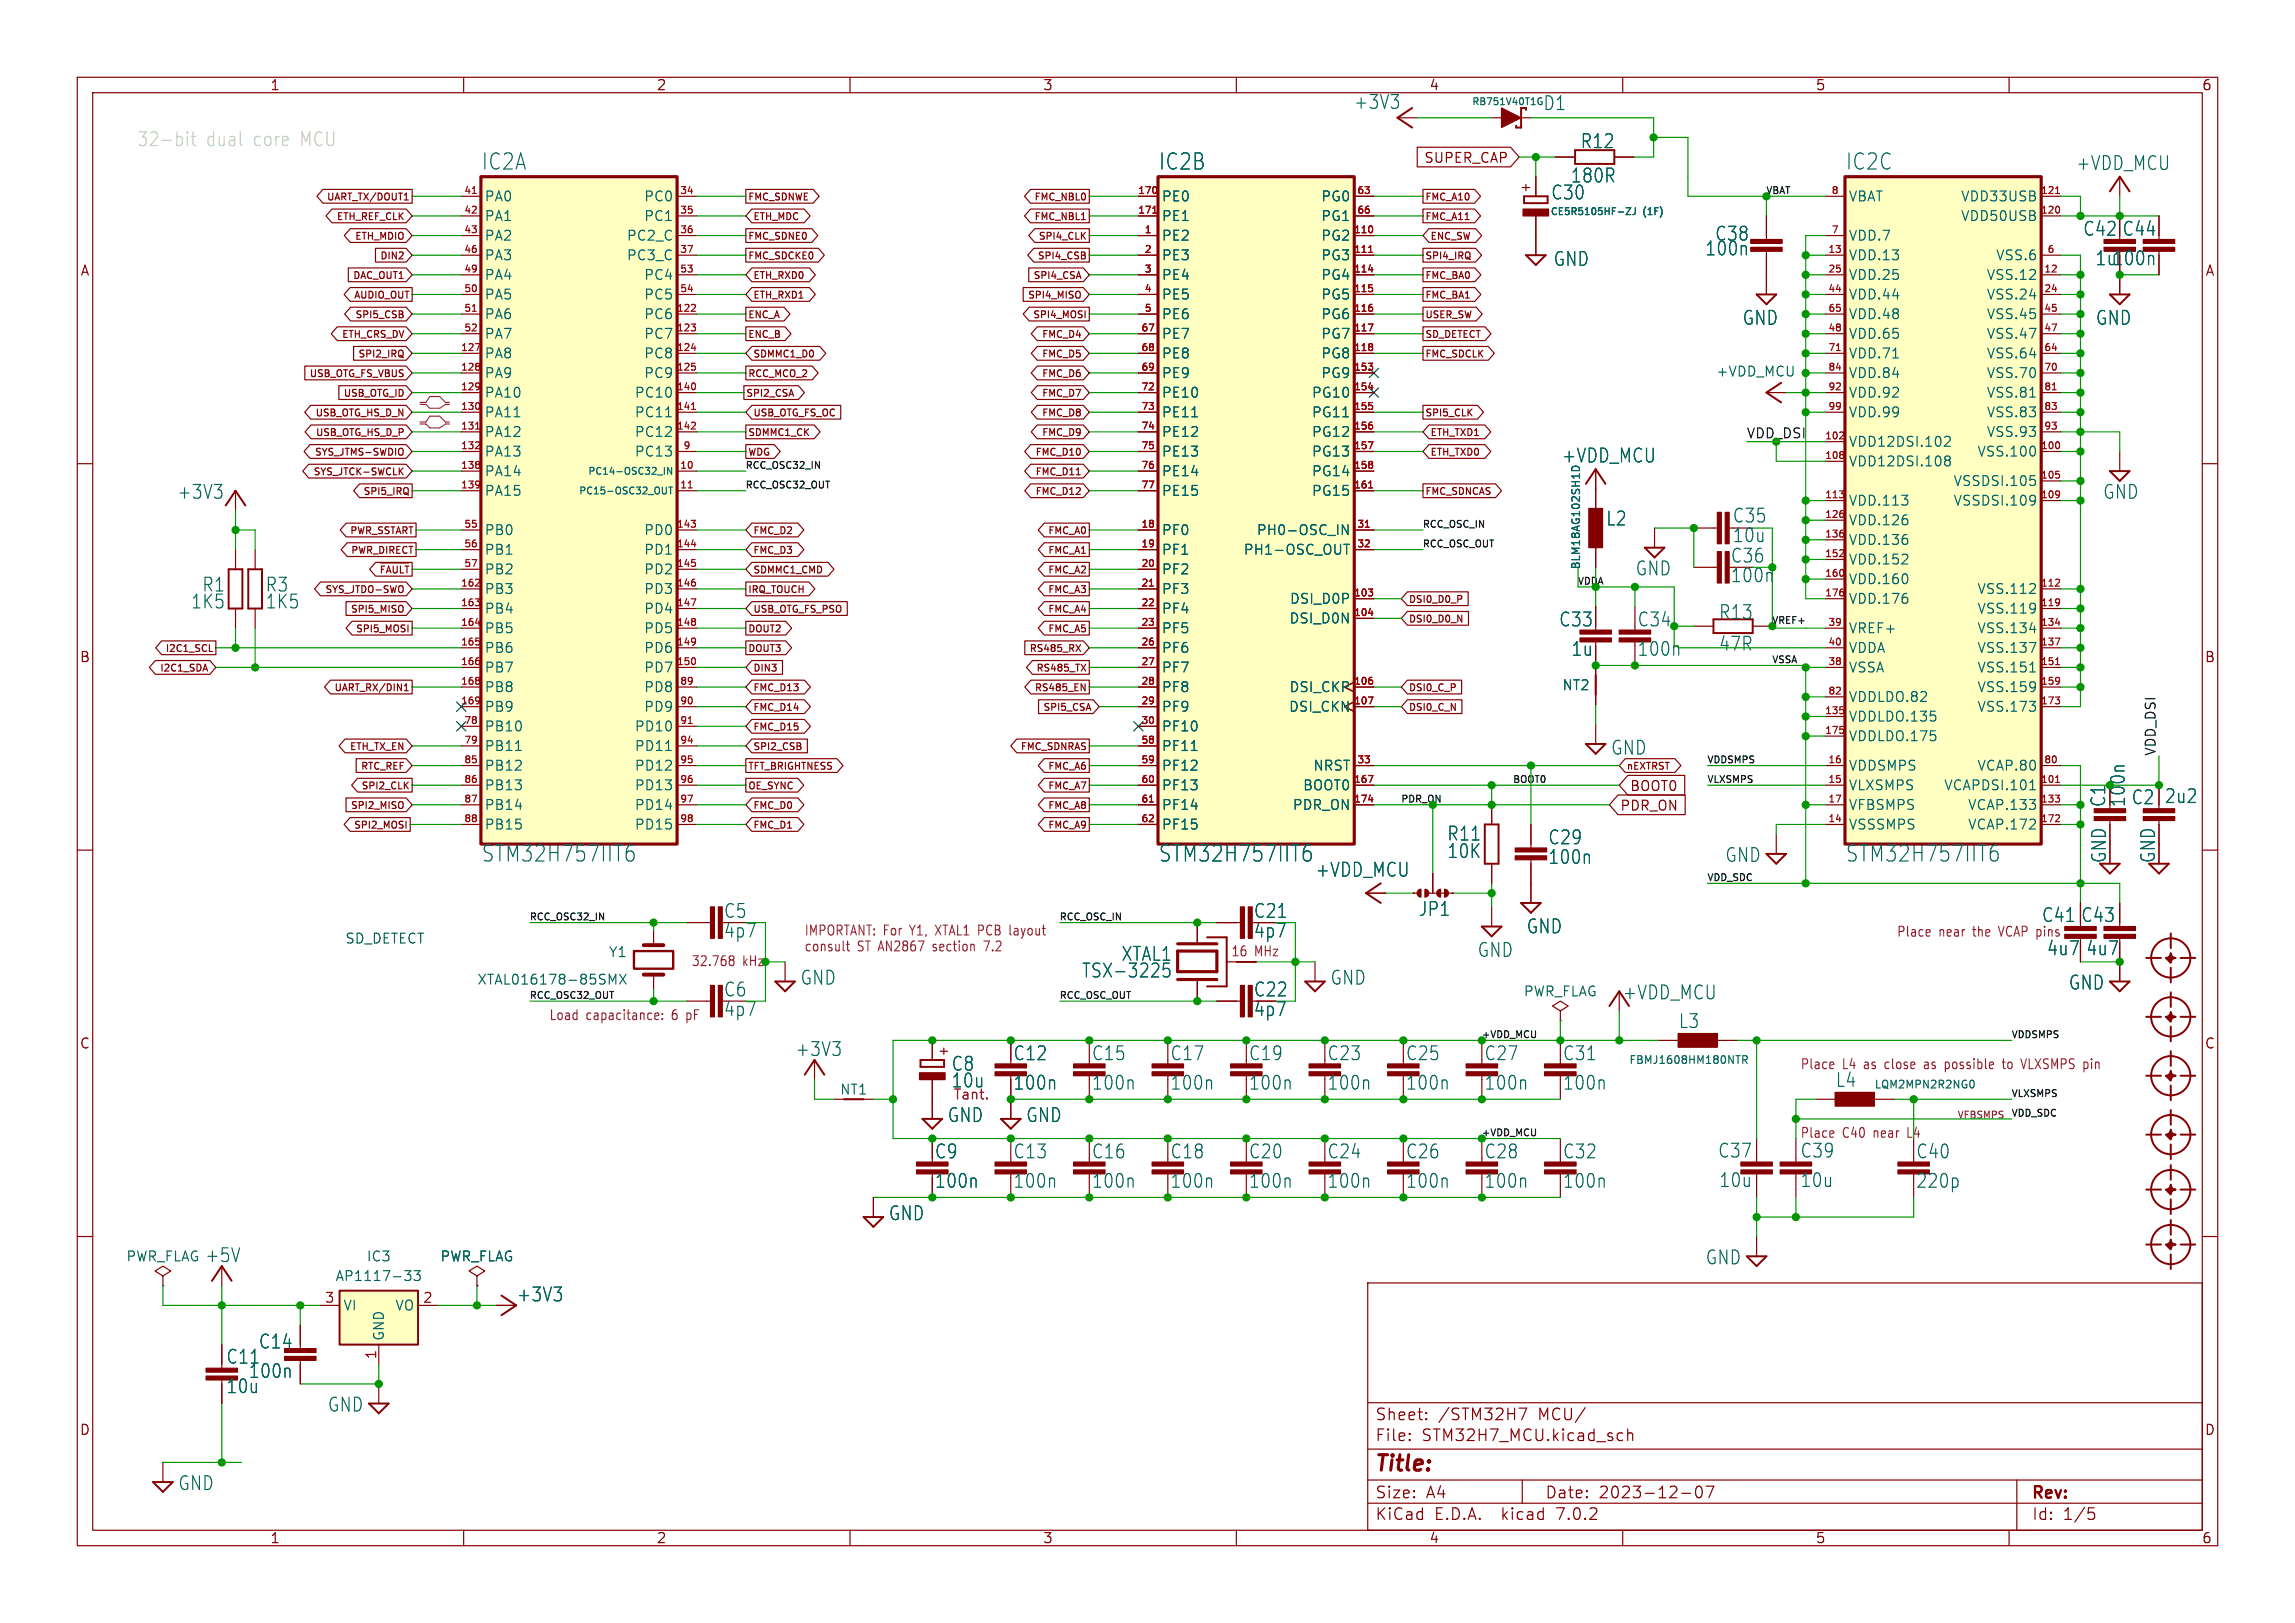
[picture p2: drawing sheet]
<svg xmlns="http://www.w3.org/2000/svg" width="297mm" height="210mm" viewBox="0 0 297 210" stroke-linecap="round" stroke-linejoin="round" font-family="sans-serif">
<defs><g id="words">
<g font-size="2.9" fill="#006464">
<text x="62.3" y="22.1">IC2A</text>
<text x="149.9" y="22.1">IC2B</text>
<text x="238.8" y="22.1">IC2C</text>
<text x="62.3" y="111.7">STM32H757IIT6</text>
<text x="149.9" y="111.7">STM32H757IIT6</text>
<text x="238.8" y="111.7">STM32H757IIT6</text>
</g>
<text font-size="2.8" fill="#840000" x="178" y="190.8">Title:</text>
<g font-size="2.5" fill="#006464">
<text x="175.2" y="14.3">+3V3</text>
<text x="199.7" y="14.4">D1</text>
<text x="203.2" y="23.8">180R</text>
<text x="204.5" y="19.3">R12</text>
<text x="268.7" y="22.2">+VDD_MCU</text>
<text x="200.7" y="26">C30</text>
<text x="201" y="34.6">GND</text>
<text x="220.6" y="33.2">100n</text>
<text x="221.9" y="31.3">C38</text>
<text x="269.6" y="30.7">C42 C44</text>
<text x="271.1" y="34.5">1u100n</text>
<text x="225.5" y="42.2">GND</text>
<text x="271.2" y="42.2">GND</text>
<text x="22.9" y="64.7">+3V3</text>
<text x="202.1" y="60">+VDD_MCU</text>
<text x="272.1" y="64.7">GND</text>
<text x="207.8" y="68.2">L2</text>
<text x="224.2" y="70.3">10u</text>
<text x="224.2" y="67.8">C35</text>
<text x="26.1" y="76.7">R1</text>
<text x="34.3" y="76.7">R3</text>
<text x="211.6" y="74.6">GND</text>
<text x="223.9" y="73">C36</text>
<text x="223.9" y="75.5">100n</text>
<text x="24.7" y="78.9">1K5</text>
<text x="34.3" y="78.9">1K5</text>
<text x="201.7" y="81.2">C33</text>
<text x="211.9" y="81.2">C34</text>
<text x="222.4" y="80.3">R13</text>
<text x="203.3" y="85">1u</text>
<text x="222.4" y="84.4">47R</text>
<text x="208.5" y="97.8">GND</text>
<text x="275.8" y="104.2">C2</text>
<text x="170.2" y="113.6">+VDD_MCU</text>
<text x="187.3" y="108.9">R11</text>
<text x="187.3" y="111.2">10K</text>
<text x="200.3" y="109.4">C29</text>
<text x="200.3" y="112">100n</text>
<text x="223.2" y="111.7">GND</text>
<text x="93.6" y="119">C5</text>
<text x="183.6" y="118.7">JP1</text>
<text x="264.2" y="119.5">C41 C43</text>
<text x="93.6" y="121.5">4p7</text>
<text x="145.1" y="124.5">XTAL1</text>
<text x="162.2" y="121.5">4p7</text>
<text x="191.2" y="124">GND</text>
<text x="197.5" y="120.9">GND</text>
<text x="264.9" y="123.8">4u7</text>
<text x="269.9" y="123.8">4u7</text>
<text x="93.6" y="129.1">C6</text>
<text x="93.6" y="131.7">4p7</text>
<text x="103.6" y="127.6">GND</text>
<text x="140" y="126.7">TSX-3225</text>
<text x="162.2" y="131.7">4p7</text>
<text x="172.1" y="127.6">GND</text>
<text x="210" y="129.5">+VDD_MCU</text>
<text x="267.7" y="128.2">GND</text>
<text x="102.9" y="136.8">+3V3</text>
<text x="131.1" y="137.4">C12</text>
<text x="141.3" y="137.4">C15</text>
<text x="151.4" y="137.4">C17</text>
<text x="161.6" y="137.4">C19</text>
<text x="171.7" y="137.4">C23</text>
<text x="181.9" y="137.4">C25</text>
<text x="192.1" y="137.4">C27</text>
<text x="202.2" y="137.4">C31</text>
<text x="217.2" y="133.2">L3</text>
<text x="123.1" y="138.7">C8</text>
<text x="123.1" y="140.9">10u</text>
<text x="131.1" y="141.2">100n</text>
<text x="141.3" y="141.2">100n</text>
<text x="151.4" y="141.2">100n</text>
<text x="161.6" y="141.2">100n</text>
<text x="171.7" y="141.2">100n</text>
<text x="181.9" y="141.2">100n</text>
<text x="192.1" y="141.2">100n</text>
<text x="202.2" y="141.2">100n</text>
<text x="122.6" y="145.4">GND</text>
<text x="132.8" y="145.4">GND</text>
<text x="222.3" y="150">C37</text>
<text x="233" y="150">C39</text>
<text x="120.9" y="150.1">C9</text>
<text x="120.9" y="153.9">100n</text>
<text x="131.1" y="150.1">C13</text>
<text x="131.1" y="153.9">100n</text>
<text x="141.3" y="150.1">C16</text>
<text x="141.3" y="153.9">100n</text>
<text x="151.4" y="150.1">C18</text>
<text x="151.4" y="153.9">100n</text>
<text x="161.6" y="150.1">C20</text>
<text x="161.6" y="153.9">100n</text>
<text x="171.7" y="150.1">C24</text>
<text x="171.7" y="153.9">100n</text>
<text x="181.9" y="150.1">C26</text>
<text x="181.9" y="153.9">100n</text>
<text x="192.1" y="150.1">C28</text>
<text x="192.1" y="153.9">100n</text>
<text x="202.2" y="150.1">C32</text>
<text x="202.2" y="153.9">100n</text>
<text x="222.5" y="153.8">10u</text>
<text x="233" y="153.8">10u</text>
<text x="247.9" y="150.1">C40</text>
<text x="247.9" y="153.9">220p</text>
<text x="115" y="158.1">GND</text>
<text x="26.5" y="163.5">+5V</text>
<text x="220.7" y="163.8">GND</text>
<text x="66.8" y="168.6">+3V3</text>
<text x="29.3" y="176.6">C11</text>
<text x="32.2" y="178.5">100n</text>
<text x="33.5" y="174.7">C14</text>
<text x="29.3" y="180.4">10u</text>
<text x="42.4" y="182.8">GND</text>
<text x="23" y="193">GND</text>
</g>
<g font-size="2.5" fill="#c2c2c2">
<text x="17.8" y="19.1">32-bit</text>
<text x="26.7" y="19.1">dual</text>
<text x="32.8" y="19.1">core</text>
<text x="39" y="19.1">MCU</text>
</g>
<g font-size="2.5" fill="#009600">
<text x="211.9" y="85">100n</text>
<text x="275.2" y="104.5" transform="rotate(-90 275.2 104.5)">100n</text>
</g>
<g font-size="2.5" fill="#840000">
<text x="272.6" y="104.5" transform="rotate(-90 272.6 104.5)">C1</text>
<text x="280.1" y="104.1">2u2</text>
<text x="272.7" y="111.7" transform="rotate(-90 272.7 111.7)">GND</text>
<text x="279.1" y="111.7" transform="rotate(-90 279.1 111.7)">GND</text>
<text x="162.2" y="119">C21</text>
<text x="162.2" y="129.1">C22</text>
</g>
<text font-size="2.5" fill="#840084" x="237.5" y="140.8">L4</text>
<g font-size="2.1" fill="#840000">
<text x="178" y="183.9">Sheet:</text>
<text x="186.2" y="183.9">/STM32H7</text>
<text x="199.1" y="183.9">MCU/</text>
<text x="178" y="186.6">File:</text>
<text x="184" y="186.6">STM32H7_MCU.kicad_sch</text>
<text x="178" y="196.8">KiCad</text>
<text x="178" y="194">Size:</text>
<text x="184.6" y="194">A4</text>
<text x="185.7" y="196.8">E.D.A.</text>
<text x="194.4" y="196.8">kicad</text>
<text x="200" y="194">Date:</text>
<text x="201.5" y="196.8">7.0.2</text>
<text x="206.9" y="194">2023-12-07</text>
<text x="263" y="194.2">Rev:</text>
<text x="263" y="196.8">Id:</text>
<text x="267" y="196.8">1/5</text>
</g>
<g font-size="1.8" fill="#840000">
<text x="35" y="11.8">1</text>
<text x="85" y="11.8">2</text>
<text x="135" y="11.8">3</text>
<text x="185" y="11.8">4</text>
<text x="235" y="11.8">5</text>
<text x="285" y="11.8">6</text>
<text x="184.2" y="21.2">SUPER_CAP</text>
<text x="198.2" y="25" transform="rotate(-90 198.2 25)">+</text>
<text x="10.4" y="35.8">A</text>
<text x="285.4" y="35.8">A</text>
<text x="10.3" y="85.8">B</text>
<text x="285.3" y="85.8">B</text>
<text x="209.7" y="105.1">PDR_ON</text>
<text x="211" y="102.5">BOOT0</text>
<text x="10.3" y="135.8">C</text>
<text x="122.9" y="136.8" transform="rotate(-90 122.9 136.8)">+</text>
<text x="285.3" y="135.8">C</text>
<text x="10.3" y="185.8">D</text>
<text x="285.3" y="185.8">D</text>
<text x="35" y="199.8">1</text>
<text x="85" y="199.8">2</text>
<text x="135" y="199.8">3</text>
<text x="185" y="199.8">4</text>
<text x="235" y="199.8">5</text>
<text x="285" y="199.8">6</text>
</g>
<g font-size="1.8" fill="#006464">
<text x="62.7" y="26.2">PA0</text>
<text x="62.7" y="28.8">PA1</text>
<text x="83.2" y="26.2">PC0</text>
<text x="83.2" y="28.8">PC1</text>
<text x="150.4" y="26.2">PE0</text>
<text x="150.4" y="28.8">PE1</text>
<text x="170.9" y="26.2">PG0</text>
<text x="170.9" y="28.8">PG1</text>
<text x="239.3" y="26.2">VBAT</text>
<text x="253.7" y="28.8">VDD50USB</text>
<text x="253.7" y="26.2">VDD33USB</text>
<text x="62.7" y="31.3">PA2</text>
<text x="62.7" y="33.8">PA3</text>
<text x="81" y="31.3">PC2_C</text>
<text x="81" y="33.8">PC3_C</text>
<text x="150.4" y="31.3">PE2</text>
<text x="150.4" y="33.8">PE3</text>
<text x="170.9" y="31.3">PG2</text>
<text x="170.9" y="33.8">PG3</text>
<text x="239.3" y="33.8">VDD.13</text>
<text x="239.3" y="31.3">VDD.7</text>
<text x="258.2" y="33.8">VSS.6</text>
<text x="62.7" y="36.4">PA4</text>
<text x="62.7" y="38.9">PA5</text>
<text x="62.7" y="41.5">PA6</text>
<text x="83.2" y="41.5">PC6</text>
<text x="83.2" y="36.4">PC4</text>
<text x="83.2" y="38.9">PC5</text>
<text x="150.4" y="36.4">PE4</text>
<text x="150.4" y="38.9">PE5</text>
<text x="150.4" y="41.5">PE6</text>
<text x="170.9" y="36.4">PG4</text>
<text x="170.9" y="38.9">PG5</text>
<text x="170.9" y="41.5">PG6</text>
<text x="239.3" y="36.4">VDD.25</text>
<text x="239.3" y="38.9">VDD.44</text>
<text x="239.3" y="41.5">VDD.48</text>
<text x="257" y="36.4">VSS.12</text>
<text x="257" y="38.9">VSS.24</text>
<text x="257" y="41.5">VSS.45</text>
<text x="62.7" y="46.5">PA8</text>
<text x="62.7" y="44">PA7</text>
<text x="83.2" y="44">PC7</text>
<text x="83.2" y="46.5">PC8</text>
<text x="150.4" y="44">PE7</text>
<text x="150.4" y="46.5">PE8</text>
<text x="170.9" y="44">PG7</text>
<text x="170.9" y="46.5">PG8</text>
<text x="239.3" y="44">VDD.65</text>
<text x="239.3" y="46.5">VDD.71</text>
<text x="257" y="44">VSS.47</text>
<text x="257" y="46.5">VSS.64</text>
<text x="62.7" y="49.1">PA9</text>
<text x="62.7" y="51.6">PA10</text>
<text x="82" y="51.6">PC10</text>
<text x="83.2" y="49.1">PC9</text>
<text x="150.4" y="49.1">PE9</text>
<text x="150.4" y="51.6">PE10</text>
<text x="169.7" y="51.6">PG10</text>
<text x="170.9" y="49.1">PG9</text>
<text x="222.1" y="48.9">+VDD_MCU</text>
<text x="239.3" y="49.1">VDD.84</text>
<text x="239.3" y="51.6">VDD.92</text>
<text x="257" y="49.1">VSS.70</text>
<text x="257" y="51.6">VSS.81</text>
<text x="62.7" y="54.2">PA11</text>
<text x="62.7" y="56.7">PA12</text>
<text x="62.7" y="59.2">PA13</text>
<text x="82" y="54.2">PC11</text>
<text x="82" y="56.7">PC12</text>
<text x="82" y="59.2">PC13</text>
<text x="150.4" y="54.2">PE11</text>
<text x="150.4" y="56.7">PE12</text>
<text x="150.4" y="59.2">PE13</text>
<text x="169.7" y="54.2">PG11</text>
<text x="169.7" y="56.7">PG12</text>
<text x="169.7" y="59.2">PG13</text>
<text x="239.3" y="58">VDD12DSI.102</text>
<text x="239.3" y="54.2">VDD.99</text>
<text x="255.8" y="59.2">VSS.100</text>
<text x="257" y="54.2">VSS.83</text>
<text x="257" y="56.7">VSS.93</text>
<text x="62.7" y="61.8">PA14</text>
<text x="62.7" y="64.3">PA15</text>
<text x="150.4" y="61.8">PE14</text>
<text x="150.4" y="64.3">PE15</text>
<text x="169.7" y="61.8">PG14</text>
<text x="169.7" y="64.3">PG15</text>
<text x="239.3" y="60.5">VDD12DSI.108</text>
<text x="239.3" y="65.6">VDD.113</text>
<text x="252.7" y="63.1">VSSDSI.105</text>
<text x="252.7" y="65.6">VSSDSI.109</text>
<text x="62.7" y="69.4">PB0</text>
<text x="62.7" y="71.9">PB1</text>
<text x="83.2" y="69.4">PD0</text>
<text x="83.2" y="71.9">PD1</text>
<text x="150.4" y="69.4">PF0</text>
<text x="150.4" y="71.9">PF1</text>
<text x="160.8" y="71.9">PH1-OSC_OUT</text>
<text x="162.5" y="69.4">PH0-OSC_IN</text>
<text x="239.3" y="68.1">VDD.126</text>
<text x="239.3" y="70.7">VDD.136</text>
<text x="62.7" y="77">PB3</text>
<text x="62.7" y="74.5">PB2</text>
<text x="83.2" y="74.5">PD2</text>
<text x="83.2" y="77">PD3</text>
<text x="150.4" y="74.5">PF2</text>
<text x="150.4" y="77">PF3</text>
<text x="239.3" y="73.2">VDD.152</text>
<text x="239.3" y="75.8">VDD.160</text>
<text x="255.8" y="77">VSS.112</text>
<text x="62.7" y="79.6">PB4</text>
<text x="62.7" y="82.1">PB5</text>
<text x="83.2" y="79.6">PD4</text>
<text x="83.2" y="82.1">PD5</text>
<text x="150.4" y="79.6">PF4</text>
<text x="150.4" y="82.1">PF5</text>
<text x="166.8" y="80.8">DSI_D0N</text>
<text x="166.8" y="78.3">DSI_D0P</text>
<text x="239.3" y="78.3">VDD.176</text>
<text x="239.3" y="82.1">VREF+</text>
<text x="255.8" y="79.6">VSS.119</text>
<text x="255.8" y="82.1">VSS.134</text>
<text x="62.7" y="84.6">PB6</text>
<text x="62.7" y="87.2">PB7</text>
<text x="62.7" y="89.7">PB8</text>
<text x="83.2" y="84.6">PD6</text>
<text x="83.2" y="87.2">PD7</text>
<text x="83.2" y="89.7">PD8</text>
<text x="150.4" y="84.6">PF6</text>
<text x="150.4" y="87.2">PF7</text>
<text x="150.4" y="89.7">PF8</text>
<text x="166.8" y="89.7">DSI_CKP</text>
<text x="202.1" y="89.5">NT2</text>
<text x="239.3" y="87.2">VSSA</text>
<text x="239.3" y="84.6">VDDA</text>
<text x="255.8" y="84.6">VSS.137</text>
<text x="255.8" y="87.2">VSS.151</text>
<text x="255.8" y="89.7">VSS.159</text>
<text x="62.7" y="92.3">PB9</text>
<text x="62.7" y="94.8">PB10</text>
<text x="82" y="94.8">PD10</text>
<text x="83.2" y="92.3">PD9</text>
<text x="150.4" y="92.3">PF9</text>
<text x="150.4" y="94.8">PF10</text>
<text x="166.7" y="92.3">DSI_CKN</text>
<text x="239.3" y="93.5">VDDLDO.135</text>
<text x="239.3" y="91">VDDLDO.82</text>
<text x="255.8" y="92.3">VSS.173</text>
<text x="62.7" y="97.3">PB11</text>
<text x="62.7" y="99.9">PB12</text>
<text x="82" y="97.3">PD11</text>
<text x="82" y="99.9">PD12</text>
<text x="150.4" y="97.3">PF11</text>
<text x="150.4" y="99.9">PF12</text>
<text x="169.8" y="99.9">NRST</text>
<text x="239.3" y="99.9">VDDSMPS</text>
<text x="239.3" y="96.1">VDDLDO.175</text>
<text x="255.8" y="99.9">VCAP.80</text>
<text x="62.7" y="102.4">PB13</text>
<text x="62.7" y="105">PB14</text>
<text x="62.7" y="107.5">PB15</text>
<text x="82" y="102.4">PD13</text>
<text x="82" y="105">PD14</text>
<text x="82" y="107.5">PD15</text>
<text x="150.4" y="102.4">PF13</text>
<text x="150.4" y="105">PF14</text>
<text x="150.4" y="107.5">PF15</text>
<text x="167.2" y="105">PDR_ON</text>
<text x="168.5" y="102.4">BOOT0</text>
<text x="239.3" y="107.5">VSSSMPS</text>
<text x="239.3" y="102.4">VLXSMPS</text>
<text x="239.3" y="105">VFBSMPS</text>
<text x="251.5" y="102.4">VCAPDSI.101</text>
<text x="254.6" y="105">VCAP.133</text>
<text x="254.6" y="107.5">VCAP.172</text>
<text x="78.7" y="124">Y1</text>
<text x="61.7" y="127.6">XTAL016178-85SMX</text>
<text x="197.1" y="129.1">PWR_FLAG</text>
<text x="108.7" y="141.8">NT1</text>
<text x="16.3" y="163.4">PWR_FLAG</text>
<text x="43.4" y="165.9">AP1117-33</text>
<text x="47.4" y="163.4">IC3</text>
<text x="56.9" y="163.4">PWR_FLAG</text>
<text x="44.4" y="169.7">VI</text>
<text x="49.8" y="173.5" transform="rotate(-90 49.8 173.5)">GND</text>
<text x="51" y="169.7">VO</text>
</g>
<text font-size="1.8" fill="#009600" x="226.1" y="56.8">VDD_DSI</text>
<text font-size="1.8" fill="#0f0f0f" x="279" y="97.8" transform="rotate(-90 279 97.8)">VDD_DSI</text>
<text font-size="1.8" fill="#0000c2" x="44.7" y="122.2">SD_DETECT</text>
<g font-size="1.8" fill="#840084">
<text x="89.5" y="125.1">32.768</text>
<text x="96.2" y="125.1">kHz</text>
<text x="104.1" y="121.1">IMPORTANT: For</text>
<text x="104.1" y="123.2">consult</text>
<text x="111" y="123.2">ST AN2867</text>
<text x="117.9" y="121.1">Y1, XTAL1 PCB layout</text>
<text x="121" y="123.2">section</text>
<text x="127.8" y="123.2">7.2</text>
<text x="159.4" y="123.8">16</text>
<text x="162.4" y="123.8">MHz</text>
<text x="245.4" y="121.3">Place</text>
<text x="250.8" y="121.3">near</text>
<text x="255.4" y="121.3">the</text>
<text x="258.9" y="121.3">VCAP pins</text>
<text x="71.1" y="132.1">Load</text>
<text x="75.9" y="132.1">capacitance:</text>
<text x="87.1" y="132.1">6 pF</text>
<text x="123.4" y="142.4">Tant.</text>
<text x="233" y="138.4">Place</text>
<text x="238.5" y="138.4">L4 as</text>
<text x="244.2" y="138.4">close</text>
<text x="249.5" y="138.4">as</text>
<text x="252.3" y="138.4">possible</text>
<text x="260" y="138.4">to</text>
<text x="262.6" y="138.4">VLXSMPS pin</text>
<text x="233" y="147.3">Place</text>
<text x="238.5" y="147.3">C40</text>
<text x="242.6" y="147.3">near</text>
<text x="247.2" y="147.3">L4</text>
</g>
<g font-size="1.8" fill="#a90000">
<text x="42" y="168.7">3</text>
<text x="54.7" y="168.7">2</text>
<text x="48.8" y="175.9" transform="rotate(-90 48.8 175.9)">1</text>
</g>
<g font-size="1.4" fill="#006464">
<text x="204.6" y="73.7" transform="rotate(-90 204.6 73.7)">BLM18AG102SH1D</text>
<text x="210.8" y="137.8">FBMJ1608HM180NTR</text>
<text x="242.5" y="141">LQM2MPN2R2NG0</text>
</g>
<g font-size="1.2" fill="#006464">
<text x="190.4" y="13.8">RB751V40T1G</text>
<text x="200.6" y="28">CE5R5105HF-ZJ</text>
<text x="212.6" y="28">(1F)</text>
<text x="74.8" y="64.1">PC15-OSC32_OUT</text>
<text x="76" y="61.6">PC14-OSC32_IN</text>
</g>
<g font-size="1.2" fill="#840000">
<text x="42.1" y="26.1">UART_TX/DOUT1</text>
<text x="43.4" y="28.6">ETH_REF_CLK</text>
<text x="96.9" y="26.1">FMC_SDNWE</text>
<text x="97.5" y="28.6">ETH_MDC</text>
<text x="133.7" y="26.1">FMC_NBL0</text>
<text x="133.7" y="28.6">FMC_NBL1</text>
<text x="184.5" y="26.1">FMC_A10</text>
<text x="184.5" y="28.6">FMC_A11</text>
<text x="45.8" y="31.2">ETH_MDIO</text>
<text x="49" y="33.7">DIN2</text>
<text x="96.9" y="33.7">FMC_SDCKE0</text>
<text x="96.9" y="31.2">FMC_SDNE0</text>
<text x="134.1" y="33.7">SPI4_CSB</text>
<text x="134.3" y="31.2">SPI4_CLK</text>
<text x="184.5" y="33.7">SPI4_IRQ</text>
<text x="185.2" y="31.2">ENC_SW</text>
<text x="45.5" y="36.3">DAC_OUT1</text>
<text x="45.6" y="38.8">AUDIO_OUT</text>
<text x="45.8" y="41.3">SPI5_CSB</text>
<text x="96.9" y="41.3">ENC_A</text>
<text x="97.5" y="36.3">ETH_RXD0</text>
<text x="97.5" y="38.8">ETH_RXD1</text>
<text x="132.9" y="38.8">SPI4_MISO</text>
<text x="133.5" y="41.3">SPI4_MOSI</text>
<text x="133.6" y="36.3">SPI4_CSA</text>
<text x="184.5" y="41.3">USER_SW</text>
<text x="184.5" y="38.8">FMC_BA1</text>
<text x="184.5" y="36.3">FMC_BA0</text>
<text x="44.1" y="43.9">ETH_CRS_DV</text>
<text x="46.2" y="46.4">SPI2_IRQ</text>
<text x="96.9" y="43.9">ENC_B</text>
<text x="97.5" y="46.4">SDMMC1_D0</text>
<text x="134.7" y="43.9">FMC_D4</text>
<text x="134.7" y="46.4">FMC_D5</text>
<text x="184.5" y="46.4">FMC_SDCLK</text>
<text x="184.5" y="43.9">SD_DETECT</text>
<text x="39.9" y="49">USB_OTG_FS_VBUS</text>
<text x="44.3" y="51.5">USB_OTG_ID</text>
<text x="96.6" y="51.5">SPI2_CSA</text>
<text x="96.9" y="49">RCC_MCO_2</text>
<text x="134.7" y="49">FMC_D6</text>
<text x="134.7" y="51.5">FMC_D7</text>
<text x="40.6" y="59.1">SYS_JTMS-SWDIO</text>
<text x="40.7" y="54">USB_OTG_HS_D_N</text>
<text x="40.7" y="56.6">USB_OTG_HS_D_P</text>
<text x="96.9" y="56.6">SDMMC1_CK</text>
<text x="96.9" y="59.1">WDG</text>
<text x="97.5" y="54">USB_OTG_FS_OC</text>
<text x="133.8" y="59.1">FMC_D10</text>
<text x="134.7" y="54">FMC_D8</text>
<text x="134.7" y="56.6">FMC_D9</text>
<text x="184.5" y="54">SPI5_CLK</text>
<text x="185.2" y="56.6">ETH_TXD1</text>
<text x="185.2" y="59.1">ETH_TXD0</text>
<text x="40.4" y="61.7">SYS_JTCK-SWCLK</text>
<text x="46.9" y="64.2">SPI5_IRQ</text>
<text x="133.8" y="64.2">FMC_D12</text>
<text x="133.8" y="61.7">FMC_D11</text>
<text x="184.5" y="64.2">FMC_SDNCAS</text>
<text x="45.1" y="69.3">PWR_SSTART</text>
<text x="45.3" y="71.8">PWR_DIRECT</text>
<text x="97.5" y="69.3">FMC_D2</text>
<text x="97.5" y="71.8">FMC_D3</text>
<text x="135.5" y="69.3">FMC_A0</text>
<text x="135.5" y="71.8">FMC_A1</text>
<text x="41.9" y="76.9">SYS_JTDO-SWO</text>
<text x="49" y="74.8">~{FAULT}</text>
<text x="96.9" y="76.9">IRQ_TOUCH</text>
<text x="97.5" y="74.4">SDMMC1_CMD</text>
<text x="135.5" y="76.9">FMC_A3</text>
<text x="135.5" y="74.4">FMC_A2</text>
<text x="45.2" y="79.4">SPI5_MISO</text>
<text x="45.9" y="82">SPI5_MOSI</text>
<text x="96.9" y="82">DOUT2</text>
<text x="97.5" y="79.4">USB_OTG_FS_PSO</text>
<text x="135.5" y="79.4">FMC_A4</text>
<text x="135.5" y="82">FMC_A5</text>
<text x="182.4" y="80.7">DSI0_D0_N</text>
<text x="182.4" y="78.2">DSI0_D0_P</text>
<text x="20.6" y="87.1">I2C1_SDA</text>
<text x="21.3" y="84.5">I2C1_SCL</text>
<text x="43.1" y="89.6">UART_RX/DIN1</text>
<text x="96.9" y="84.5">DOUT3</text>
<text x="97.5" y="89.6">FMC_D13</text>
<text x="97.5" y="87.1">DIN3</text>
<text x="133.1" y="84.5">RS485_RX</text>
<text x="133.7" y="89.6">RS485_EN</text>
<text x="134" y="87.1">RS485_TX</text>
<text x="182.4" y="89.6">DSI0_C_P</text>
<text x="97.5" y="92.1">FMC_D14</text>
<text x="97.5" y="94.7">FMC_D15</text>
<text x="134.9" y="92.1">SPI5_CSA</text>
<text x="182.4" y="92.1">DSI0_C_N</text>
<text x="45.1" y="97.2">ETH_TX_EN</text>
<text x="46.5" y="99.8">RTC_REF</text>
<text x="96.9" y="99.8">TFT_BRIGHTNESS</text>
<text x="97.5" y="97.2">SPI2_CSB</text>
<text x="131.9" y="97.2">FMC_SDNRAS</text>
<text x="135.5" y="99.8">FMC_A6</text>
<text x="210.6" y="99.8">nEXTRST</text>
<text x="45.2" y="104.8">SPI2_MISO</text>
<text x="45.6" y="107.4">SPI2_MOSI</text>
<text x="46.6" y="102.3">SPI2_CLK</text>
<text x="96.9" y="102.3">OE_SYNC</text>
<text x="97.5" y="104.8">FMC_D0</text>
<text x="97.5" y="107.4">FMC_D1</text>
<text x="135.5" y="102.3">FMC_A7</text>
<text x="135.5" y="107.4">FMC_A9</text>
<text x="135.5" y="104.8">FMC_A8</text>
</g>
<g font-size="1.2" fill="#a90000">
<text x="60" y="25.1">41</text>
<text x="60" y="27.7">42</text>
<text x="88" y="25.1">34</text>
<text x="88" y="27.7">35</text>
<text x="147.2" y="25.1">170</text>
<text x="147.2" y="27.7">171</text>
<text x="175.6" y="25.1">63</text>
<text x="175.6" y="27.7">66</text>
<text x="237" y="25.1">8</text>
<text x="264.1" y="27.7">120</text>
<text x="264.1" y="25.1">121</text>
<text x="60" y="30.2">43</text>
<text x="60" y="32.8">46</text>
<text x="60" y="35.3">49</text>
<text x="88" y="30.2">36</text>
<text x="88" y="32.8">37</text>
<text x="88" y="35.3">53</text>
<text x="148.1" y="30.2">1</text>
<text x="148.1" y="32.8">2</text>
<text x="148.1" y="35.3">3</text>
<text x="175.2" y="30.2">110</text>
<text x="175.2" y="32.8">111</text>
<text x="175.2" y="35.3">114</text>
<text x="236.5" y="32.8">13</text>
<text x="236.5" y="35.3">25</text>
<text x="237" y="30.2">7</text>
<text x="264.5" y="35.3">12</text>
<text x="264.9" y="32.8">6</text>
<text x="60" y="37.8">50</text>
<text x="60" y="40.4">51</text>
<text x="87.5" y="40.4">122</text>
<text x="88" y="37.8">54</text>
<text x="148.1" y="37.8">4</text>
<text x="148.1" y="40.4">5</text>
<text x="175.2" y="37.8">115</text>
<text x="175.2" y="40.4">116</text>
<text x="236.5" y="37.8">44</text>
<text x="236.5" y="40.4">65</text>
<text x="264.5" y="37.8">24</text>
<text x="264.5" y="40.4">45</text>
<text x="59.6" y="45.5">127</text>
<text x="60" y="42.9">52</text>
<text x="87.5" y="42.9">123</text>
<text x="87.5" y="45.5">124</text>
<text x="147.6" y="42.9">67</text>
<text x="147.6" y="45.5">68</text>
<text x="175.2" y="42.9">117</text>
<text x="175.2" y="45.5">118</text>
<text x="236.5" y="42.9">48</text>
<text x="236.5" y="45.5">71</text>
<text x="264.5" y="42.9">47</text>
<text x="264.5" y="45.5">64</text>
<text x="59.6" y="48">128</text>
<text x="59.6" y="50.5">129</text>
<text x="59.6" y="53.1">130</text>
<text x="87.5" y="48">125</text>
<text x="87.5" y="50.5">140</text>
<text x="87.5" y="53.1">141</text>
<text x="147.6" y="48">69</text>
<text x="147.6" y="50.5">72</text>
<text x="147.6" y="53.1">73</text>
<text x="175.2" y="48">153</text>
<text x="175.2" y="50.5">154</text>
<text x="175.2" y="53.1">155</text>
<text x="236.5" y="48">84</text>
<text x="236.5" y="50.5">92</text>
<text x="236.5" y="53.1">99</text>
<text x="264.5" y="48">70</text>
<text x="264.5" y="50.5">81</text>
<text x="264.5" y="53.1">83</text>
<text x="59.6" y="55.6">131</text>
<text x="59.6" y="58.2">132</text>
<text x="87.5" y="55.6">142</text>
<text x="88.4" y="58.2">9</text>
<text x="147.6" y="55.6">74</text>
<text x="147.6" y="58.2">75</text>
<text x="175.2" y="55.6">156</text>
<text x="175.2" y="58.2">157</text>
<text x="236.1" y="56.9">102</text>
<text x="236.1" y="59.4">108</text>
<text x="264.1" y="58.2">100</text>
<text x="264.5" y="55.6">93</text>
<text x="59.6" y="60.7">138</text>
<text x="59.6" y="63.2">139</text>
<text x="88" y="60.7">10</text>
<text x="88" y="63.2">11</text>
<text x="147.6" y="60.7">76</text>
<text x="147.6" y="63.2">77</text>
<text x="175.2" y="60.7">158</text>
<text x="175.2" y="63.2">161</text>
<text x="236.1" y="64.5">113</text>
<text x="264.1" y="62">105</text>
<text x="264.1" y="64.5">109</text>
<text x="60" y="68.3">55</text>
<text x="60" y="70.9">56</text>
<text x="87.5" y="68.3">143</text>
<text x="87.5" y="70.9">144</text>
<text x="147.6" y="68.3">18</text>
<text x="147.6" y="70.9">19</text>
<text x="175.6" y="68.3">31</text>
<text x="175.6" y="70.9">32</text>
<text x="236.1" y="67.1">126</text>
<text x="236.1" y="69.6">136</text>
<text x="59.6" y="75.9">162</text>
<text x="60" y="73.4">57</text>
<text x="87.5" y="73.4">145</text>
<text x="87.5" y="75.9">146</text>
<text x="147.6" y="73.4">20</text>
<text x="147.6" y="75.9">21</text>
<text x="175.2" y="77.2">103</text>
<text x="236.1" y="72.1">152</text>
<text x="236.1" y="74.7">160</text>
<text x="236.1" y="77.2">176</text>
<text x="264.1" y="75.9">112</text>
<text x="59.6" y="78.5">163</text>
<text x="59.6" y="81">164</text>
<text x="59.6" y="83.6">165</text>
<text x="87.5" y="78.5">147</text>
<text x="87.5" y="81">148</text>
<text x="87.5" y="83.6">149</text>
<text x="147.6" y="78.5">22</text>
<text x="147.6" y="81">23</text>
<text x="147.6" y="83.6">26</text>
<text x="175.2" y="79.8">104</text>
<text x="236.5" y="81">39</text>
<text x="236.5" y="83.6">40</text>
<text x="264.1" y="78.5">119</text>
<text x="264.1" y="81">134</text>
<text x="264.1" y="83.6">137</text>
<text x="59.6" y="86.1">166</text>
<text x="59.6" y="88.6">168</text>
<text x="87.5" y="86.1">150</text>
<text x="88" y="88.6">89</text>
<text x="147.6" y="86.1">27</text>
<text x="147.6" y="88.6">28</text>
<text x="175.2" y="88.6">106</text>
<text x="236.5" y="86.1">38</text>
<text x="236.5" y="89.9">82</text>
<text x="264.1" y="86.1">151</text>
<text x="264.1" y="88.6">159</text>
<text x="59.6" y="91.2">169</text>
<text x="60" y="93.7">78</text>
<text x="88" y="91.2">90</text>
<text x="88" y="93.7">91</text>
<text x="147.6" y="91.2">29</text>
<text x="147.6" y="93.7">30</text>
<text x="175.2" y="91.2">107</text>
<text x="236.1" y="92.5">135</text>
<text x="236.1" y="95">175</text>
<text x="264.1" y="91.2">173</text>
<text x="60" y="96.3">79</text>
<text x="60" y="98.8">85</text>
<text x="60" y="101.3">86</text>
<text x="88" y="96.3">94</text>
<text x="88" y="98.8">95</text>
<text x="88" y="101.3">96</text>
<text x="147.6" y="96.3">58</text>
<text x="147.6" y="98.8">59</text>
<text x="147.6" y="101.3">60</text>
<text x="175.2" y="101.3">167</text>
<text x="175.6" y="98.8">33</text>
<text x="236.5" y="101.3">15</text>
<text x="236.5" y="98.8">16</text>
<text x="264.1" y="101.3">101</text>
<text x="264.5" y="98.8">80</text>
<text x="60" y="103.9">87</text>
<text x="60" y="106.4">88</text>
<text x="88" y="103.9">97</text>
<text x="88" y="106.4">98</text>
<text x="147.6" y="103.9">61</text>
<text x="147.6" y="106.4">62</text>
<text x="175.2" y="103.9">174</text>
<text x="236.5" y="106.4">14</text>
<text x="236.5" y="103.9">17</text>
<text x="264.1" y="103.9">133</text>
<text x="264.1" y="106.4">172</text>
</g>
<g font-size="1.2" fill="#0f0f0f">
<text x="228.6" y="25.2">VBAT</text>
<text x="96.5" y="63.3">RCC_OSC32_OUT</text>
<text x="96.5" y="60.7">RCC_OSC32_IN</text>
<text x="184.1" y="70.9">RCC_OSC_OUT</text>
<text x="184.1" y="68.3">RCC_OSC_IN</text>
<text x="204.2" y="75.7">VDDA</text>
<text x="229.4" y="85.9">VSSA</text>
<text x="195.8" y="101.4">BOOT0</text>
<text x="221" y="98.8">VDDSMPS</text>
<text x="221" y="101.4">VLXSMPS</text>
<text x="181.4" y="103.9">PDR_ON</text>
<text x="68.6" y="119.1">RCC_OSC32_IN</text>
<text x="137.2" y="119.1">RCC_OSC_IN</text>
<text x="221" y="114.1">VDD_SDC</text>
<text x="68.6" y="129.3">RCC_OSC32_OUT</text>
<text x="137.2" y="129.3">RCC_OSC_OUT</text>
<text x="191.8" y="134.4">+VDD_MCU</text>
<text x="260.3" y="134.4">VDDSMPS</text>
<text x="260.3" y="142">VLXSMPS</text>
<text x="191.8" y="147.1">+VDD_MCU</text>
<text x="260.3" y="144.5">VDD_SDC</text>
</g>
<text font-size="1.2" fill="#009600" x="229.4" y="80.8">VREF+</text>
<text font-size="1.2" fill="#840084" x="253.4" y="144.8">VFBSMPS</text>
</g></defs>
<g fill="none" stroke="#840000" stroke-width=".15">
<path d="M10 10h277v190h-277zM12 12h273v186h-273zM60 10v2M110 10v2M160 10v2M180.8 15.2h2.6M183.4 19h12.1l1.1 1.3-1.1 1.3h-12.1zM193 15.2h5.1M210 10v2M260 10v2M41.8 24.5h11.5v1.8h-11.5l-.8-.9zM43 27.1h9.6l.7 .8-.7 .9h-9.6l-.8-.9z"/>
<path d="M45.1 34.7h7.5l.7 .9-.7 .8h-7.5zM45.3 37.2h8v1.8h-8l-.8-.9zM45.3 29.6h7.3l.7 .9-.7 .9h-7.3l-.7-.9zM45.4 39.8h7.2l.7 .8-.7 .9h-7.2l-.8-.9zM48.6 32.1h4l.7 .9-.7 .9h-4zM52.3 25.9h.5M52.5 25.1l.1-.1v.9M59.7 35.6h2.5M59.7 27.9h2.5M59.7 25.4h2.5M59.7 33h2.5M59.7 38.1h2.5"/>
<path d="M59.7 30.5h2.5M87.6 35.6h2.6M87.6 27.9h2.6M87.6 25.4h2.6M87.6 33h2.6M87.6 38.1h2.6M87.6 30.5h2.6M96.5 32.1h9.4l.8 .9-.8 .9h-9.4zM96.5 24.5h8.7l.8 .9-.8 .9h-8.7zM96.5 39.8h5l.7 .8-.7 .9h-5zM96.5 29.6h8.6l.7 .9-.7 .9h-8.6zM97.3 34.7h7.4l.8 .9-.8 .8h-7.4l-.8-.8z"/>
<path d="M97.3 27.1h6.8l.7 .8-.7 .9h-6.8l-.8-.9zM97.3 37.2h7.4l.8 .9-.8 .9h-7.4l-.8-.9zM132.4 37.2h7.8l.8 .9-.8 .9h-7.8zM133.1 34.7h7.1l.8 .9-.8 .8h-7.1zM133.2 39.8h7.8v1.7h-7.8l-.8-.9zM133.4 24.5h7.6v1.8h-7.6l-.8-.9zM133.4 27.1h7.6v1.7h-7.6l-.8-.9zM133.8 32.1h7.2v1.8h-7.2l-.8-.9zM133.9 29.6h7.1v1.8h-7.1l-.8-.9zM139.8 37.8v.6M140 28.4h.5M140.1 30.4l.4 .6"/>
<path d="M140.4 33.1v.3M140.5 30.1l-.5 .5M147.3 35.6h2.6M147.3 27.9h2.6M147.3 25.4h2.6M147.3 33h2.6M147.3 38.1h2.6M147.3 30.5h2.6M175.3 35.6h2.5M175.3 27.9h2.5M175.3 25.4h2.5M175.3 33h2.5"/>
<path d="M175.3 38.1h2.5M175.3 30.5h2.5M184.1 39.8h6.9l.8 .8-.8 .9h-6.9zM184.1 24.5h6.7l.8 .9-.8 .9h-6.7zM184.1 27.1h6.7l.8 .8-.8 .9h-6.7zM184.1 37.2h6.8l.7 .9-.7 .9h-6.8zM184.1 34.7h6.8l.7 .9-.7 .8h-6.8zM184.1 32.1h6.9l.7 .9-.7 .9h-6.9zM184.9 29.6h6.1l.7 .9-.7 .9h-6.1l-.8-.9zM198.8 22.9v2.5M198.8 27.9v5.1M201.3 20.3h2.5"/>
<path d="M208.9 20.3h2.6M228.6 27.9v3.1M228.6 32.5v5.6M236.2 35.6h2.6M236.2 25.4h2.6M236.2 33h2.6M236.2 38.1h2.6M236.2 30.5h2.6M264.2 35.6h2.5M264.2 27.9h2.5M264.2 25.4h2.5M264.2 33h2.5"/>
<path d="M264.2 38.1h2.5M274.3 22.9v2.5M274.3 27.9v2.6M274.3 33v5.1M279.4 27.9v3.1M279.4 32.5v3.1M10 60h2M39.4 47.4h13.2l.7 .9-.7 .8h-13.2zM40.1 57.5h12.5l.7 .9-.7 .9h-12.5l-.8-.9zM40.2 52.5h12.4l.7 .8-.7 .9h-12.4l-.8-.9zM40.3 55h12.3l.7 .9-.7 .9h-12.3l-.8-.9zM43.6 42.3h9l.7 .9-.7 .9h-9l-.7-.9z"/>
<path d="M43.9 49.9h8.7l.7 .9-.7 .9h-8.7zM45.8 44.8h6.8l.7 .9-.7 .9h-6.8zM52 58a.57 .57 0 0 1 0 .9M52.1 40.7v.3M52.1 45.4v.7M52.1 46.2l.1 .1M59.7 50.8h2.5M59.7 58.4h2.5M59.7 40.6h2.5M59.7 43.2h2.5M59.7 45.7h2.5M59.7 48.3h2.5"/>
<path d="M59.7 53.3h2.5M59.7 55.9h2.5M87.6 50.8h2.6M87.6 58.4h2.6M87.6 40.6h2.6M87.6 43.2h2.6M87.6 45.7h2.6M87.6 48.3h2.6M87.6 53.3h2.6M87.6 55.9h2.6M96.3 49.9h7l.8 .9-.8 .9h-7zM96.5 42.3h5.1l.8 .9-.8 .9h-5.1z"/>
<path d="M96.5 55h8.9l.7 .9-.7 .9h-8.9zM96.5 57.5h3.7l.8 .9-.8 .9h-3.7zM96.5 47.4h8.6l.8 .9-.8 .8h-8.6zM97.3 52.5h11.5v1.7h-11.5l-.8-.9zM97.3 44.8h8.8l.8 .9-.8 .9h-8.8l-.8-.9zM133.4 57.5h6.8l.8 .9-.8 .9h-6.8l-.8-.9zM134.2 42.3h6l.8 .9-.8 .9h-6l-.7-.9zM134.2 44.8h6l.8 .9-.8 .9h-6l-.7-.9zM134.2 52.5h6l.8 .8-.8 .9h-6l-.7-.9zM134.2 55h6l.8 .9-.8 .9h-6l-.7-.9zM134.2 47.4h6l.8 .9-.8 .8h-6l-.7-.8zM134.2 49.9h6l.8 .9-.8 .9h-6l-.7-.9z"/>
<path d="M140.4 40.2v.9M147.3 50.8h2.6M147.3 58.4h2.6M147.3 40.6h2.6M147.3 43.2h2.6M147.3 45.7h2.6M147.3 48.3h2.6M147.3 53.3h2.6M147.3 55.9h2.6M175.3 50.8h2.5M175.3 58.4h2.5M175.3 40.6h2.5"/>
<path d="M175.3 43.2h2.5M175.3 45.7h2.5M175.3 48.3h2.5M175.3 53.3h2.5M175.3 55.9h2.5M184.1 44.8h8.5l.8 .9-.8 .9h-8.5zM184.1 42.3h8.1l.8 .9-.8 .9h-8.1zM184.1 52.5h7.1l.8 .8-.8 .9h-7.1zM184.9 55h7.3l.7 .9-.7 .9h-7.3l-.8-.9zM184.9 57.5h7.3l.7 .9-.7 .9h-7.3l-.8-.9zM228.6 50.8h2.5M236.2 50.8h2.6"/>
<path d="M236.2 57.2h2.6M236.2 59.7h2.6M236.2 40.6h2.6M236.2 43.2h2.6M236.2 45.7h2.6M236.2 48.3h2.6M236.2 53.3h2.6M264.2 50.8h2.5M264.2 58.4h2.5M264.2 40.6h2.5M264.2 43.2h2.5M264.2 45.7h2.5"/>
<path d="M264.2 48.3h2.5M264.2 53.3h2.5M264.2 55.9h2.5M274.3 58.4v2.6M285 60h2M30.5 63.5v2.5M30.5 71.1v2.6M30.5 78.7v2.6M33 71.1v2.6M33 78.7v2.6M40 60.1h12.6l.7 .9-.7 .8h-12.6l-.8-.8zM41.5 75.3h11.1l.7 .9-.7 .9h-11.1l-.8-.9z"/>
<path d="M44.8 77.9h7.8l.7 .8-.7 .9h-7.8zM44.8 67.7h9v1.8h-9l-.8-.9zM44.9 70.2h8.9v1.8h-8.9l-.8-.9zM46.5 62.6h6.8v1.8h-6.8l-.7-.9zM48.6 72.8h4.7v1.7h-4.7l-.8-.8zM49.2 72.8h3.7M49.8 73.2h-.4v.9M50 74.1l.3-.9 .3 .9M50.9 73.2v.8M51.4 73.2v.8M51.8 60.9l.4 .5M51.8 73.2v.9"/>
<path d="M52 75.8a.63 .63 0 0 1 0 .8M52.1 78.5v.6M52.2 60.5l-.5 .6M52.4 73.2h.5M52.7 73.2v.9M52.8 64l.1 .1M52.8 63.2v.6M59.7 76.2h2.5M59.7 78.7h2.5M59.7 61h2.5M59.7 63.5h2.5M59.7 68.6h2.5"/>
<path d="M59.7 71.1h2.5M59.7 73.7h2.5M87.6 76.2h2.6M87.6 78.7h2.6M87.6 61h2.6M87.6 63.5h2.6M87.6 68.6h2.6M87.6 71.1h2.6M87.6 73.7h2.6M96.5 75.3h8.2l.8 .9-.8 .9h-8.2zM97.3 67.7h6l.7 .9-.7 .9h-6l-.8-.9zM97.3 70.2h6l.7 .9-.7 .9h-6l-.8-.9z"/>
<path d="M97.3 72.8h9.9l.7 .9-.7 .8h-9.9l-.8-.8zM97.3 77.9h12.3v1.7h-12.3l-.8-.9zM133.4 62.6h6.8l.8 .9-.8 .9h-6.8l-.8-.9zM133.4 60.1h6.8l.8 .9-.8 .8h-6.8l-.8-.8zM135.1 77.9h5.9v1.7h-5.9l-.7-.9zM135.1 67.7h5.9v1.8h-5.9l-.7-.9zM135.1 75.3h5.9v1.8h-5.9l-.7-.9zM135.1 72.8h5.9v1.7h-5.9l-.7-.8zM135.1 70.2h5.9v1.8h-5.9l-.7-.9zM139.3 61.4h.5M147.3 76.2h2.6M147.3 78.7h2.6"/>
<path d="M147.3 61h2.6M147.3 63.5h2.6M147.3 68.6h2.6M147.3 71.1h2.6M147.3 73.7h2.6M175.3 77.5h2.5M175.3 61h2.5M175.3 63.5h2.5M175.3 68.6h2.5M175.3 71.1h2.5M182.1 79.1h7.9v1.8h-7.9l-.7-.9zM182.1 76.6h7.9v1.8h-7.9l-.7-.9z"/>
<path d="M184.1 62.6h9.4l.8 .9-.8 .9h-9.4zM206.5 60.7v5.1M206.5 70.9v2.5M206.5 78.5v3M211.6 78.5v2.5M214.1 68.3v2.6M219.2 68.3h3M219.2 73.4h3M236.2 64.8h2.6M236.2 67.3h2.6M236.2 69.9h2.6M236.2 72.4h2.6"/>
<path d="M236.2 74.9h2.6M236.2 77.5h2.6M264.2 62.2h2.5M264.2 64.8h2.5M264.2 76.2h2.5M264.2 78.7h2.5M20.1 85.5h7.1l.7 .9-.7 .8h-7.1l-.8-.8zM20.9 82.9h7v1.8h-7l-.8-.9zM26.6 85.9l.3 .9M27.1 84.3h.4M42.8 88h10.5v1.8h-10.5l-.8-.9zM44.7 95.6h7.9l.7 .9-.7 .9h-7.9l-.8-.9z"/>
<path d="M45.6 80.4h7.7v1.8h-7.7l-.8-.9zM46.1 98.2h6.5l.7 .9-.7 .8h-6.5zM52.3 88.7l.3-.2v.9M52.3 89.4h.5M52.8 80.9v.9M59.7 81.3h2.5M59.7 83.8h2.5M59.7 86.4h2.5M59.7 88.9h2.5M59.7 99.1h2.5M59.7 91.4h2.5M59.7 94h2.5"/>
<path d="M59.7 96.5h2.5M87.6 81.3h2.6M87.6 83.8h2.6M87.6 86.4h2.6M87.6 88.9h2.6M87.6 99.1h2.6M87.6 91.4h2.6M87.6 94h2.6M87.6 96.5h2.6M96.5 98.2h11.8l.8 .9-.8 .8h-11.8zM96.5 82.9h5.2l.8 .9-.8 .9h-5.2zM96.5 80.4h5.2l.8 .9-.8 .9h-5.2z"/>
<path d="M97.3 88h6.8l.8 .9-.8 .9h-6.8l-.8-.9zM97.3 90.6h6.8l.8 .8-.8 .9h-6.8l-.8-.9zM97.3 85.5h4v1.7h-4l-.8-.8zM97.3 95.6h7.2v1.8h-7.2l-.8-.9zM97.3 93.1h6.8l.8 .9-.8 .9h-6.8l-.8-.9zM131.6 95.6h9.4v1.8h-9.4l-.8-.9zM132.6 82.9h7.6l.8 .9-.8 .9h-7.6zM133.4 88h7.6v1.8h-7.6l-.8-.9zM133.6 85.5h7.4v1.7h-7.4l-.8-.8zM134.4 90.6h7.1l.7 .8-.7 .9h-7.1zM135.1 98.2h5.9v1.7h-5.9l-.7-.8zM135.1 80.4h5.9v1.8h-5.9l-.7-.9z"/>
<path d="M139.3 83.4l.5 .9M139.8 83.4l-.5 .9M139.9 88.5l.5 .9v-.9M139.9 85.9l.6 .9M140.5 85.9l-.6 .9M147.3 81.3h2.6M147.3 83.8h2.6M147.3 86.4h2.6M147.3 88.9h2.6M147.3 99.1h2.6M147.3 91.4h2.6M147.3 94h2.6"/>
<path d="M147.3 96.5h2.6M175.3 88.3l-1.3 .6 1.3 .6M175.3 90.8l-1.3 .6 1.3 .7M175.3 88.9h2.5M175.3 99.1h2.5M175.3 91.4h2.5M175.3 80h2.5M182.1 88h7.1v1.8h-7.1l-.7-.9zM182.1 90.6h7.1v1.7h-7.1l-.7-.9zM206.5 83.1v8.1M206.5 93.7v2.6M210.3 98.2h6.5l.7 .9-.7 .8h-6.5l-.8-.8z"/>
<path d="M211.6 83.6v2.5M219.2 81h2.5M226.8 81h2.6M236.2 81.3h2.6M236.2 92.7h2.6M236.2 83.8h2.6M236.2 86.4h2.6M236.2 99.1h2.6M236.2 95.3h2.6M236.2 90.2h2.6M264.2 81.3h2.5M264.2 83.8h2.5"/>
<path d="M264.2 86.4h2.5M264.2 88.9h2.5M264.2 99.1h2.5M264.2 91.4h2.5M10 110h2M44.8 103.3h7.8l.7 .8-.7 .9h-7.8zM45.3 105.8h7.8v1.8h-7.8l-.8-.9zM46.3 100.7h7v1.8h-7l-.8-.9zM52.1 103.9v.6M52.5 101.6l.3 .5M52.5 106.3v.9M52.8 101.2l-.5 .5"/>
<path d="M59.7 101.6h2.5M59.7 104.1h2.5M59.7 106.7h2.5M87.6 101.6h2.6M87.6 104.1h2.6M87.6 106.7h2.6M88.9 119.4h3M96.5 100.7h6.7l.8 .9-.8 .9h-6.7zM97.3 103.3h6l.7 .8-.7 .9h-6l-.8-.9zM97.3 105.8h6l.7 .9-.7 .9h-6l-.8-.9zM135.1 100.7h5.9v1.8h-5.9l-.7-.9zM135.1 105.8h5.9v1.8h-5.9l-.7-.9z"/>
<path d="M135.1 103.3h5.9v1.7h-5.9l-.7-.9zM147.3 101.6h2.6M147.3 104.1h2.6M147.3 106.7h2.6M154.9 119.4v2.5M157.5 119.4h3M175.3 101.6h2.5M175.3 104.1h2.5M176.8 115.6h2.5M182.9 115.6h.1M182.9 115.6h.7M184.7 115.6h3.3"/>
<path d="M185.4 113v2.6M188 115.6h.1M193 104.1v2.6M193 111.8v2.5M193 117.3v2.6M198.1 106.7v3M198.1 111.3v5.5M209.4 102.9h8.7v2.5h-8.7l-1.1-1.3zM210.7 100.3h7.3v2.6h-7.3l-1.2-1.3zM229.9 108v2.5M236.2 101.6h2.6M236.2 104.1h2.6"/>
<path d="M236.2 106.7h2.6M264.2 101.6h2.5M264.2 104.1h2.5M264.2 106.7h2.5M273 106.2v.5M274.3 116.8v3.1M279.4 106.2v.5M285 110h2M84.6 120.4v1.9M84.6 126.1v1.9M88.9 129.5h3M101.6 124.5v2.5"/>
<path d="M105.4 137.2v2.5M120.6 134.6v2.6M120.6 139.7v5.1M130.8 134.6v2.6M130.8 139.7v5.1M141 134.6v2.6M141 139.7v2.5M151.1 134.6v2.6M151.1 139.7v2.5M154.9 127v2.5M157.5 129.5h3M158.7 124.5h3.9"/>
<path d="M161.3 134.6v2.6M161.3 139.7v2.5M170.2 124.5v2.5M171.4 134.6v2.6M171.4 139.7v2.5M181.6 134.6v2.6M181.6 139.7v2.5M191.8 134.6v2.6M191.8 139.7v2.5M201.9 130.8l1-.6-1-.7-1 .7 1 .6v1.3M201.9 132.1h.1M201.9 134.6v2.6"/>
<path d="M201.9 139.7v2.5M209.5 128.3v2.5M214.6 134.6h2.6M222.2 134.6h2.6M274.3 121.4v5.6M10 160h2M107.9 142.2h5.1M113 154.9v2.6M120.6 147.3v2.6M120.6 152.4v2.5M130.8 147.3v2.6M130.8 152.4v2.5"/>
<path d="M141 147.3v2.6M141 152.4v2.5M151.1 147.3v2.6M151.1 152.4v2.5M161.3 147.3v2.6M161.3 152.4v2.5M171.4 147.3v2.6M171.4 152.4v2.5M181.6 147.3v2.6M181.6 152.4v2.5M191.8 147.3v2.6M191.8 152.4v2.5"/>
<path d="M201.9 147.3v2.6M201.9 152.4v2.5M227.3 147.3v3.1M227.3 151.9v3M232.4 152.4v2.5M234.9 142.2h2.6M242.6 142.2h2.5M247.6 147.3v2.6M285 160h2M21.1 165.1l1-.6-1-.7-1 .7 1 .6v1.3M21.1 166.4h.1M28.7 163.8v2.6"/>
<path d="M28.7 179.1v2.5M38.9 171.5v3M38.9 176v3.1M41.4 168.9h2.5M49 174v2.5M49 179.1v2.5M54.1 168.9h2.5M61.7 165.1l1-.6-1-.7-1 .7 1 .6v1.3M61.7 166.4h.1M64.3 168.9h2.5M177 166h108v32h-108zM227.3 160v2.6"/>
<path d="M21.1 189.2v2.6M60 198v2M110 198v2M160 198v2M177 194.5h108M177 191.5h108M177 187.5h108M177 181.5h108M182.4 186.3h.1l-.1 .1M182.4 185.5h.1l-.1 .1M184.6 183.6v.1M184.6 182.8v.1"/>
<path d="M196.6 182.2h1l-.7 1.5M197 191.5v3M209.6 185.4l.4 .1M210 198v2M210 186.3l-.4 .1M210.6 185.5a.37 .37 0 0 1 .7 .1v.8M210.6 184.9v1.5M217.6 193.2h1.2M219.6 192.4a.36 .36 0 0 1 .6 .2 .77 .77 0 0 1-.4 1.2 1 1 0 0 1-.2-1.4zM220.8 192.3h1l-.7 1.5M260 198v2M261 191.5v6.5"/>
<path d="M270.3 195.1h.7M270.4 195.7h.4l.3 .3v.3l-.2 .2-.5 .1"/>
</g>
<g fill="#840000" stroke="#840000" stroke-width=".15">
<path d="M277.4 105.7h4v.5h-4z"/>
<path d="M277.4 104.6h4v.6h-4z"/>
<path d="M272.3 120.9h4.1v.5h-4.1z"/>
<path d="M272.3 119.9h4.1v.5h-4.1z"/>
<path d="M267.2 120.9h4.1v.5h-4.1z"/>
<path d="M267.2 119.9h4.1v.5h-4.1z"/>
<path d="M245.6 151.4h4.1v.5h-4.1z"/>
<path d="M245.6 150.4h4.1v.5h-4.1z"/>
<path d="M237.5 141.4h5.1v1.7h-5.1z"/>
<path d="M199.9 138.7h4.1v.5h-4.1z"/>
<path d="M199.9 137.7h4.1v.5h-4.1z"/>
<path d="M205.6 65.8h1.8v5.1h-1.8z"/>
<path d="M223.3 66.3h.5v4.1h-.5z"/>
<path d="M222.2 66.3h.6v4.1h-.6z"/>
<path d="M179.6 138.7h4v.5h-4z"/>
<path d="M179.6 137.7h4v.5h-4z"/>
<path d="M189.7 138.7h4.1v.5h-4.1z"/>
<path d="M189.7 137.7h4.1v.5h-4.1z"/>
<path d="M226.6 32h4v.5h-4z"/>
<path d="M226.6 31h4v.5h-4z"/>
<path d="M179.6 151.4h4v.5h-4z"/>
<path d="M179.6 150.4h4v.5h-4z"/>
<path d="M197.1 27.1h3.3v.8h-3.3z"/>
<path d="M169.4 151.4h4.1v.5h-4.1z"/>
<path d="M169.4 150.4h4.1v.5h-4.1z"/>
<path d="M93 117.3h.5v4.1h-.5z"/>
<path d="M91.9 117.3h.6v4.1h-.6z"/>
<path d="M204.5 82.6h4v.5h-4z"/>
<path d="M204.5 81.5h4v.5h-4z"/>
<path d="M119 138.8h3.3v.9h-3.3z"/>
<path d="M118.6 151.4h4.1v.5h-4.1z"/>
<path d="M118.6 150.4h4.1v.5h-4.1z"/>
<path d="M138.9 151.4h4.1v.5h-4.1z"/>
<path d="M138.9 150.4h4.1v.5h-4.1z"/>
<path d="M128.8 151.4h4v.5h-4z"/>
<path d="M128.8 150.4h4v.5h-4z"/>
<path d="M128.8 138.7h4v.5h-4z"/>
<path d="M128.8 137.7h4v.5h-4z"/>
<path d="M138.9 138.7h4.1v.5h-4.1z"/>
<path d="M138.9 137.7h4.1v.5h-4.1z"/>
<path d="M159.3 151.4h4v.5h-4z"/>
<path d="M159.3 150.4h4v.5h-4z"/>
<path d="M149.1 138.7h4.1v.5h-4.1z"/>
<path d="M149.1 137.7h4.1v.5h-4.1z"/>
<path d="M159.3 138.7h4v.5h-4z"/>
<path d="M159.3 137.7h4v.5h-4z"/>
<path d="M160.5 127.5h.5v4.1h-.5z"/>
<path d="M161.5 127.5h.6v4.1h-.6z"/>
<path d="M160.5 117.3h.5v4.1h-.5z"/>
<path d="M161.5 117.3h.6v4.1h-.6z"/>
<path d="M209.5 82.6h4.1v.5h-4.1z"/>
<path d="M209.5 81.5h4.1v.5h-4.1z"/>
<path d="M149.1 151.4h4.1v.5h-4.1z"/>
<path d="M149.1 150.4h4.1v.5h-4.1z"/>
<path d="M271 104.6h4.1v.6h-4.1z"/>
<path d="M271 105.7h4.1v.5h-4.1z"/>
<path d="M26.7 177h4v.5h-4z"/>
<path d="M26.7 178.1h4v.5h-4z"/>
<path d="M199.9 151.4h4.1v.5h-4.1z"/>
<path d="M199.9 150.4h4.1v.5h-4.1z"/>
<path d="M217.2 133.7h5v1.8h-5z"/>
<path d="M186.9 115.6h.6a.51 .51 0 0 1-.6 .5z"/>
<path d="M184.4 115.6h.5a.51 .51 0 0 1-.5 .5z"/>
<path d="M186.9 115.1a.51 .51 0 0 1 .6 .5h-.6z"/>
<path d="M184.4 115.1a.51 .51 0 0 1 .5 .5h-.5z"/>
<path d="M186.1 115.2l.3-.1v1a.51 .51 0 0 1-.4-.3 .51 .51 0 0 1 .1-.6z"/>
<path d="M183.6 115.2l.3-.1v1a.51 .51 0 0 1-.5-.3 .51 .51 0 0 1 .2-.6z"/>
<path d="M196.1 109.7h4.1v.5h-4.1z"/>
<path d="M196.1 110.7h4.1v.6h-4.1z"/>
<path d="M194.3 14l2.5 1.2-2.5 1.3z"/>
<path d="M272.3 32h4.1v.5h-4.1z"/>
<path d="M272.3 31h4.1v.5h-4.1z"/>
<path d="M277.4 32h4v.5h-4z"/>
<path d="M277.4 31h4v.5h-4z"/>
<path d="M93 127.5h.5v4.1h-.5z"/>
<path d="M91.9 127.5h.6v4.1h-.6z"/>
<path d="M230.4 150.4h4v.5h-4z"/>
<path d="M230.4 151.4h4v.5h-4z"/>
<path d="M225.3 150.4h4.1v.5h-4.1z"/>
<path d="M225.3 151.4h4.1v.5h-4.1z"/>
<path d="M223.3 71.4h.5v4h-.5z"/>
<path d="M222.2 71.4h.6v4h-.6z"/>
<path d="M169.4 138.7h4.1v.5h-4.1z"/>
<path d="M169.4 137.7h4.1v.5h-4.1z"/>
<path d="M36.8 175.5h4.1v.5h-4.1z"/>
<path d="M36.8 174.5h4.1v.5h-4.1z"/>
<path d="M189.7 151.4h4.1v.5h-4.1z"/>
<path d="M189.7 150.4h4.1v.5h-4.1z"/>
</g>
<g fill="none" stroke="#840000" stroke-width=".25">
<path d="M182.8 14l-2 1.2 2 1.3M196.8 14v2.5h-.6v-.2M197.5 14v.2M203.8 19.4h5.1v1.8h-5.1zM197.5 33h2.5l-1.2 1.3zM200.3 25.4h-3.1v.9h3.1M227.3 38.1h2.6l-1.3 1.3zM273 38.1h2.6l-1.3 1.3zM273 24.8l1.3-1.9 1.3 1.9M230.5 49.5l-1.9 1.3 1.9 1.3M29.2 65.4l1.3-1.9 1.2 1.9M29.6 73.7h1.8v5h-1.8z"/>
<path d="M32.1 73.7h1.8v5h-1.8zM205.2 62.6l1.3-1.9 1.3 1.9M212.9 70.9h2.5l-1.3 1.2zM273 61h2.6l-1.3 1.2zM205.2 96.3h2.6l-1.3 1.2zM206.5 87.4v2.5M221.7 80.1h5.1v1.8h-5.1zM178.7 114.3l-1.9 1.3 1.9 1.2M191.8 119.9h2.5l-1.3 1.3zM192.2 106.7h1.7v5.1h-1.7zM196.8 116.8h2.6l-1.3 1.3zM228.6 110.5h2.5l-1.2 1.3z"/>
<path d="M271.8 111.8h2.5l-1.3 1.2zM278.1 111.8h2.6l-1.3 1.2zM100.3 127h2.6l-1.3 1.3zM104.1 139.1l1.3-1.9 1.3 1.9M119.1 137.2h3.1v.8h-3.1zM156.2 121.3h2.5v6.3h-2.5M168.9 127h2.5l-1.2 1.3zM209.5 128.3l-1.2 1.9M273 127h2.6l-1.3 1.3zM277.7 124h2M277.7 139.2h2M277.7 131.6h2"/>
<path d="M280.9 120.8v1.9M280.9 125.2v1.9M280.9 128.4v1.9M280.9 132.8v1.9M280.9 136v1.9M282.2 124h1.9M282.2 139.2h1.9M282.2 131.6h1.9M111.8 157.5h2.5l-1.3 1.3zM119.4 144.8h2.5l-1.3 1.3zM129.5 144.8h2.6l-1.3 1.3zM277.7 153.9h2"/>
<path d="M277.7 146.8h2M280.9 140.5v1.9M280.9 143.6v1.9M280.9 148.1v1.9M280.9 150.7v2M280.9 155.2v1.9M280.9 157.9v1.9M282.2 153.9h1.9M282.2 146.8h1.9M27.4 165.7l1.3-1.9 1.3 1.9M43.9 167h10.2v7h-10.2zM64.9 167.6l1.9 1.3-1.9 1.3"/>
<path d="M226.1 162.6h2.5l-1.3 1.2zM277.7 161h2M280.9 162.3v1.9M282.2 161h1.9M19.8 191.8h2.6l-1.3 1.2zM47.8 181.6h2.5l-1.3 1.3z"/>
<circle cx="280.9" cy="131.6" r="2.54"/>
<circle cx="280.9" cy="139.2" r="2.54"/>
<circle cx="280.9" cy="124" r="2.54"/>
<circle cx="280.9" cy="146.8" r="2.54"/>
<circle cx="280.9" cy="153.9" r="2.54"/>
<circle cx="280.9" cy="161" r="2.54"/>
</g>
<g fill="#840000" stroke="#840000" stroke-width=".25">
<path d="M280.3 153.9a.62 .62 0 0 0 .6-.6 .62 .62 0 0 0 .7 .6 .62 .62 0 0 0-.7 .7z"/>
<path d="M280.9 123.3a.62 .62 0 0 0 .7 .7 .62 .62 0 0 0-.7 .6l-.6-.6a.62 .62 0 0 0 .6-.7z"/>
<path d="M280.9 146.2a.62 .62 0 0 0 .7 .6 .62 .62 0 0 0-.7 .6l-.6-.6a.62 .62 0 0 0 .6-.6z"/>
<path d="M280.3 161a.62 .62 0 0 0 .6-.6 .62 .62 0 0 0 .7 .6 .62 .62 0 0 0-.7 .7z"/>
<path d="M280.3 139.2a.62 .62 0 0 0 .6-.6 .62 .62 0 0 0 .7 .6 .62 .62 0 0 0-.7 .6z"/>
<path d="M280.3 131.6a.62 .62 0 0 0 .6-.7 .62 .62 0 0 0 .7 .7 .62 .62 0 0 0-.7 .6z"/>
</g>
<g fill="none" stroke="#006464" stroke-width=".15">
<path d="M180 12.2h1l-.5 .7M180.9 13.1l.1 .2-.1 .5M210.4 26.9h.6l-.6 .9h.6M211.6 26.9v.7l-.3 .2M86.2 53.9h.7M173.8 53.9h.7M251.8 56.5h.5a.34 .34 0 0 1 0 .5l-.7 .7h.8M251.9 59h.2l.3 .2-.1 .2-.2 .2M251.9 59.6h.2M252.1 59.6l.3 .2v.2l-.3 .3h-.2M262.7 51.4h.7M263.3 57.9a1.06 1.06 0 0 1 0 1"/>
<path d="M27.8 62.7h.9l-.5 .7M28.6 63.5l.1 .2-.1 .6M86 60.5v.9M86.2 63v.7l-.1 .2h-.2M86.5 63h.5M86.8 63v.9M86.9 60.5v.9l-.5-.9v.9M173.9 70.4h.7M174.3 70.4v1.3M174.4 67.9v1.3l-.7-1.3v1.3M262.7 61.5h.6M263.2 62l.2 .3v.3l-.2 .2"/>
<path d="M263.2 64.1l.1 .1a1.03 1.03 0 0 1-.1 1.1M263.3 75.6a.34 .34 0 0 1 0 .5l-.7 .7h.8M263.3 78.1v.1a1.06 1.06 0 0 1-.1 1M263.4 64.6l-.2 .3M263.4 78.6l-.1 .2M66.7 97.1h.8M86.2 97.1h.7M154.2 97.1h.7M262.6 83.1h.9l-.6 1.3M262.6 90.8h.8l-.4 .4M262.7 81.4h.8M262.7 86.9h.7"/>
<path d="M262.9 85.9l.1-.2v1.2M263.3 88.3a1.06 1.06 0 0 1-.1 1.1M263.3 91.3l.1 .2v.3l-.1 .2M263.4 88.8l-.1 .1M81.2 110.2l.2-.1h.3l.4 .4v.5l-.2 .3-.2 .1h-.3l-.2-.1M81.9 109.3h-.3l-.3 .2M168.8 111.3l.2 .1h.3l.2-.1M168.8 110.2l.2-.1h.3l.2 .1 .2 .3v.5M169.5 109.3h-.3l-.3 .2M257.7 110.2l.2-.1h.3l.4 .4v.5l-.2 .3-.2 .1h-.3l-.2-.1M258.4 109.3h-.3l-.3 .2M262.6 103.5h.8l-.4 .4"/>
<path d="M262.6 107.3h.8M262.7 102.2h.7M262.9 101.1l.1-.2v1.3M263.3 104.1v.5M263.3 106.1v.4M78.8 126.1l.5 .9 .4-.9v1.2M80.2 126.1l.8 1.2M81 126.1l-.8 1.2M107.8 134.8h.9l-.5 .7M108.6 135.6l.1 .2-.1 .6M150.6 124.6l-.1 .9 .2-.2M151.1 125.3l.3 .3-.1 .6-.2 .2h-.4l-.2-.2"/>
<path d="M225.5 137.1h.5l.1-.2v-.2l-.2-.1h-.4v1M225.8 137.1l.3 .5M255.2 139.8a.62 .62 0 0 1 0 1M52.4 164.4h.8l-.5 .5a.34 .34 0 0 1 .5 .2v.3l-.2 .2-.4 .1M53.6 164.4h.8l-.4 .5a.34 .34 0 0 1 .4 .2v.3l-.1 .2-.5 .1-.2-.1M71.7 166.5h.9l-.5 .7M72.6 167.4v.2v.5"/>
</g>
<path d="M82 123.1h5.1v2.2h-5.1z" fill="none" stroke="#840000" stroke-width=".3"/>
<path d="M83.3 126.1h2.6M83.3 122.3h2.6" fill="none" stroke="#840000" stroke-width=".51"/>
<g fill="#ffffc2" stroke="#ffffc2" stroke-width=".13">
<path d="M43.9 167h10.2v7h-10.2z"/>
<path d="M238.8 22.9h25.4v86.3h-25.4z"/>
<path d="M149.9 22.9h25.4v86.3h-25.4z"/>
<path d="M62.2 22.9h25.4v86.3h-25.4z"/>
</g>
<path d="M62.2 22.9h25.4v86.3h-25.4zM149.9 22.9h25.4v86.3h-25.4zM238.8 22.9h25.4v86.3h-25.4z" fill="none" stroke="#840000" stroke-width=".4"/>
<g fill="none" stroke="#a90000" stroke-width=".15">
<path d="M61.1 25h.5M90 39.5v.3M149.2 27.6h.5M149.6 24.3v.6M177.1 32.7h.5M177.1 34.9h.6M177.6 29.4v.5M177.6 37.3v.4M177.6 39.8v.4M266 25h.5M266.5 26.9v.5M61.1 40.3h.5"/>
<path d="M61.5 44.5h.6l-.4 .9M61.5 58.1h.6M61.6 55.5h.5M62 47.1v.2M62 47.5v.3M62 49.6v.6M62 52.3v.5M62 57.3v.2M62 59.8v.2M62.1 49.9l-.1 .1M89.5 41.9h.5l-.3 .4M89.5 40.3h.5"/>
<path d="M89.5 55.5h.5M89.5 45.1h.5M89.5 53h.5M90 42.4v.3M90 47.4v.4M90 49.7v.6M90 54.7v.3M177.1 41.9h.6l-.4 .9M177.1 47h.5l-.3 .3M177.1 57.2h.6l-.4 .9M177.1 50.1h.6M177.6 44.6v.2"/>
<path d="M177.6 44.9v.4M177.6 47.4v.4M177.6 52.5v.4M177.6 55.1v.3M177.6 59.8v.2M237.7 45.4h.5M238 56.8h.6M238.5 56v.3M238.5 58.5v.2M238.5 58.9v.3M265.6 50.4h.5M266.5 57.3v.6"/>
<path d="M61.5 75.8h.6M61.5 77.5h.6l-.3 .3M62 60.2v.3M62 62.3v.6M62 75v.3M62 77.9v.4M62.1 62.6l-.1 .1M89.1 63.1h.5M89.5 67.3h.5l-.3 .4M89.5 77.5h.5l-.3 .9M89.5 70.5h.5M90 67.8v.3"/>
<path d="M90 72.8v.4M90 75.4v.4M148.8 75.8h.5M176.7 68.2h.5M177.1 76.2h.5l-.3 .4M177.1 79.4h.6M177.1 63.1h.5M177.6 76.6v.4M177.6 60.2v.3M238 63.5h.6l-.3 .4M238 72h.6M238.5 63.9v.4"/>
<path d="M238.5 66.5v.4M238.5 69v.4M238.5 71.2v.3M238.5 73.8v.6M238.5 76.6v.4M266 75.8h.5M266.5 61.4v.4M266.5 63.6v.6M266.5 75v.3M266.5 77.6v.6M266.5 63.9v.1M266.5 77.9v.1"/>
<path d="M61.6 80.6h.5M62 83v.4M62 85.5v.4M62 87.7v.2M62 88.1v.4M62 90.3v.6M62.1 90.6l-.1 .1M89.1 93.6h.5M90 80.1v.2M90 80.5v.3M90 82.7v.5M90 85.3v.5"/>
<path d="M90 82.9v.1M177.1 90.2h.6l-.4 .9M177.6 88.1v.4M238.5 91.9v.4M238.5 94.4v.4M266 82.6h.6l-.4 .9M266 90.2h.5l-.3 .3M266 80.6h.6M266 86h.5M266.5 87.7v.6M266.5 90.6v.4M266.5 88v.1"/>
<path d="M148.8 103.8h.5M177.1 100.3h.6l-.4 .9M177.1 103.5h.6M266 102.9h.5l-.3 .3M266 106.3h.5M266 101.2h.5M266.5 103.3v.4M266.5 105.5v.3"/>
</g>
<path d="M152.4 126.7h5.1M152.4 123.1h5.1v2.6h-5.1zM152.4 122.1h5.1" fill="none" stroke="#840000" stroke-width=".41"/>
<path d="M24.3 17.1v.1M24.3 17.6v1.2M24.3 17.1h-.1l.1 .1M24.8 17.6h.5M25 17.1v1.5v.1l.3 .1" fill="none" stroke="#c2c2c2" stroke-width=".15"/>
<g fill="none" stroke="#840084" stroke-width=".15">
<path d="M54.4 54.9h.7l.5 .5h1.3l.8-.5h.5M54.4 52.1h.7l.5-.8h1.3l.8 .8h.5M54.4 52.3h.7l.5 .5h1.3l.8-.5h.5M54.4 54.6h.7l.5-.8h1.3l.8 .8h.5M84.8 131.9h.4M84.8 131.1h.3l.2 .3-.6 .1M85.7 131.8v.1M85.7 131.1v.2M94.6 123.7h.2l.2 .2-.2 .3M94.6 124.2h.2M94.8 124.2l.1 .1 .1 .4-.2 .2h-.2M109.5 122.2h.4"/>
<path d="M109.7 121.8v1.1v.1h.2M249.6 120.3l.2 .3-.5 .1M249.7 121.1h-.1M251.8 137.4v1.3M251.8 138.2l.1 .1M251.9 137.4l-.1 .1M259.1 137.4h.4M259.3 137v1.1l.1 .2M261.5 137l.4 1.3 .3-1.3"/>
</g>
<g fill="none" stroke="#009600" stroke-width=".15">
<path d="M183.4 15.2h9.6M198.1 15.2h15.9v5.1h-2.5M214 17.8h4.4v7.6h17.8M53.3 38.1h6.4M53.3 33h6.4M53.3 30.5h6.4M53.3 35.6h6.4M53.3 25.4h6.4M53.3 27.9h6.4M90.2 38.1h6.3M90.2 33h6.3M90.2 30.5h6.3"/>
<path d="M90.2 35.6h6.3M90.2 25.4h6.3M90.2 27.9h6.3M141 38.1h6.3M141 33h6.3M141 30.5h6.3M141 35.6h6.3M141 25.4h6.3M141 27.9h6.3M177.8 38.1h6.3M177.8 33h6.3M177.8 30.5h6.3"/>
<path d="M177.8 35.6h6.3M177.8 25.4h6.3M177.8 27.9h6.3M196.6 20.3h4.7M198.8 20.3v2.6M228.6 25.4v2.5M233.7 38.1h2.5M233.7 33h2.5M233.7 35.6h2.5M236.2 30.5h-2.5v47h2.5M266.7 25.4h2.5v2.5M266.7 33h2.5v58.4h-2.5"/>
<path d="M266.7 38.1h2.5M266.7 35.6h2.5M266.7 27.9h12.7M274.3 25.4v2.5M274.3 35.6h5.1M53.3 55.9h6.4M53.3 58.4h6.4M53.3 50.8h6.4M53.3 53.3h6.4M53.3 48.3h6.4M53.3 45.7h6.4M53.3 43.2h6.4"/>
<path d="M53.3 40.6h6.4M90.2 55.9h6.3M90.2 58.4h6.3M90.2 50.8h6.1M90.2 53.3h6.3M90.2 48.3h6.3M90.2 45.7h6.3M90.2 43.2h6.3M90.2 40.6h6.3M141 55.9h6.3M141 58.4h6.3M141 50.8h6.3"/>
<path d="M141 53.3h6.3M141 48.3h6.3M141 45.7h6.3M141 43.2h6.3M141 40.6h6.3M177.8 55.9h6.3M177.8 58.4h6.3M177.8 53.3h6.3M177.8 45.7h6.3M177.8 43.2h6.3M177.8 40.6h6.3M226.1 57.2h10.1"/>
<path d="M229.9 57.2v2.5h6.3M231.1 50.8h5.1M233.7 53.3h2.5M233.7 48.3h2.5M233.7 45.7h2.5M233.7 43.2h2.5M233.7 40.6h2.5M266.7 55.9h7.6v2.5M266.7 58.4h2.5M266.7 50.8h2.5M266.7 53.3h2.5M266.7 48.3h2.5"/>
<path d="M266.7 45.7h2.5M266.7 43.2h2.5M266.7 40.6h2.5M30.5 68.6h2.5v2.5M30.5 66v5.1M53.3 63.5h6.4M53.3 61h6.4M53.3 76.2h6.4M53.3 78.7h6.4M53.3 73.7h6.4M53.8 68.6h5.9M53.8 71.1h5.9"/>
<path d="M90.2 63.5h6.3M90.2 61h6.3M90.2 68.6h6.3M90.2 71.1h6.3M90.2 76.2h6.3M90.2 78.7h6.3M90.2 73.7h6.3M141 63.5h6.3M141 61h6.3M141 68.6h6.3M141 71.1h6.3M141 76.2h6.3"/>
<path d="M141 78.7h6.3M141 73.7h6.3M177.8 63.5h6.3M177.8 68.6h6.3M177.8 71.1h6.3M177.8 77.5h3.6M204.2 73.4v2.5h12.5v7.7M206.5 73.4v5.1M211.6 75.9v2.6M214.1 68.3h5.1v5.1M226.8 68.3h2.6v12.7M226.8 73.4h2.6"/>
<path d="M233.7 64.8h2.5M233.7 74.9h2.5M233.7 72.4h2.5M233.7 69.9h2.5M233.7 67.3h2.5M266.7 76.2h2.5M266.7 78.7h2.5M266.7 62.2h2.5M266.7 64.8h2.5M27.9 83.8h31.8M27.9 86.4h31.8M30.5 81.3v2.5"/>
<path d="M33 81.3v5.1M53.3 81.3h6.4M53.3 99.1h6.4M53.3 88.9h6.4M53.3 96.5h6.4M90.2 81.3h6.3M90.2 83.8h6.3M90.2 99.1h6.3M90.2 91.4h6.3M90.2 86.4h6.3M90.2 88.9h6.3M90.2 96.5h6.3"/>
<path d="M90.2 94h6.3M141 81.3h6.3M141 83.8h6.3M141 99.1h6.3M141 86.4h6.3M141 88.9h6.3M141 96.5h6.3M142.2 91.4h5.1M177.8 80h3.6M177.8 99.1h31.7M177.8 91.4h3.6M177.8 88.9h3.6"/>
<path d="M198.1 99.1v7.6M206.5 86.1h27.2v28.2M206.5 91.2v2.5M216.7 81h2.5M217.2 83.8h19M221 99.1h15.2M229.6 81v.3h6.6M233.7 86.4h2.5M233.7 90.2h2.5M233.7 92.7h2.5M233.7 95.3h2.5M266.7 99.1h2.5v17.7"/>
<path d="M266.7 81.3h2.5M266.7 83.8h2.5M266.7 86.4h2.5M266.7 88.9h2.5M279.4 97.8v3.8h-12.7M53.1 106.7h6.6M53.3 101.6h6.4M53.3 104.1h6.4M68.6 119.4h20.3M84.6 119.4v1M90.2 101.6h6.3M90.2 104.1h6.3"/>
<path d="M90.2 106.7h6.3M96.5 119.4h2.6v10.1h-2.6M137.2 119.4h20.3M141 101.6h6.3M141 104.1h6.3M141 106.7h6.3M165.1 119.4h2.5v10.1h-2.5M177.8 101.6h31.7M177.8 104.1h30.5M179.3 115.6h3.6M185.4 104.1v8.9M188 115.6h5"/>
<path d="M193 101.6v2.5M193 114.3v3M221 114.3h53.3v2.5M221 101.6h15.2M233.7 104.1h2.5M236.2 106.7h-6.3v1.3M266.7 104.1h2.5M266.7 106.7h2.5M68.6 129.5h20.3M84.6 128v1.5M99.1 124.5h2.5M105.4 139.7v2.5h2.5"/>
<path d="M137.2 129.5h20.3M162.6 124.5h7.6M201.9 132.1v2.5M209.5 130.8v3.8M214.6 134.6h-99v12.7h86.3M224.8 134.6h35.5M227.3 134.6v12.7M269.2 124.5h5.1M113 154.9h88.9M113 142.2h2.6M130.8 142.2h71.1M227.3 154.9v5.1"/>
<path d="M232.4 144.8h27.9M232.4 154.9v2.6M234.9 142.2h-2.5v5.1M245.1 142.2h15.2M247.6 142.2v5.1M247.6 154.9v2.6h-20.3M21.1 166.4v2.5h20.3M28.7 166.4v7.6M38.9 168.9v2.6M49 176.5v2.6h-10.1M56.6 168.9h7.7M61.7 166.4v2.5"/>
<path d="M21.1 189.2h10.1M28.7 181.6v7.6"/>
</g>
<path d="M177.2 47.7l1.2 1.2M177.2 50.2l1.2 1.2M178.4 47.7l-1.2 1.2M178.4 50.2l-1.2 1.2M59.1 93.4l1.2 1.2M59.1 90.8l1.2 1.2M60.3 93.4l-1.2 1.2M60.3 90.8l-1.2 1.2M146.7 93.4l1.2 1.2M147.9 93.4l-1.2 1.2" fill="none" stroke="#000084" stroke-width=".15"/>
<g fill="#009600" stroke="#009600" stroke-width=".15">
<circle cx="229.4" cy="81" r=".46"/>
<circle cx="233.7" cy="86.4" r=".46"/>
<circle cx="233.7" cy="90.2" r=".46"/>
<circle cx="211.6" cy="75.9" r=".46"/>
<circle cx="206.5" cy="75.9" r=".46"/>
<circle cx="219.2" cy="68.3" r=".46"/>
<circle cx="229.4" cy="73.4" r=".46"/>
<circle cx="233.7" cy="95.3" r=".46"/>
<circle cx="233.7" cy="92.7" r=".46"/>
<circle cx="209.5" cy="134.6" r=".46"/>
<circle cx="227.3" cy="157.5" r=".46"/>
<circle cx="233.7" cy="104.1" r=".46"/>
<circle cx="233.7" cy="114.3" r=".46"/>
<circle cx="247.6" cy="142.2" r=".46"/>
<circle cx="232.4" cy="157.5" r=".46"/>
<circle cx="227.3" cy="134.6" r=".46"/>
<circle cx="232.4" cy="144.8" r=".46"/>
<circle cx="269.2" cy="104.1" r=".46"/>
<circle cx="269.2" cy="86.4" r=".46"/>
<circle cx="269.2" cy="88.9" r=".46"/>
<circle cx="279.4" cy="101.6" r=".46"/>
<circle cx="269.2" cy="114.3" r=".46"/>
<circle cx="269.2" cy="106.7" r=".46"/>
<circle cx="274.3" cy="124.5" r=".46"/>
<circle cx="151.1" cy="142.2" r=".46"/>
<circle cx="151.1" cy="147.3" r=".46"/>
<circle cx="151.1" cy="154.9" r=".46"/>
<circle cx="154.9" cy="119.4" r=".46"/>
<circle cx="161.3" cy="142.2" r=".46"/>
<circle cx="161.3" cy="134.6" r=".46"/>
<circle cx="154.9" cy="129.5" r=".46"/>
<circle cx="161.3" cy="147.3" r=".46"/>
<circle cx="161.3" cy="154.9" r=".46"/>
<circle cx="167.6" cy="124.5" r=".46"/>
<circle cx="141" cy="134.6" r=".46"/>
<circle cx="141" cy="142.2" r=".46"/>
<circle cx="130.8" cy="134.6" r=".46"/>
<circle cx="130.8" cy="142.2" r=".46"/>
<circle cx="130.8" cy="154.9" r=".46"/>
<circle cx="130.8" cy="147.3" r=".46"/>
<circle cx="141" cy="147.3" r=".46"/>
<circle cx="141" cy="154.9" r=".46"/>
<circle cx="120.6" cy="147.3" r=".46"/>
<circle cx="151.1" cy="134.6" r=".46"/>
<circle cx="181.6" cy="134.6" r=".46"/>
<circle cx="185.4" cy="104.1" r=".46"/>
<circle cx="193" cy="104.1" r=".46"/>
<circle cx="193" cy="115.6" r=".46"/>
<circle cx="193" cy="101.6" r=".46"/>
<circle cx="201.9" cy="134.6" r=".46"/>
<circle cx="191.8" cy="134.6" r=".46"/>
<circle cx="181.6" cy="142.2" r=".46"/>
<circle cx="191.8" cy="142.2" r=".46"/>
<circle cx="181.6" cy="147.3" r=".46"/>
<circle cx="191.8" cy="154.9" r=".46"/>
<circle cx="191.8" cy="147.3" r=".46"/>
<circle cx="181.6" cy="154.9" r=".46"/>
<circle cx="171.4" cy="147.3" r=".46"/>
<circle cx="171.4" cy="154.9" r=".46"/>
<circle cx="171.4" cy="142.2" r=".46"/>
<circle cx="171.4" cy="134.6" r=".46"/>
<circle cx="61.7" cy="168.9" r=".46"/>
<circle cx="84.6" cy="129.5" r=".46"/>
<circle cx="28.7" cy="189.2" r=".46"/>
<circle cx="28.7" cy="168.9" r=".46"/>
<circle cx="38.9" cy="168.9" r=".46"/>
<circle cx="49" cy="179.1" r=".46"/>
<circle cx="84.6" cy="119.4" r=".46"/>
<circle cx="30.5" cy="68.6" r=".46"/>
<circle cx="33" cy="86.4" r=".46"/>
<circle cx="30.5" cy="83.8" r=".46"/>
<circle cx="120.6" cy="154.9" r=".46"/>
<circle cx="115.6" cy="142.2" r=".46"/>
<circle cx="99.1" cy="124.5" r=".46"/>
<circle cx="120.6" cy="134.6" r=".46"/>
<circle cx="269.2" cy="48.3" r=".46"/>
<circle cx="269.2" cy="50.8" r=".46"/>
<circle cx="269.2" cy="27.9" r=".46"/>
<circle cx="274.3" cy="27.9" r=".46"/>
<circle cx="269.2" cy="53.3" r=".46"/>
<circle cx="269.2" cy="38.1" r=".46"/>
<circle cx="269.2" cy="40.6" r=".46"/>
<circle cx="269.2" cy="45.7" r=".46"/>
<circle cx="269.2" cy="43.2" r=".46"/>
<circle cx="269.2" cy="35.6" r=".46"/>
<circle cx="274.3" cy="35.6" r=".46"/>
<circle cx="233.7" cy="74.9" r=".46"/>
<circle cx="216.7" cy="81" r=".46"/>
<circle cx="233.7" cy="69.9" r=".46"/>
<circle cx="211.6" cy="86.1" r=".46"/>
<circle cx="206.5" cy="86.1" r=".46"/>
<circle cx="198.1" cy="99.1" r=".46"/>
<circle cx="214" cy="17.8" r=".46"/>
<circle cx="233.7" cy="38.1" r=".46"/>
<circle cx="233.7" cy="40.6" r=".46"/>
<circle cx="228.6" cy="25.4" r=".46"/>
<circle cx="233.7" cy="33" r=".46"/>
<circle cx="233.7" cy="35.6" r=".46"/>
<circle cx="233.7" cy="43.2" r=".46"/>
<circle cx="269.2" cy="58.4" r=".46"/>
<circle cx="269.2" cy="64.8" r=".46"/>
<circle cx="269.2" cy="78.7" r=".46"/>
<circle cx="269.2" cy="76.2" r=".46"/>
<circle cx="269.2" cy="83.8" r=".46"/>
<circle cx="269.2" cy="81.3" r=".46"/>
<circle cx="269.2" cy="55.9" r=".46"/>
<circle cx="269.2" cy="62.2" r=".46"/>
<circle cx="233.7" cy="50.8" r=".46"/>
<circle cx="233.7" cy="53.3" r=".46"/>
<circle cx="198.8" cy="20.3" r=".46"/>
<circle cx="233.7" cy="64.8" r=".46"/>
<circle cx="233.7" cy="67.3" r=".46"/>
<circle cx="233.7" cy="72.4" r=".46"/>
<circle cx="233.7" cy="45.7" r=".46"/>
<circle cx="233.7" cy="48.3" r=".46"/>
</g>
<use href="#words"/>
</svg>
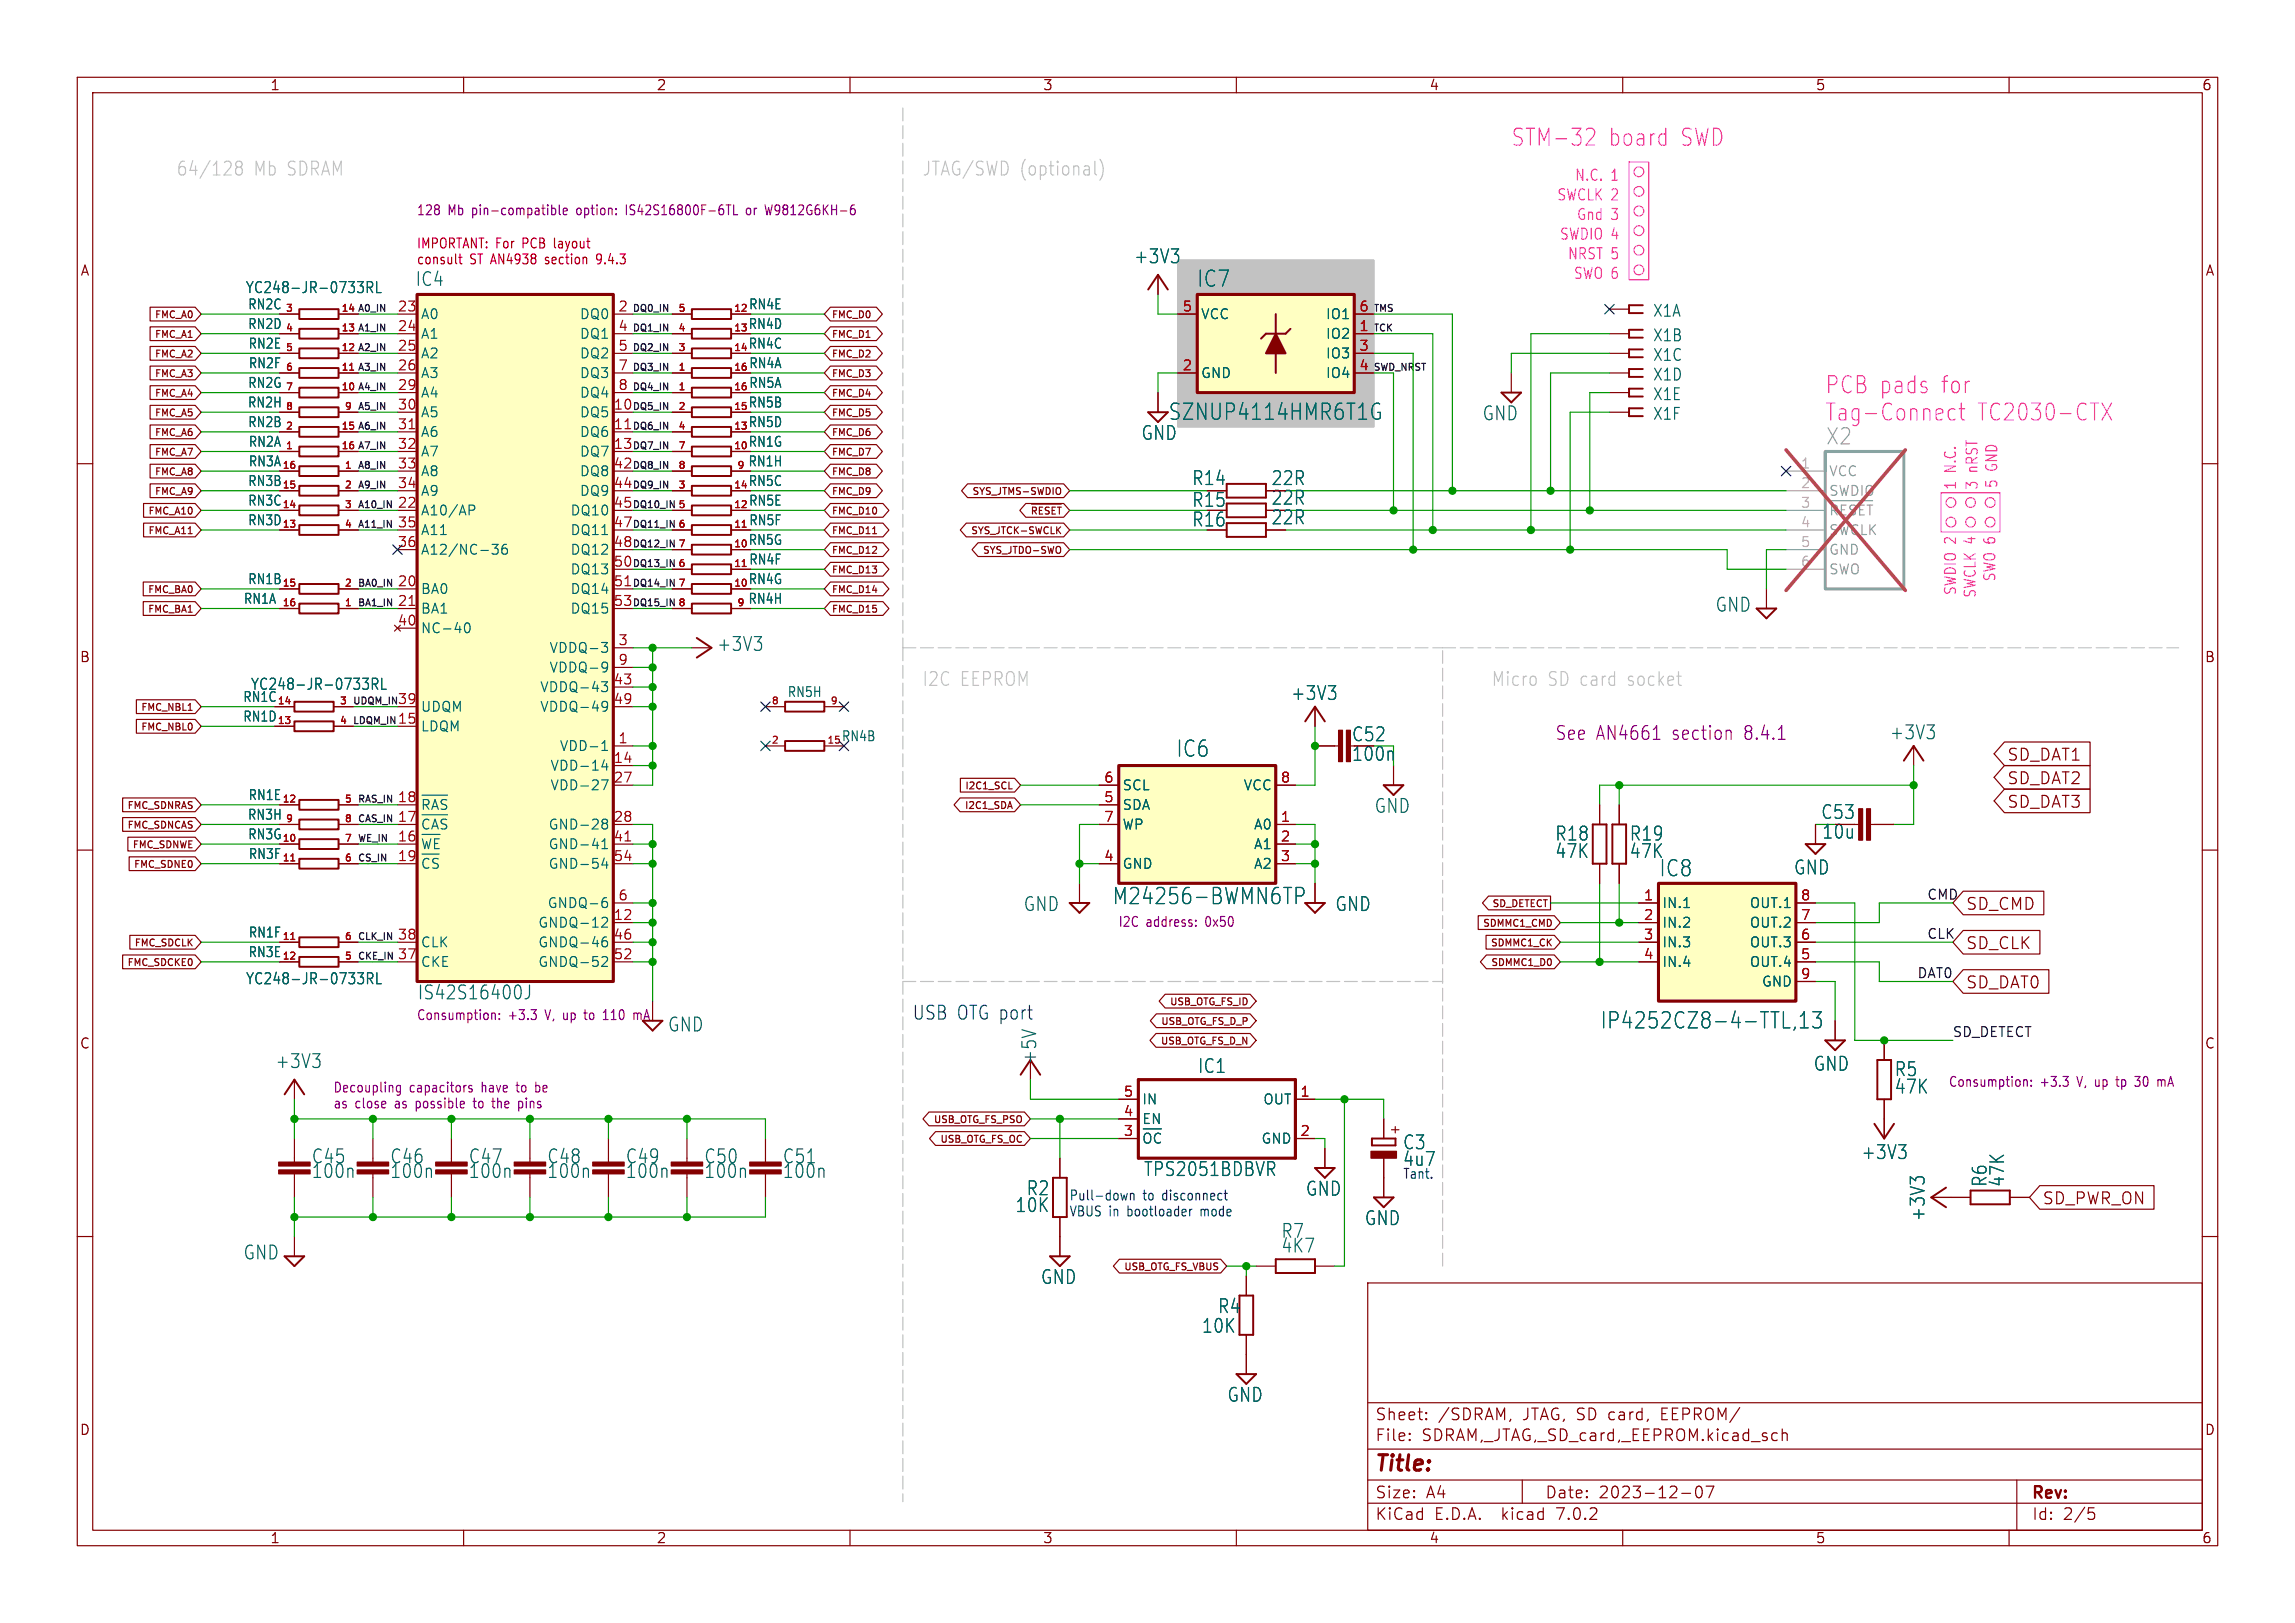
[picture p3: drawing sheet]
<svg xmlns="http://www.w3.org/2000/svg" width="297mm" height="210mm" viewBox="0 0 297 210" stroke-linecap="round" stroke-linejoin="round" font-family="sans-serif">
<defs><g id="words">
<g font-size="3" fill="#f0f">
<text x="195.6" y="19.1">STM-32</text>
<text x="208.1" y="19.1">board</text>
<text x="217.4" y="19.1">SWD</text>
<text x="236.2" y="51.1">PCB pads</text>
<text x="251.2" y="51.1">for</text>
<text x="236.2" y="54.6">Tag-Connect</text>
<text x="255.9" y="54.6">TC2030-CTX</text>
</g>
<g font-size="2.9" fill="#006464">
<text x="154.9" y="37.3">IC7</text>
<text x="151.2" y="54.5">SZNUP4114HMR6T1G</text>
<text x="152.2" y="98.1">IC6</text>
<text x="214.7" y="113.6">IC8</text>
<text x="144" y="117.2">M24256-BWMN6TP</text>
<text x="207.1" y="133.3">IP4252CZ8-4-TTL,13</text>
</g>
<text font-size="2.9" fill="#f0f" x="236.3" y="57.7">X2</text>
<text font-size="2.8" fill="#840000" x="178" y="190.8">Title:</text>
<g font-size="2.5" fill="#c2c2c2">
<text x="22.9" y="22.9">64/128</text>
<text x="32.9" y="22.9">Mb SDRAM</text>
<text x="119.4" y="22.9">JTAG/SWD (optional)</text>
<text x="119.4" y="88.9">I2C EEPROM</text>
<text x="193" y="88.9">Micro</text>
<text x="200.3" y="88.9">SD card</text>
<text x="210.7" y="88.9">socket</text>
</g>
<g font-size="2.5" fill="#006464">
<text x="146.7" y="34.2">+3V3</text>
<text x="53.7" y="37.2">IC4</text>
<text x="147.7" y="57.1">GND</text>
<text x="191.8" y="54.6">GND</text>
<text x="154.2" y="65.8">R15</text>
<text x="164.5" y="65.5">22R</text>
<text x="222" y="79.3">GND</text>
<text x="92.8" y="84.4">+3V3</text>
<text x="167.1" y="90.8">+3V3</text>
<text x="244.5" y="95.8">+3V3</text>
<text x="174.9" y="98.6">100n</text>
<text x="177.8" y="105.4">GND</text>
<text x="201.2" y="108.9">R18</text>
<text x="201.2" y="111.2">47K</text>
<text x="210.9" y="108.9">R19</text>
<text x="210.9" y="111.2">47K</text>
<text x="232.1" y="113.3">GND</text>
<text x="235.8" y="108.7">10u</text>
<text x="132.4" y="118.1">GND</text>
<text x="172.8" y="118.1">GND</text>
<text x="54" y="129.5">IS42S16400J</text>
<text x="86.4" y="133.6">GND</text>
<text x="134.3" y="137.7" transform="rotate(-90 134.3 137.7)">+5V</text>
<text x="35.6" y="138.4">+3V3</text>
<text x="155" y="139">IC1</text>
<text x="234.7" y="138.7">GND</text>
<text x="245.2" y="139.4">R5</text>
<text x="245.2" y="141.7">47K</text>
<text x="181.5" y="148.9">C3</text>
<text x="40.3" y="150.7">C45</text>
<text x="40.3" y="152.6">100n</text>
<text x="50.5" y="150.7">C46</text>
<text x="50.5" y="152.6">100n</text>
<text x="60.6" y="150.7">C47</text>
<text x="60.6" y="152.6">100n</text>
<text x="70.8" y="150.7">C48</text>
<text x="70.8" y="152.6">100n</text>
<text x="80.9" y="150.7">C49</text>
<text x="80.9" y="152.6">100n</text>
<text x="91.1" y="150.7">C50</text>
<text x="91.1" y="152.6">100n</text>
<text x="101.3" y="150.7">C51</text>
<text x="101.3" y="152.6">100n</text>
<text x="132.8" y="154.8">R2</text>
<text x="148" y="152.4">TPS2051BDBVR</text>
<text x="169" y="154.9">GND</text>
<text x="181.5" y="151">4u7</text>
<text x="240.8" y="150.2">+3V3</text>
<text x="257.3" y="153.6" transform="rotate(-90 257.3 153.6)">R6</text>
<text x="259.5" y="153.6" transform="rotate(-90 259.5 153.6)">47K</text>
<text x="131.4" y="157">10K</text>
<text x="165.8" y="160.4">R7</text>
<text x="176.6" y="158.7">GND</text>
<text x="249.3" y="158.1" transform="rotate(-90 249.3 158.1)">+3V3</text>
<text x="31.5" y="163.1">GND</text>
<text x="134.7" y="166.3">GND</text>
<text x="165.8" y="162.3">4K7</text>
<text x="155.5" y="172.6">10K</text>
<text x="157.6" y="170.1">R4</text>
<text x="158.8" y="181.6">GND</text>
</g>
<g font-size="2.5" fill="#840000">
<text x="154.2" y="62.9">R14</text>
<text x="164.5" y="62.9">22R</text>
<text x="154.2" y="68.3">R16</text>
<text x="164.5" y="68">22R</text>
<text x="174.9" y="96.1">C52</text>
<text x="235.6" y="106.2">C53</text>
</g>
<g font-size="2.5" fill="#840084">
<text x="201.3" y="95.9">See AN4661</text>
<text x="216.4" y="95.9">section</text>
<text x="225.8" y="95.9">8.4.1</text>
</g>
<text font-size="2.5" fill="#0000c2" x="118.1" y="132.1">USB OTG port</text>
<g font-size="2.1" fill="#006464">
<text x="213.9" y="41.2">X1A</text>
<text x="213.9" y="46.9">X1C</text>
<text x="213.9" y="44.3">X1B</text>
<text x="213.9" y="49.4">X1D</text>
<text x="213.9" y="52">X1E</text>
<text x="213.9" y="54.5">X1F</text>
</g>
<g font-size="2.1" fill="#840000">
<text x="259.8" y="98.6">SD_DAT1</text>
<text x="259.8" y="101.6">SD_DAT2</text>
<text x="259.8" y="104.7">SD_DAT3</text>
<text x="254.4" y="117.9">SD_CMD</text>
<text x="254.4" y="123">SD_CLK</text>
<text x="254.4" y="128.1">SD_DAT0</text>
<text x="264.4" y="156">SD_PWR_ON</text>
<text x="178" y="183.9">Sheet:</text>
<text x="186.2" y="183.9">/SDRAM,</text>
<text x="197.1" y="183.9">JTAG, SD card,</text>
<text x="215.1" y="183.9">EEPROM/</text>
<text x="178" y="186.6">File:</text>
<text x="184" y="186.6">SDRAM,_JTAG,_SD_card,_EEPROM.kicad_sch</text>
<text x="178" y="196.8">KiCad</text>
<text x="178" y="194">Size:</text>
<text x="184.6" y="194">A4</text>
<text x="185.7" y="196.8">E.D.A.</text>
<text x="194.4" y="196.8">kicad</text>
<text x="200" y="194">Date:</text>
<text x="201.5" y="196.8">7.0.2</text>
<text x="206.9" y="194">2023-12-07</text>
<text x="263" y="194.2">Rev:</text>
<text x="263" y="196.8">Id:</text>
<text x="267" y="196.8">2/5</text>
</g>
<g font-size="2" fill="#f0f">
<text x="203.7" y="23.5">N.C. 1</text>
<text x="201.4" y="26">SWCLK 2</text>
<text x="203.9" y="28.6">Gnd 3</text>
<text x="201.8" y="31.1">SWDIO 4</text>
<text x="202.8" y="33.7">NRST 5</text>
<text x="203.5" y="36.2">SWO 6</text>
<text x="253.2" y="63.5" transform="rotate(-90 253.2 63.5)">1 N.C.</text>
<text x="256" y="63.5" transform="rotate(-90 256 63.5)">3 nRST</text>
<text x="258.6" y="63.3" transform="rotate(-90 258.6 63.3)">5 GND</text>
<text x="253.2" y="77.1" transform="rotate(-90 253.2 77.1)">SWDIO 2</text>
<text x="255.8" y="77.5" transform="rotate(-90 255.8 77.5)">SWCLK 4</text>
<text x="258.3" y="75.4" transform="rotate(-90 258.3 75.4)">SWO 6</text>
</g>
<g font-size="2" fill="#006464">
<text x="31.7" y="38.1">YC248-JR-0733RL</text>
<text x="32.4" y="89.4">YC248-JR-0733RL</text>
<text x="31.8" y="127.5">YC248-JR-0733RL</text>
</g>
<g font-size="1.8" fill="#840000">
<text x="35" y="11.8">1</text>
<text x="85" y="11.8">2</text>
<text x="135" y="11.8">3</text>
<text x="185" y="11.8">4</text>
<text x="235" y="11.8">5</text>
<text x="285" y="11.8">6</text>
<text x="10.4" y="35.8">A</text>
<text x="285.4" y="35.8">A</text>
<text x="10.3" y="85.8">B</text>
<text x="285.3" y="85.8">B</text>
<text x="10.3" y="135.8">C</text>
<text x="285.3" y="135.8">C</text>
<text x="181.3" y="146.9" transform="rotate(-90 181.3 146.9)">+</text>
<text x="10.3" y="185.8">D</text>
<text x="285.3" y="185.8">D</text>
<text x="35" y="199.8">1</text>
<text x="85" y="199.8">2</text>
<text x="135" y="199.8">3</text>
<text x="185" y="199.8">4</text>
<text x="235" y="199.8">5</text>
<text x="285" y="199.8">6</text>
</g>
<g font-size="1.8" fill="#840084">
<text x="54" y="27.9">128</text>
<text x="58" y="27.9">Mb pin-compatible</text>
<text x="74.9" y="27.9">option:</text>
<text x="81.5" y="27.9">IS42S16800F-6TL</text>
<text x="97.2" y="27.9">or</text>
<text x="99.8" y="27.9">W9812G6KH-6</text>
<text x="144.8" y="120">I2C</text>
<text x="148.4" y="120">address:</text>
<text x="156.2" y="120">0x50</text>
<text x="54" y="132.1">Consumption:</text>
<text x="65.9" y="132.1">+3.3</text>
<text x="70.8" y="132.1">V, up</text>
<text x="76.1" y="132.1">to</text>
<text x="78.7" y="132.1">110</text>
<text x="82.8" y="132.1">mA</text>
<text x="43.2" y="141.5">Decoupling</text>
<text x="43.2" y="143.5">as</text>
<text x="46" y="143.5">close</text>
<text x="51.3" y="143.5">as</text>
<text x="53.1" y="141.5">capacitors</text>
<text x="54.1" y="143.5">possible</text>
<text x="61.8" y="143.5">to</text>
<text x="62.5" y="141.5">have</text>
<text x="64.4" y="143.5">the</text>
<text x="67.2" y="141.5">to</text>
<text x="67.9" y="143.5">pins</text>
<text x="69.7" y="141.5">be</text>
<text x="252.2" y="140.7">Consumption:</text>
<text x="264.1" y="140.7">+3.3</text>
<text x="269" y="140.7">V, up</text>
<text x="274.4" y="140.7">tp</text>
<text x="277" y="140.7">30</text>
<text x="280" y="140.7">mA</text>
</g>
<g font-size="1.8" fill="#f00">
<text x="54" y="32.2">IMPORTANT: For</text>
<text x="54" y="34.3">consult</text>
<text x="60.9" y="34.3">ST AN4938</text>
<text x="67.8" y="32.2">PCB layout</text>
<text x="70.9" y="34.3">section</text>
<text x="77.7" y="34.3">9.4.3</text>
</g>
<g font-size="1.8" fill="#006464">
<text x="32" y="40.2">RN2C</text>
<text x="54.5" y="41.5">A0</text>
<text x="74.9" y="41.5">DQ0</text>
<text x="96.9" y="40.2">RN4E</text>
<text x="155.4" y="41.5">VCC</text>
<text x="171.5" y="41.5">IO1</text>
<text x="32" y="42.7">RN2D</text>
<text x="32.1" y="45.3">RN2E</text>
<text x="32.1" y="47.8">RN2F</text>
<text x="54.5" y="44">A1</text>
<text x="54.5" y="46.5">A2</text>
<text x="74.9" y="44">DQ1</text>
<text x="74.9" y="46.5">DQ2</text>
<text x="96.8" y="45.3">RN4C</text>
<text x="96.8" y="42.7">RN4D</text>
<text x="96.9" y="47.8">RN4A</text>
<text x="171.5" y="44">IO2</text>
<text x="171.5" y="46.5">IO3</text>
<text x="32" y="52.9">RN2H</text>
<text x="32" y="50.4">RN2G</text>
<text x="54.5" y="49.1">A3</text>
<text x="54.5" y="51.6">A4</text>
<text x="74.9" y="49.1">DQ3</text>
<text x="74.9" y="51.6">DQ4</text>
<text x="96.8" y="52.9">RN5B</text>
<text x="96.9" y="50.4">RN5A</text>
<text x="155.4" y="49.1">GND</text>
<text x="171.5" y="49.1">IO4</text>
<text x="32" y="55.4">RN2B</text>
<text x="32.1" y="58">RN2A</text>
<text x="54.5" y="54.2">A5</text>
<text x="54.5" y="56.7">A6</text>
<text x="54.5" y="59.2">A7</text>
<text x="74.9" y="54.2">DQ5</text>
<text x="74.9" y="56.7">DQ6</text>
<text x="74.9" y="59.2">DQ7</text>
<text x="96.8" y="55.4">RN5D</text>
<text x="96.8" y="58">RN1G</text>
<text x="32" y="63.1">RN3B</text>
<text x="32" y="65.6">RN3C</text>
<text x="32.1" y="60.5">RN3A</text>
<text x="54.5" y="61.8">A8</text>
<text x="54.5" y="64.3">A9</text>
<text x="74.9" y="61.8">DQ8</text>
<text x="74.9" y="64.3">DQ9</text>
<text x="96.8" y="60.5">RN1H</text>
<text x="96.8" y="63.1">RN5C</text>
<text x="96.9" y="65.6">RN5E</text>
<text x="32" y="68.1">RN3D</text>
<text x="54.5" y="66.9">A10/AP</text>
<text x="54.5" y="69.4">A11</text>
<text x="54.5" y="71.9">A12/NC-36</text>
<text x="73.7" y="66.9">DQ10</text>
<text x="73.7" y="69.4">DQ11</text>
<text x="73.7" y="71.9">DQ12</text>
<text x="96.8" y="70.7">RN5G</text>
<text x="96.9" y="68.1">RN5F</text>
<text x="32" y="75.8">RN1B</text>
<text x="54.5" y="77">BA0</text>
<text x="73.7" y="74.5">DQ13</text>
<text x="73.7" y="77">DQ14</text>
<text x="96.8" y="75.8">RN4G</text>
<text x="96.9" y="73.2">RN4F</text>
<text x="31.5" y="78.3">RN1A</text>
<text x="54.5" y="79.6">BA1</text>
<text x="54.5" y="82.1">NC-40</text>
<text x="73.7" y="79.6">DQ15</text>
<text x="96.8" y="78.3">RN4H</text>
<text x="69.8" y="89.7">VDDQ-43</text>
<text x="71" y="84.6">VDDQ-3</text>
<text x="71" y="87.2">VDDQ-9</text>
<text x="31.4" y="91">RN1C</text>
<text x="31.4" y="93.5">RN1D</text>
<text x="54.5" y="94.8">LDQM</text>
<text x="54.5" y="92.3">UDQM</text>
<text x="69.8" y="92.3">VDDQ-49</text>
<text x="101.9" y="90.4">RN5H</text>
<text x="71.1" y="99.9">VDD-14</text>
<text x="72.3" y="97.3">VDD-1</text>
<text x="108.9" y="96.1">RN4B</text>
<text x="32" y="106.2">RN3H</text>
<text x="32.1" y="103.7">RN1E</text>
<text x="54.5" y="105.6">~{RAS}</text>
<text x="70.9" y="107.5">GND-28</text>
<text x="71.1" y="102.4">VDD-27</text>
<text x="145.3" y="105">SDA</text>
<text x="145.3" y="102.4">SCL</text>
<text x="145.3" y="107.5">WP</text>
<text x="160.8" y="102.4">VCC</text>
<text x="162.2" y="107.5">A0</text>
<text x="32" y="108.8">RN3G</text>
<text x="32.1" y="111.3">RN3F</text>
<text x="54.5" y="110.7">~{WE}</text>
<text x="54.5" y="108.1">~{CAS}</text>
<text x="54.5" y="113.2">~{CS}</text>
<text x="70.9" y="110">GND-41</text>
<text x="70.9" y="112.6">GND-54</text>
<text x="145.3" y="112.6">GND</text>
<text x="162.2" y="110">A1</text>
<text x="162.2" y="112.6">A2</text>
<text x="70.8" y="117.7">GNDQ-6</text>
<text x="215.1" y="117.7">IN.1</text>
<text x="226.3" y="117.7">OUT.1</text>
<text x="32.1" y="124">RN3E</text>
<text x="32.1" y="121.5">RN1F</text>
<text x="54.5" y="125.3">CKE</text>
<text x="54.5" y="122.7">CLK</text>
<text x="69.5" y="120.2">GNDQ-12</text>
<text x="69.5" y="122.7">GNDQ-46</text>
<text x="69.5" y="125.3">GNDQ-52</text>
<text x="215.1" y="120.2">IN.2</text>
<text x="215.1" y="122.7">IN.3</text>
<text x="215.1" y="125.3">IN.4</text>
<text x="226.3" y="125.3">OUT.4</text>
<text x="226.3" y="122.7">OUT.3</text>
<text x="226.3" y="120.2">OUT.2</text>
<text x="227.9" y="127.8">GND</text>
<text x="147.8" y="143.1">IN</text>
<text x="163.4" y="143.1">OUT</text>
<text x="147.8" y="148.8">~{OC}</text>
<text x="147.8" y="145.6">EN</text>
<text x="163.1" y="148.1">GND</text>
</g>
<g font-size="1.8" fill="#a90000">
<text x="51.4" y="40.4">23</text>
<text x="80" y="40.4">2</text>
<text x="153" y="40.4">5</text>
<text x="175.9" y="40.4">6</text>
<text x="51.4" y="42.9">24</text>
<text x="51.4" y="45.5">25</text>
<text x="80" y="42.9">4</text>
<text x="80" y="45.5">5</text>
<text x="175.9" y="42.9">1</text>
<text x="175.9" y="45.5">3</text>
<text x="51.4" y="48">26</text>
<text x="51.4" y="50.5">29</text>
<text x="51.4" y="53.1">30</text>
<text x="79.4" y="53.1">10</text>
<text x="80" y="48">7</text>
<text x="80" y="50.5">8</text>
<text x="153" y="48">2</text>
<text x="175.9" y="48">4</text>
<text x="51.4" y="55.6">31</text>
<text x="51.4" y="58.2">32</text>
<text x="79.4" y="55.6">11</text>
<text x="79.4" y="58.2">13</text>
<text x="51.4" y="65.8">22</text>
<text x="51.4" y="60.7">33</text>
<text x="51.4" y="63.2">34</text>
<text x="79.4" y="60.7">42</text>
<text x="79.4" y="63.2">44</text>
<text x="79.4" y="65.8">45</text>
<text x="51.4" y="68.3">35</text>
<text x="51.4" y="70.9">36</text>
<text x="79.4" y="68.3">47</text>
<text x="79.4" y="70.9">48</text>
<text x="51.4" y="75.9">20</text>
<text x="79.4" y="73.4">50</text>
<text x="79.4" y="75.9">51</text>
<text x="51.4" y="78.5">21</text>
<text x="51.4" y="81">40</text>
<text x="79.4" y="78.5">53</text>
<text x="80" y="83.6">3</text>
<text x="79.4" y="88.6">43</text>
<text x="80" y="86.1">9</text>
<text x="79.4" y="91.2">49</text>
<text x="79.4" y="98.8">14</text>
<text x="79.4" y="101.3">27</text>
<text x="80" y="96.3">1</text>
<text x="142.8" y="101.3">6</text>
<text x="165.7" y="101.3">8</text>
<text x="51.4" y="106.4">17</text>
<text x="51.4" y="103.9">18</text>
<text x="79.4" y="106.4">28</text>
<text x="142.8" y="103.9">5</text>
<text x="142.8" y="106.4">7</text>
<text x="165.7" y="106.4">1</text>
<text x="51.4" y="109">16</text>
<text x="51.4" y="111.5">19</text>
<text x="79.4" y="109">41</text>
<text x="79.4" y="111.5">54</text>
<text x="142.8" y="111.5">4</text>
<text x="165.7" y="109">2</text>
<text x="165.7" y="111.5">3</text>
<text x="79.4" y="119.1">12</text>
<text x="80" y="116.6">6</text>
<text x="212.7" y="116.6">1</text>
<text x="212.7" y="119.1">2</text>
<text x="233" y="119.1">7</text>
<text x="233" y="116.6">8</text>
<text x="51.4" y="124.2">37</text>
<text x="51.4" y="121.7">38</text>
<text x="79.4" y="121.7">46</text>
<text x="79.4" y="124.2">52</text>
<text x="212.7" y="121.7">3</text>
<text x="212.7" y="124.2">4</text>
<text x="233" y="124.2">5</text>
<text x="233" y="121.7">6</text>
<text x="233" y="126.7">9</text>
<text x="145.4" y="142">5</text>
<text x="168.2" y="142">1</text>
<text x="145.4" y="147.1">3</text>
<text x="145.4" y="144.5">4</text>
<text x="168.2" y="147.1">2</text>
</g>
<g font-size="1.8" fill="#aaa">
<text x="233" y="60.7">1</text>
<text x="233" y="63.2">2</text>
<text x="233" y="65.8">3</text>
<text x="233" y="68.3">4</text>
<text x="233" y="70.9">5</text>
<text x="233" y="73.4">6</text>
</g>
<g font-size="1.8" fill="#989898">
<text x="236.7" y="61.8">VCC</text>
<text x="236.7" y="64.3">SWDIO</text>
<text x="236.7" y="67.5">~{RESET}</text>
<text x="236.7" y="69.4">SWCLK</text>
<text x="236.7" y="71.9">GND</text>
<text x="236.7" y="74.5">SWO</text>
</g>
<g font-size="1.8" fill="#0f0f0f">
<text x="51.4" y="93.7">15</text>
<text x="51.4" y="91.2">39</text>
<text x="249.4" y="116.5">CMD</text>
<text x="249.4" y="121.6">CLK</text>
<text x="248.2" y="126.7">DAT0</text>
<text x="252.7" y="134.3">SD_DETECT</text>
</g>
<g font-size="1.8" fill="#0000c2">
<text x="138.4" y="155.4">Pull-down</text>
<text x="148" y="155.4">to</text>
<text x="150.6" y="155.4">disconnect</text>
<text x="181.6" y="152.8">Tant.</text>
<text x="138.4" y="157.5">VBUS in</text>
<text x="146.1" y="157.5">bootloader</text>
<text x="155.7" y="157.5">mode</text>
</g>
<g font-size="1.2" fill="#840000">
<text x="19.9" y="41.3">FMC_A0</text>
<text x="107.7" y="41.3">FMC_D0</text>
<text x="19.9" y="43.9">FMC_A1</text>
<text x="19.9" y="46.4">FMC_A2</text>
<text x="107.7" y="43.9">FMC_D1</text>
<text x="107.7" y="46.4">FMC_D2</text>
<text x="19.9" y="49">FMC_A3</text>
<text x="19.9" y="51.5">FMC_A4</text>
<text x="107.7" y="51.5">FMC_D4</text>
<text x="107.7" y="49">FMC_D3</text>
<text x="19.9" y="54">FMC_A5</text>
<text x="19.9" y="59.1">FMC_A7</text>
<text x="19.9" y="56.6">FMC_A6</text>
<text x="107.7" y="54">FMC_D5</text>
<text x="107.7" y="56.6">FMC_D6</text>
<text x="107.7" y="59.1">FMC_D7</text>
<text x="19.9" y="61.7">FMC_A8</text>
<text x="19.9" y="64.2">FMC_A9</text>
<text x="107.7" y="64.2">FMC_D9</text>
<text x="107.7" y="61.7">FMC_D8</text>
<text x="125.7" y="64.2">SYS_JTMS-SWDIO</text>
<text x="19" y="69.3">FMC_A11</text>
<text x="19" y="66.7">FMC_A10</text>
<text x="107.7" y="66.7">FMC_D10</text>
<text x="107.7" y="69.3">FMC_D11</text>
<text x="107.7" y="71.8">FMC_D12</text>
<text x="125.5" y="69.3">SYS_JTCK-SWCLK</text>
<text x="127" y="71.8">SYS_JTDO-SWO</text>
<text x="133.2" y="67.2">~{RESET}</text>
<text x="19" y="76.9">FMC_BA0</text>
<text x="107.7" y="74.4">FMC_D13</text>
<text x="107.7" y="76.9">FMC_D14</text>
<text x="19" y="79.4">FMC_BA1</text>
<text x="107.7" y="79.4">FMC_D15</text>
<text x="18.1" y="94.7">FMC_NBL0</text>
<text x="18.1" y="92.1">FMC_NBL1</text>
<text x="16.3" y="107.4">FMC_SDNCAS</text>
<text x="16.3" y="104.8">FMC_SDNRAS</text>
<text x="124.7" y="104.8">I2C1_SDA</text>
<text x="124.7" y="102.3">I2C1_SCL</text>
<text x="17" y="109.9">FMC_SDNWE</text>
<text x="17.2" y="112.5">FMC_SDNE0</text>
<text x="193" y="117.5">SD_DETECT</text>
<text x="16.3" y="125.2">FMC_SDCKE0</text>
<text x="17.3" y="122.6">FMC_SDCLK</text>
<text x="191.8" y="120.1">SDMMC1_CMD</text>
<text x="192.8" y="122.6">SDMMC1_CK</text>
<text x="192.8" y="125.2">SDMMC1_D0</text>
<text x="151.2" y="130.2">USB_OTG_FS_ID</text>
<text x="150.1" y="135.3">USB_OTG_FS_D_N</text>
<text x="150.1" y="132.8">USB_OTG_FS_D_P</text>
<text x="120.7" y="145.5">USB_OTG_FS_PSO</text>
<text x="121.5" y="148">USB_OTG_FS_OC</text>
<text x="145.3" y="164.5">USB_OTG_FS_VBUS</text>
</g>
<g font-size="1.2" fill="#a90000">
<text x="36.9" y="40.4">3</text>
<text x="44.1" y="40.4">14</text>
<text x="87.7" y="40.4">5</text>
<text x="94.9" y="40.4">12</text>
<text x="36.9" y="42.9">4</text>
<text x="36.9" y="45.5">5</text>
<text x="44.1" y="45.5">12</text>
<text x="44.1" y="42.9">13</text>
<text x="87.7" y="45.5">3</text>
<text x="87.7" y="42.9">4</text>
<text x="94.9" y="45.5">14</text>
<text x="94.9" y="42.9">13</text>
<text x="36.9" y="50.5">7</text>
<text x="36.9" y="53.1">8</text>
<text x="36.9" y="48">6</text>
<text x="44.1" y="48">11 A3_IN</text>
<text x="44.1" y="48">11</text>
<text x="44.1" y="50.5">10</text>
<text x="44.6" y="53.1">9</text>
<text x="87.7" y="53.1">2</text>
<text x="87.7" y="50.5">1</text>
<text x="87.7" y="48">1</text>
<text x="94.9" y="53.1">15</text>
<text x="94.9" y="50.5">16</text>
<text x="94.9" y="48">16</text>
<text x="36.9" y="55.6">2</text>
<text x="36.9" y="58.2">1</text>
<text x="44.1" y="58.2">16</text>
<text x="44.1" y="55.6">15</text>
<text x="87.7" y="55.6">4</text>
<text x="87.7" y="58.2">7</text>
<text x="94.9" y="55.6">13</text>
<text x="94.9" y="58.2">10</text>
<text x="36.5" y="60.7">16</text>
<text x="36.5" y="63.2">15</text>
<text x="36.5" y="65.8">14</text>
<text x="44.6" y="60.7">1</text>
<text x="44.6" y="63.2">2</text>
<text x="44.6" y="65.8">3</text>
<text x="87.7" y="63.2">3</text>
<text x="87.7" y="60.7">8</text>
<text x="87.7" y="65.8">5</text>
<text x="94.9" y="65.8">12</text>
<text x="94.9" y="63.2">14</text>
<text x="95.4" y="60.7">9</text>
<text x="36.5" y="68.3">13</text>
<text x="44.6" y="68.3">4</text>
<text x="87.7" y="68.3">6</text>
<text x="87.7" y="70.9">7</text>
<text x="94.9" y="70.9">10</text>
<text x="94.9" y="68.3">11</text>
<text x="36.5" y="75.9">15</text>
<text x="44.6" y="75.9">2</text>
<text x="87.7" y="73.4">6</text>
<text x="87.7" y="75.9">7</text>
<text x="94.9" y="73.4">11</text>
<text x="94.9" y="75.9">10</text>
<text x="36.5" y="78.5">16</text>
<text x="44.6" y="78.5">1</text>
<text x="87.7" y="78.5">8</text>
<text x="95.4" y="78.5">9</text>
<text x="35.9" y="91.2">14</text>
<text x="35.9" y="93.7">13</text>
<text x="43.9" y="91.2">3</text>
<text x="43.9" y="93.7">4</text>
<text x="99.8" y="91.2">8</text>
<text x="107.4" y="91.2">9</text>
<text x="99.8" y="96.3">2</text>
<text x="107" y="96.3">15</text>
<text x="36.5" y="103.9">12</text>
<text x="36.9" y="106.4">9</text>
<text x="44.6" y="106.4">8</text>
<text x="44.6" y="103.9">5</text>
<text x="36.5" y="109">10</text>
<text x="36.5" y="111.5">11</text>
<text x="44.6" y="109">7</text>
<text x="44.6" y="111.5">6</text>
<text x="36.5" y="121.7">11</text>
<text x="36.5" y="124.2">12</text>
<text x="44.6" y="121.7">6</text>
<text x="44.6" y="124.2">5</text>
</g>
<g font-size="1.2" fill="#0f0f0f">
<text x="44.1" y="40.4">14 A0_IN</text>
<text x="81.9" y="40.4">DQ0_IN</text>
<text x="177.8" y="40.4">TMS</text>
<text x="44.1" y="42.9">13 A1_IN</text>
<text x="44.1" y="45.5">12 A2_IN</text>
<text x="81.9" y="42.9">DQ1_IN</text>
<text x="81.9" y="45.5">DQ2_IN</text>
<text x="177.8" y="42.9">TCK</text>
<text x="44.1" y="50.5">10 A4_IN</text>
<text x="46.4" y="53.1">A5_IN</text>
<text x="81.9" y="53.1">DQ5_IN</text>
<text x="81.9" y="48">DQ3_IN</text>
<text x="81.9" y="50.6">DQ4_IN</text>
<text x="177.8" y="48">SWD_NRST</text>
<text x="44.1" y="55.6">15 A6_IN</text>
<text x="44.1" y="58.2">16 A7_IN</text>
<text x="81.9" y="58.2">DQ7_IN</text>
<text x="81.9" y="55.6">DQ6_IN</text>
<text x="46.4" y="60.7">A8_IN</text>
<text x="46.4" y="63.3">A9_IN</text>
<text x="46.4" y="65.8">A10_IN</text>
<text x="81.9" y="60.7">DQ8_IN</text>
<text x="81.9" y="63.3">DQ9_IN</text>
<text x="81.9" y="65.8">DQ10_IN 5</text>
<text x="46.4" y="68.3">A11_IN</text>
<text x="81.9" y="70.9">DQ12_IN 7</text>
<text x="81.9" y="68.3">DQ11_IN 6</text>
<text x="46.4" y="76">BA0_IN</text>
<text x="81.9" y="76">DQ14_IN 7</text>
<text x="81.9" y="73.4">DQ13_IN 6</text>
<text x="81.9" y="78.5">DQ15_IN 8</text>
<text x="45.7" y="93.7">LDQM_IN</text>
<text x="45.7" y="91.2">UDQM_IN</text>
<text x="46.4" y="103.9">RAS_IN</text>
<text x="46.4" y="106.4">CAS_IN</text>
<text x="46.4" y="109">WE_IN</text>
<text x="46.4" y="121.7">CLK_IN</text>
</g>
<g font-size="1.2" fill="#009600">
<text x="46.4" y="78.5">BA1_IN</text>
<text x="46.4" y="111.5">CS_IN</text>
<text x="46.4" y="124.2">CKE_IN</text>
</g>
</g></defs>
<g fill="none" stroke="#840000" stroke-width=".15">
<path d="M10 10h277v190h-277zM12 12h273v186h-273zM60 10v2M110 10v2M160 10v2M210 10v2M260 10v2M19.4 39.8h5.9l.7 .8-.7 .9h-5.9zM107.5 39.8h5.9l.8 .8-.8 .9h-5.9l-.8-.9zM149.9 35.6v2.5M10 60h2M19.4 47.4h5.9l.7 .9-.7 .8h-5.9z"/>
<path d="M19.4 52.5h5.9l.7 .8-.7 .9h-5.9zM19.4 57.5h5.9l.7 .9-.7 .9h-5.9zM19.4 55h5.9l.7 .9-.7 .9h-5.9zM19.4 49.9h5.9l.7 .9-.7 .9h-5.9zM19.4 42.3h5.9l.7 .9-.7 .9h-5.9zM19.4 44.8h5.9l.7 .9-.7 .9h-5.9zM36.2 40.6h2.5M36.2 55.9h2.5M36.2 58.4h2.5M36.2 53.3h2.5M36.2 45.7h2.5M36.2 50.8h2.5"/>
<path d="M36.2 43.2h2.5M36.2 48.3h2.5M43.8 40.6h2.6M43.8 55.9h2.6M43.8 58.4h2.6M43.8 53.3h2.6M43.8 45.7h2.6M43.8 50.8h2.6M43.8 43.2h2.6M43.8 48.3h2.6M51.4 40.6h2.6M51.4 55.9h2.6"/>
<path d="M51.4 58.4h2.6M51.4 53.3h2.6M51.4 45.7h2.6M51.4 50.8h2.6M51.4 43.2h2.6M51.4 48.3h2.6M79.4 40.6h2.5M79.4 55.9h2.5M79.4 58.4h2.5M79.4 53.3h2.5M79.4 45.7h2.5M79.4 50.8h2.5"/>
<path d="M79.4 43.2h2.5M79.4 48.3h2.5M87 40.6h2.5M87 55.9h2.5M87 58.4h2.5M87 53.3h2.5M87 45.7h2.5M87 50.8h2.5M87 43.2h2.5M87 48.3h2.5M94.6 40.6h2.6M94.6 55.9h2.6"/>
<path d="M94.6 58.4h2.6M94.6 53.3h2.6M94.6 45.7h2.6M94.6 50.8h2.6M94.6 43.2h2.6M94.6 48.3h2.6M107.5 49.9h5.9l.8 .9-.8 .9h-5.9l-.8-.9zM107.5 47.4h5.9l.8 .9-.8 .8h-5.9l-.8-.8zM107.5 52.5h5.9l.8 .8-.8 .9h-5.9l-.8-.9zM107.5 55h5.9l.8 .9-.8 .9h-5.9l-.8-.9zM107.5 57.5h5.9l.8 .9-.8 .9h-5.9l-.8-.9zM107.5 42.3h5.9l.8 .9-.8 .9h-5.9l-.8-.9z"/>
<path d="M107.5 44.8h5.9l.8 .9-.8 .9h-5.9l-.8-.9zM149.9 50.8v2.5M152.4 40.6h2.5M152.4 48.3h2.5M175.3 40.6h2.5M175.3 45.7h2.5M175.3 43.2h2.5M175.3 48.3h2.5M195.6 48.3v2.5M208.3 53.3h2.5M208.3 45.7h2.5M208.3 50.8h2.5"/>
<path d="M208.3 43.2h2.5M208.3 48.3h2.5M208.3 40h2.5M285 60h2M18.5 77.9h6.8l.7 .8-.7 .9h-6.8zM18.5 75.3h6.8l.7 .9-.7 .9h-6.8zM18.6 67.7h6.7l.7 .9-.7 .9h-6.7zM18.6 65.2h6.7l.7 .8-.7 .9h-6.7zM19.4 60.1h5.9l.7 .9-.7 .8h-5.9zM19.4 62.6h5.9l.7 .9-.7 .9h-5.9zM24.4 69.1h.5M36.2 66h2.5"/>
<path d="M36.2 63.5h2.5M36.2 61h2.5M36.2 78.7h2.5M36.2 68.6h2.5M36.2 76.2h2.5M43.8 66h2.6M43.8 63.5h2.6M43.8 61h2.6M43.8 78.7h2.6M43.8 68.6h2.6M43.8 76.2h2.6M51.4 66h2.6"/>
<path d="M51.4 63.5h2.6M51.4 61h2.6M51.4 78.7h2.6M51.4 71.1h2.6M51.4 68.6h2.6M51.4 76.2h2.6M79.4 66h2.5M79.4 63.5h2.5M79.4 61h2.5M79.4 78.7h2.5M79.4 71.1h2.5M79.4 73.7h2.5"/>
<path d="M79.4 68.6h2.5M79.4 76.2h2.5M87 66h2.5M87 63.5h2.5M87 61h2.5M87 78.7h2.5M87 71.1h2.5M87 73.7h2.5M87 68.6h2.5M87 76.2h2.5M94.6 66h2.6M94.6 63.5h2.6"/>
<path d="M94.6 61h2.6M94.6 78.7h2.6M94.6 71.1h2.6M94.6 73.7h2.6M94.6 68.6h2.6M94.6 76.2h2.6M107.5 62.6h5.9l.8 .9-.8 .9h-5.9l-.8-.9zM107.5 65.2h6.8l.7 .8-.7 .9h-6.8l-.8-.9zM107.5 60.1h5.9l.8 .9-.8 .8h-5.9l-.8-.8zM107.5 67.7h6.8l.7 .9-.7 .9h-6.8l-.8-.9zM107.5 72.8h6.8l.7 .9-.7 .8h-6.8l-.8-.8zM107.5 70.2h6.8l.7 .9-.7 .9h-6.8l-.8-.9z"/>
<path d="M107.5 77.9h6.8l.7 .8-.7 .9h-6.8l-.8-.9zM107.5 75.3h6.8l.7 .9-.7 .9h-6.8l-.8-.9zM125 67.7h12.7l.7 .9-.7 .9h-12.7l-.7-.9zM125.2 62.6h12.5l.7 .9-.7 .9h-12.5l-.8-.9zM126.6 70.2h11.1l.7 .9-.7 .9h-11.1l-.8-.9zM132.8 65.2h4.9l.7 .8-.7 .9h-4.9l-.8-.9zM133.5 65.2h3.8M134.1 65.9l-.1-.2-.4-.1v.9M134.9 65.6h-.4v.9M135.8 65.7l-.4-.1-.1 .3M136.6 65.6h-.4v.9M136.8 65.6h.5"/>
<path d="M136.9 68.5l.4 .6M137 63.1h.1a.57 .57 0 0 1-.1 .9M137.1 65.6v.9M137.1 70.7a.63 .63 0 0 1 0 .9M137.3 68.2l-.5 .5M228.6 76.2v2.5M17.6 93.1h7.7l.7 .9-.7 .9h-7.7zM17.6 90.6h7.7l.7 .8-.7 .9h-7.7zM24.4 91.9h.5M35.6 91.4h2.5M35.6 94h2.5M43.2 91.4h2.5"/>
<path d="M43.2 94h2.5M51.4 91.4h2.6M51.4 94h2.6M51.4 81.3h2.6M79.4 91.4h2.5M79.4 96.5h2.5M79.4 83.8h2.5M79.4 99.1h2.5M79.4 88.9h2.5M79.4 86.4h2.5M89.5 83.8h2.6M99.1 91.4h2.5"/>
<path d="M99.1 96.5h2.5M106.7 91.4h2.5M106.7 96.5h2.5M170.2 96.5h3M170.2 91.4v2.6M180.3 99.1v2.5M247.6 96.5v2.6M259.4 96h11.1v3.1h-11.1l-1.3-1.6zM259.4 99.1h11.1v3h-11.1l-1.3-1.5zM10 110h2M15.9 105.8h9.4l.7 .9-.7 .9h-9.4zM15.9 103.3h9.4l.7 .8-.7 .9h-9.4z"/>
<path d="M16.5 108.3h8.8l.7 .9-.7 .9h-8.8zM16.7 110.9h8.6l.7 .9-.7 .8h-8.6zM36.2 106.7h2.5M36.2 109.2h2.5M36.2 111.8h2.5M36.2 104.1h2.5M43.8 106.7h2.6M43.8 109.2h2.6M43.8 111.8h2.6M43.8 104.1h2.6M51.4 106.7h2.6M51.4 109.2h2.6"/>
<path d="M51.4 111.8h2.6M51.4 104.1h2.6M79.4 106.7h2.5M79.4 109.2h2.5M79.4 111.8h2.5M79.4 101.6h2.5M79.4 116.8h2.5M79.4 119.4h2.5M124.2 103.3h7.1l.8 .8-.8 .9h-7.1l-.7-.9zM124.3 100.7h7l.8 .9-.8 .9h-7zM130.6 102.1h.4M130.7 103.7l.3 .9"/>
<path d="M139.7 114.3v2.5M142.2 106.7h2.6M142.2 111.8h2.6M142.2 104.1h2.6M142.2 101.6h2.6M165.1 106.7h2.5M165.1 109.2h2.5M165.1 111.8h2.5M165.1 101.6h2.5M170.2 114.3v2.5M191.3 118.5h9.9l.7 .9-.7 .9h-9.9zM192.6 116h8.1v1.7h-8.1l-.8-.9z"/>
<path d="M207 104.1v2.6M207 111.8v2.5M209.5 104.1v2.6M209.5 111.8v2.5M212.1 116.8h2.5M212.1 119.4h2.5M232.4 116.8h2.5M232.4 119.4h2.5M234.9 106.7v2.5M240 106.7h.5M242.1 106.7h3M254.1 115.3h10.4v3.1h-10.4l-1.4-1.6z"/>
<path d="M259.4 102.1h11.1v3.1h-11.1l-1.3-1.6zM285 110h2M15.9 123.6h9.4l.7 .9-.7 .8h-9.4zM16.8 121h8.5l.7 .9-.7 .9h-8.5zM36.2 121.9h2.5M36.2 124.5h2.5M38.1 139.7v2.5M43.8 121.9h2.6M43.8 124.5h2.6M51.4 121.9h2.6M51.4 124.5h2.6M79.4 121.9h2.5"/>
<path d="M79.4 124.5h2.5M84.5 129.5v2.6M133.3 137.2v2.5M149.6 133.7h12.2l.8 .9-.8 .9h-12.2l-.8-.9zM149.6 131.2h12.2l.8 .9-.8 .9h-12.2l-.7-.9zM150.8 128.7h11l.8 .8-.8 .9h-11l-.8-.9zM192.3 121h8.9l.7 .9-.7 .9h-8.9zM192.4 123.6h8.8l.7 .9-.7 .8h-8.8l-.8-.8zM212.1 121.9h2.5M212.1 124.5h2.5M232.4 121.9h2.5M232.4 124.5h2.5"/>
<path d="M232.4 127h2.5M237.5 132.1v2.5M243.8 134.6v2.6M254.1 120.4h9.9v3h-9.9l-1.4-1.5zM254.1 125.5h11v3h-11l-1.4-1.5zM10 160h2M38.1 147.3v3.1M38.1 151.9v3M48.3 147.3v3.1M48.3 151.9v3M58.4 147.3v3.1M58.4 151.9v3"/>
<path d="M68.6 147.3v3.1M68.6 151.9v3M78.7 147.3v3.1M78.7 151.9v3M88.9 147.3v3.1M88.9 151.9v3M99.1 147.3v3.1M99.1 151.9v3M120.2 143.9h12.4l.7 .9-.7 .9h-12.4l-.8-.9zM121.1 146.4h11.5l.7 .9-.7 .9h-11.5l-.8-.9zM137.2 149.9v2.5M137.2 157.5v5.1"/>
<path d="M144.8 142.2h2.5M144.8 147.3h2.5M144.8 144.8h2.5M167.6 142.2h2.6M167.6 147.3h2.6M171.4 148.6v2.5M179.1 144.8v2.5M179.1 149.9v5M243.8 142.2v5.1M249.9 154.9h5.1M260.1 154.9h2.5M264 153.4h14.8v3.1h-14.8l-1.4-1.6z"/>
<path d="M285 160h2M38.1 160v2.6M144.9 162.9h13.1l.7 .9-.7 .9h-13.1l-.8-.9zM161.3 165.1v2.5M161.3 172.7v5.1M162.6 163.8h2.5M170.2 163.8h2.5M177 166h108v32h-108zM60 198v2M110 198v2M160 198v2M177 194.5h108"/>
<path d="M177 191.5h108M177 187.5h108M177 181.5h108M182.4 186.3h.1l-.1 .1M182.4 185.5h.1l-.1 .1M184.6 183.6v.1M184.6 182.8v.1M195.5 183.6l-.1 .3M197 191.5v3M210 198v2M217.6 193.2h1.2M219.6 192.4a.36 .36 0 0 1 .6 .2 .77 .77 0 0 1-.4 1.2 1 1 0 0 1-.2-1.4z"/>
<path d="M220.8 192.3h1l-.7 1.5M229.6 185.4l.4 .1M230 186.3l-.4 .1M230.6 185.5a.37 .37 0 0 1 .7 .1v.8M230.6 184.9v1.5M260 198v2M261 191.5v6.5M270.3 195.1h.7M270.4 195.7h.4l.3 .3v.3l-.2 .2-.5 .1"/>
</g>
<path d="M152.4 33.7h25.4v21.5h-25.4z" fill="#c2c2c2" stroke="#c2c2c2" stroke-width=".13"/>
<g fill="none" stroke="#840000" stroke-width=".25">
<path d="M148.6 37.5l1.3-1.9 1.2 1.9M212.6 39.5h-1.8v1h1.8M38.7 40h5.1v1.3h-5.1zM38.7 42.5h5.1v1.3h-5.1zM38.7 45.1h5.1v1.3h-5.1zM38.7 50.2h5.1v1.2h-5.1zM38.7 55.2h5.1v1.3h-5.1zM38.7 52.7h5.1v1.3h-5.1zM38.7 47.6h5.1v1.3h-5.1zM38.7 57.8h5.1v1.3h-5.1zM89.5 55.2h5.1v1.3h-5.1zM89.5 57.8h5.1v1.3h-5.1z"/>
<path d="M89.5 52.7h5.1v1.3h-5.1zM89.5 45.1h5.1v1.3h-5.1zM89.5 50.2h5.1v1.2h-5.1zM89.5 40h5.1v1.3h-5.1zM89.5 42.5h5.1v1.3h-5.1zM89.5 47.6h5.1v1.3h-5.1zM148.6 53.3h2.5l-1.2 1.3zM165.1 40.6v2.6M165.1 45.7v2.6M167 42.5l-.6 .7h-2.6l-.6 .6M194.3 50.8h2.5l-1.2 1.3zM212.6 47.8h-1.8v1h1.8"/>
<path d="M212.6 42.7h-1.8v1h1.8M212.6 45.2h-1.8v1h1.8M212.6 50.3h-1.8v1h1.8M212.6 52.8h-1.8v1h1.8M38.7 60.3h5.1v1.3h-5.1zM38.7 62.9h5.1v1.2h-5.1zM38.7 78.1h5.1v1.3h-5.1zM38.7 65.4h5.1v1.3h-5.1zM38.7 75.6h5.1v1.2h-5.1zM38.7 67.9h5.1v1.3h-5.1zM89.5 65.4h5.1v1.3h-5.1zM89.5 62.9h5.1v1.2h-5.1z"/>
<path d="M89.5 60.3h5.1v1.3h-5.1zM89.5 78.1h5.1v1.3h-5.1zM89.5 70.5h5.1v1.3h-5.1zM89.5 73h5.1v1.3h-5.1zM89.5 67.9h5.1v1.3h-5.1zM89.5 75.6h5.1v1.2h-5.1zM158.7 62.6h5.1v1.8h-5.1zM158.7 65.2h5.1v1.7h-5.1zM158.7 67.7h5.1v1.8h-5.1zM227.3 78.7h2.6l-1.3 1.3zM38.1 90.8h5.1v1.3h-5.1zM38.1 93.3h5.1v1.3h-5.1z"/>
<path d="M90.2 82.6l1.9 1.2-1.9 1.3M101.6 95.9h5.1v1.3h-5.1zM101.6 90.8h5.1v1.3h-5.1zM168.9 93.3l1.3-1.9 1.2 1.9M246.4 98.4l1.2-1.9 1.3 1.9M38.7 106h5.1v1.3h-5.1zM38.7 108.6h5.1v1.3h-5.1zM38.7 111.1h5.1v1.3h-5.1zM38.7 103.5h5.1v1.3h-5.1zM138.4 116.8h2.6l-1.3 1.3zM168.9 116.8h2.5l-1.2 1.3zM179.1 101.6h2.5l-1.3 1.3z"/>
<path d="M206.1 106.7h1.8v5.1h-1.8zM208.7 106.7h1.7v5.1h-1.7zM233.7 109.2h2.5l-1.3 1.3zM38.7 121.3h5.1v1.3h-5.1zM38.7 123.8h5.1v1.3h-5.1zM83.2 132.1h2.5l-1.2 1.3zM132.1 139.1l1.2-1.9 1.3 1.9M236.2 134.6h2.6l-1.3 1.3zM243 137.2h1.7v5h-1.7zM36.8 141.6l1.3-1.9 1.3 1.9M136.3 152.4h1.7v5.1h-1.7zM170.2 151.1h2.5l-1.3 1.3z"/>
<path d="M177.5 147.3h3.1v.9h-3.1zM177.8 154.9h2.5l-1.2 1.3zM242.6 145.4l1.2 1.9 1.3-1.9M251.8 153.7l-1.9 1.2 1.9 1.3M255 154.1h5.1v1.7h-5.1zM36.8 162.6h2.6l-1.3 1.2zM135.9 162.6h2.5l-1.2 1.2zM160 177.8h2.6l-1.3 1.3zM160.4 167.6h1.8v5.1h-1.8zM165.1 162.9h5.1v1.8h-5.1z"/>
</g>
<g fill="none" stroke="#006464" stroke-width=".15">
<path d="M46.3 36.4h.7l-.4 .6a.33 .33 0 0 1 .4 .2v.4l-.1 .2-.5 .1M47.5 37.2h.5a.41 .41 0 0 0 .2-.4 .41 .41 0 0 0-.2-.4h-.5v1.5M47.8 37.2l.4 .7M48.7 36.4v1.5h.6M151.6 32.2h.9l-.5 .7M152.5 33.1v.1v.6M178.3 53.4h.3v.7a.58 .58 0 0 1-.6 .1 .58 .58 0 0 1-.4-.4M178.5 52.3a.6 .6 0 0 0-.9 .4M60.7 65.4h.5a.34 .34 0 0 1 .2 .3 .34 .34 0 0 1-.2 .3h-.5M63.7 70.4h.8l-.5 .5a.35 .35 0 0 1 .5 .3v.3l-.2 .1h-.6M65.6 70.4a.5 .5 0 0 0-.7 .6v.5l.2 .1 .3 .1 .2-.1 .1-.4-.1-.2-.4-.1-.3 .3M77.9 69.2h.7"/>
<path d="M46.9 87.8h.8l-.4 .5a.33 .33 0 0 1 .4 .3v.3l-.1 .2-.5 .1M48.2 88.5h.5a.41 .41 0 0 0 .2-.4 .41 .41 0 0 0-.2-.3h-.5v1.4M48.5 88.5l.4 .7M49.4 87.8v1.4h.6M60.1 81.1a.46 .46 0 0 1 .3-.5h.1a.79 .79 0 0 1 0 1.3h-.1a.46 .46 0 0 1-.3-.5M77.8 88.2h.8l-.4 .5a.35 .35 0 0 1 .4 .2v.3l-.1 .2h-.6M77.8 83.1h.8l-.4 .5a.35 .35 0 0 1 .4 .3v.3l-.1 .1-.5 .1M77.9 97.1h.7M77.9 96.2l.4-.4v1.3M78 90.9l.1-.1h.3l.2 .1a.84 .84 0 0 1-.3 1.1h-.3M78.1 85.7h.3l.2 .1a.84 .84 0 0 1-.3 1.1h-.3M78.2 98.3l-.3 .9h.8"/>
<path d="M78.5 98.8v.8M78.6 91.3l-.2 .2h-.3l-.1-.1M78.6 86.2l-.2 .3h-.3M97.6 82.4h1l-.6 .7M98.5 83.2l.1 .2-.1 .6M171.9 88.7h.9l-.5 .7M172.8 89.6v.1v.6M249.4 93.8h.9l-.5 .7M250.2 94.7l.1 .1-.1 .6M54.6 105.4h3.3M54.6 102.9h3.3M54.7 108.5l.3 1.3"/>
<path d="M55.5 103.7l-.2-.2h-.5v1.2M55.8 108.5l-.3 1.3M55.9 107.3l.4-1.3 .4 1.3M55.9 104.7l.4-1.2 .4 1.2M56.2 108.5v1.3M57.8 103.5h-.5l-.2 .2M77.8 100.9h.9l-.6 1.3M77.9 108.9l.4-.4v1.3M77.9 118.8l.2-.1 .4 .1a.34 .34 0 0 1 .1 .4l-.8 .8h.8M77.9 106.2l.2-.2 .4 .1 .1 .2-.2 .2M77.9 106.3l.2 .2M77.9 109.8h.7"/>
<path d="M78.1 116.6h.3l.2 .3v.4l-.2 .1h-.3M78.1 106.5h.3M78.1 106.5l-.2 .3M78.2 111l-.3 .9h.8M78.4 106.5l.2 .3v.3l-.2 .2h-.3l-.2-.3M78.5 111.5v.8M78.5 116.2h-.4M166.1 114.8h1M167.7 115.9h.7a.6 .6 0 0 0 .4-.5 .6 .6 0 0 0-.4-.6h-.7v2.1M40.5 136.3h.9l-.5 .7M41.3 137.2l.1 .2-.1 .6M46.3 125.9h.7l-.4 .5a.33 .33 0 0 1 .4 .3v.3l-.1 .2-.4 .1"/>
<path d="M47.6 126.6h.4a.41 .41 0 0 0 .3-.4 .41 .41 0 0 0-.3-.3h-.4v1.4M47.9 126.6l.4 .7M48.8 125.9v1.4h.5M67.4 127.8v.3v.8M68.5 127.5v1.2a.5 .5 0 0 1-.6 .5M77.9 123.9l.2-.1h.4a.34 .34 0 0 1 .1 .5l-.8 .7h.8M78 121.8l.1-.1h.3l.2 .3v.3l-.1 .1-.4 .1-.1-.1M78.5 121.2a.45 .45 0 0 0-.5 .3M230.8 133h.8M232.3 132.9l-.2 .4M233 133h1M233 131.5l.5-.6v2.1"/>
<path d="M234.6 130.9h1.1l-.6 .8a.48 .48 0 0 1 .6 .4v.5l-.2 .3-.1 .1h-.6l-.2-.2M148.1 147.1a.42 .42 0 0 1 .4-.5 .42 .42 0 0 1 .4 .5M150.2 146.8l-.1-.1a.45 .45 0 0 0-.6 .2M164.4 151.3l.6 .8M164.8 150.4a.54 .54 0 0 1 0 .8M245.7 148.1h.9l-.5 .7M246.6 149v.1v.6M247.9 152.8l-.7-.5v.9M248.1 152.3h.1h.6"/>
</g>
<g fill="#840000" stroke="#840000" stroke-width=".15">
<path d="M240.5 104.6h.5v4.1h-.5z"/>
<path d="M241.6 104.6h.5v4.1h-.5z"/>
<path d="M173.2 94.5h.5v4.1h-.5z"/>
<path d="M174.2 94.5h.6v4.1h-.6z"/>
<path d="M177.4 149h3.3v.9h-3.3z"/>
<path d="M97 151.4h4.1v.5h-4.1z"/>
<path d="M97 150.4h4.1v.5h-4.1z"/>
<path d="M86.9 151.4h4v.5h-4z"/>
<path d="M86.9 150.4h4v.5h-4z"/>
<path d="M36.1 151.4h4v.5h-4z"/>
<path d="M36.1 150.4h4v.5h-4z"/>
<path d="M76.7 151.4h4.1v.5h-4.1z"/>
<path d="M76.7 150.4h4.1v.5h-4.1z"/>
<path d="M66.5 151.4h4.1v.5h-4.1z"/>
<path d="M66.5 150.4h4.1v.5h-4.1z"/>
<path d="M46.2 151.4h4.1v.5h-4.1z"/>
<path d="M46.2 150.4h4.1v.5h-4.1z"/>
<path d="M56.4 151.4h4.1v.5h-4.1z"/>
<path d="M56.4 150.4h4.1v.5h-4.1z"/>
</g>
<path d="M52.9 55.5h.8M80.9 55.5h.7M52.9 78.3h.8M80.9 75.8h.7M96.1 73.3h.5M96.1 68.2h.5M37.6 111.4h.5M80.9 108.8h.7M37.6 121.6h.5" fill="none" stroke="#a90000" stroke-width=".15"/>
<g fill="#ffffc2" stroke="#ffffc2" stroke-width=".13">
<path d="M144.8 99.1h20.3v15.2h-20.3z"/>
<path d="M214.6 114.3h17.8v15.2h-17.8z"/>
<path d="M154.9 38.1h20.4v12.7h-20.4z"/>
<path d="M54 38.1h25.4v88.9h-25.4z"/>
</g>
<path d="M54 38.1h25.4v88.9h-25.4zM154.9 38.1h20.4v12.7h-20.4zM144.8 99.1h20.3v15.2h-20.3zM214.6 114.3h17.8v15.2h-17.8z" fill="none" stroke="#840000" stroke-width=".4"/>
<path d="M147.3 139.7h20.3v10.2h-20.3z" fill="none" stroke="#840000" stroke-width=".41"/>
<path d="M165.1 43.2l1.3 2.5h-2.6z" fill="#840000" stroke="#840000" stroke-width=".25"/>
<path d="M236.2 58.4v2.6" fill="none" stroke="#a1a1a1" stroke-width=".41"/>
<path d="M236.2 58.4h10.2v17.8h-10.2z" fill="none" stroke="#a1a1a1" stroke-width=".4"/>
<path d="M231.1 61h5.1M231.1 63.5h5.1M231.1 66h5.1M231.1 68.6h5.1M231.1 71.1h5.1M231.1 73.7h5.1" fill="none" stroke="#a1a1a1" stroke-width=".15"/>
<path d="M236.9 64.8h5.4M237.8 65.6l-.3-.2h-.5v1.2M238.9 65.4h-.6v1.2M240.1 65.4h-.5l-.2 .2M241.3 65.4h-.6v1.2M241.6 65.4h.8M242 65.4v1.2" fill="none" stroke="#989898" stroke-width=".15"/>
<path d="M231.1 58.2l15.5 18.2M246.6 58.2l-15.5 18.2" fill="none" stroke="#eb3a3d" stroke-width=".46"/>
<g fill="none" stroke="#840084" stroke-width=".15">
<path d="M71.5 26.9l.3 .1 .1 .2v.5l-.2 .1h-.2M72.4 26.5v1.1l.1 .2M72.9 27.4l.5-.2v-.2l-.4-.1-.1 .2v.6h.5M94 26.5h.6M94.9 26.5v1.3h.6M96.7 27l-.1 .2v.3l.1 .2M99 26.5l.3 1.3M110.6 27.1l.1 .1-.1 .5M214 95.7h.8M223.6 94.5l.4 .1v.1v1M230.2 95.7h.8M154.8 119.7v.2"/>
<path d="M154.8 119.1v.1M63.7 131.1h.4v.8M64.6 131.8v.1M64.6 131.1v.2M68.7 130.7h.7l-.4 .4M69.3 131.3v.5M78.1 131.9h.6M78.3 130.8l-.2 .2M82 131.1v.8M82.4 131.1l-.4 .1M261.9 139.8h.4v.8M262.9 139.8v.1"/>
<path d="M276.3 139.3h.6M279.3 139.7v.9M279.6 139.7l-.3 .1M51.8 140.5v1.1a.27 .27 0 0 1-.4 .1M51.8 140.5h-.3l-.2 .2v.4l.1 .1h.4M61.1 140.5h-.3a.22 .22 0 0 0-.1 .2 .22 .22 0 0 0 .1 .2h.2a.22 .22 0 0 1 .1 .2 .22 .22 0 0 1-.1 .2l-.3-.1M63.6 142.5h.5M67.1 142.5v1.3M67.1 143.3l.3 .1M67.4 142.5l-.3 .1M262.9 140.4v.2M276.3 140.4l.1 .2"/>
</g>
<path d="M145.9 154.4l-.2 .9-.2-.6M146.3 154.4v.9M146.3 154.5a.27 .27 0 0 1 .4 0l.1 .8M154 156.5v.8M154.3 156.5h-.2l-.1 .2M158.4 154.4h.4M158.6 154v1.1v.1l.2 .1" fill="none" stroke="#0000c2" stroke-width=".15"/>
<path d="M59.4 33.3h.4M59.5 32.9v1.1l.1 .1h.2" fill="none" stroke="#f00" stroke-width=".15"/>
<path d="M30.8 21.6l-.2-.1a.39 .39 0 0 1-.1-.3 .39 .39 0 0 1 .3-.3h.4a.39 .39 0 0 1 .1 .4 .39 .39 0 0 1-.2 .3M30.8 21.6l-.2 .1a.58 .58 0 0 0 .2 .9h.4a.58 .58 0 0 0-.1-1M30.8 21.6h.3M141.7 20.9v1.5l.2 .2M142.3 20.6a2.31 2.31 0 0 1 0 2.7M152.4 33.7h25.4v21.5h-25.4z" fill="none" stroke="#c2c2c2" stroke-width=".15"/>
<g fill="none" stroke="#f0f" stroke-width=".15">
<path d="M205.6 16.6h.4a.62 .62 0 0 1 .3 .9l-1.1 1.3h1.2M210.8 21h2.6v15.2h-2.6zM252.1 53.9l.2 .3 .2 .1h.3l.2-.1M253 53l-.2-.1h-.3l-.3 .2-.1 .2M253.5 52.9h.8M253.8 52.2v1.8l.1 .2 .4 .1M272 52.2l1.3 2.1M273.3 52.2l-1.3 2.1M251.2 63.8h7.6v5h-7.6z"/>
<circle cx="212.1" cy="27.3" r=".63"/>
<circle cx="212.1" cy="32.4" r=".63"/>
<circle cx="212.1" cy="29.8" r=".63"/>
<circle cx="212.1" cy="22.2" r=".63"/>
<circle cx="212.1" cy="24.8" r=".63"/>
<circle cx="212.1" cy="34.9" r=".63"/>
<circle cx="252.5" cy="67.6" r=".63"/>
<circle cx="252.5" cy="65" r=".63"/>
<circle cx="255" cy="65" r=".63"/>
<circle cx="255" cy="67.6" r=".63"/>
<circle cx="257.6" cy="65" r=".63"/>
<circle cx="257.6" cy="67.6" r=".63"/>
</g>
<path d="M116.8 14v69.8M116.8 83.8h69.9M116.8 83.8v43.2M186.7 83.8h95.2M116.8 127v67.3M116.8 127h69.9M186.7 127v-43.2M186.7 163.8v-36.8" fill="none" stroke="#c2c2c2" stroke-width=".15" stroke-dasharray="1.7 .6"/>
<g fill="none" stroke="#009600" stroke-width=".15">
<path d="M149.9 38.1v2.5h2.5M26 50.8h10.2M26 53.3h10.2M26 55.9h10.2M26 58.4h10.2M26 48.3h10.2M26 45.7h10.2M26 40.6h10.2M26 43.2h10.2M46.4 50.8h5M46.4 53.3h5M46.4 55.9h5"/>
<path d="M46.4 58.4h5M46.4 48.3h5M46.4 45.7h5M46.4 40.6h5M46.4 43.2h5M81.9 50.8h5.1M81.9 53.3h5.1M81.9 55.9h5.1M81.9 58.4h5.1M81.9 48.3h5.1M81.9 45.7h5.1M81.9 40.6h5.1"/>
<path d="M81.9 43.2h5.1M97.2 50.8h9.5M97.2 53.3h9.5M97.2 55.9h9.5M97.2 58.4h9.5M97.2 48.3h9.5M97.2 45.7h9.5M97.2 40.6h9.5M97.2 43.2h9.5M152.4 48.3h-2.5v2.5M177.8 48.3h2.5v17.7M177.8 45.7h5.1v25.4"/>
<path d="M177.8 40.6h10.2v22.9M177.8 43.2h7.6v25.4M208.3 48.3h-7.6v15.2M208.3 50.8h-2.6v15.2M208.3 53.3h-5.1v17.8M208.3 45.7h-12.7v2.6M208.3 43.2h-10.2v25.4M26 66h10.2M26 78.7h10.2M26 63.5h10.2M26 61h10.2M26 76.2h10.2"/>
<path d="M26 68.6h10.2M46.4 66h5M46.4 63.5h5M46.4 61h5M46.4 76.2h5M46.4 68.6h5M48.3 78.7h3.1M81.9 66h5.1M81.9 78.7h5.1M81.9 63.5h5.1M81.9 61h5.1M81.9 76.2h5.1"/>
<path d="M81.9 68.6h5.1M81.9 71.1h5.1M81.9 73.7h5.1M97.2 66h9.5M97.2 78.7h9.5M97.2 63.5h9.5M97.2 61h9.5M97.2 76.2h9.5M97.2 68.6h9.5M97.2 71.1h9.5M97.2 73.7h9.5M138.4 66h17.8"/>
<path d="M138.4 63.5h17.8M138.4 68.6h17.8M138.4 71.1h85.1v2.6h7.6M166.4 66h64.7M166.4 63.5h64.7M166.4 68.6h64.7M231.1 71.1h-2.5v5.1M26 91.4h9.6M26 94h9.6M45.7 91.4h5.7M45.7 94h5.7M81.9 96.5h2.6"/>
<path d="M81.9 91.4h2.6M81.9 99.1h2.6M81.9 88.9h2.6M81.9 83.8h7.6M81.9 86.4h2.6M84.5 83.8v17.8h-2.6M170.2 94v7.6h-2.6M177.8 96.5h2.5v2.6M247.6 99.1v7.6h-2.5M26 111.8h10.2M26 109.2h10.2M26 106.7h10.2"/>
<path d="M26 104.1h10.2M46.4 109.2h5M46.4 106.7h5M46.4 104.1h5M47.6 111.8h3.8M81.9 111.8h2.6M81.9 106.7h2.6v22.8M81.9 119.4h2.6M81.9 109.2h2.6M81.9 116.8h2.6M132.1 101.6h10.1M132.1 104.1h10.1"/>
<path d="M139.7 111.8h2.5M142.2 106.7h-2.5v7.6M167.6 111.8h2.6M167.6 109.2h2.6M167.6 106.7h2.6v7.6M200.7 116.8h11.4M201.9 119.4h10.2M207 114.3v10.2M209.5 101.6v2.5M209.5 114.3v5.1M234.9 116.8h5.1v17.8h12.7M247.6 101.6h-40.6v2.5"/>
<path d="M252.7 116.8h-9.5v2.6h-8.3M26 124.5h10.2M26 121.9h10.2M46.4 121.9h5M48.3 124.5h3.1M81.9 124.5h2.6M81.9 121.9h2.6M133.3 139.7v2.5h11.5M201.9 124.5h10.2M201.9 121.9h10.2M234.9 124.5h8.3v2.5h9.5M234.9 121.9h17.8"/>
<path d="M234.9 127h2.6v5.1M38.1 142.2v5.1M38.1 154.9v5.1M38.1 144.8h61v2.5M48.3 144.8v2.5M48.3 154.9v2.6M58.4 144.8v2.5M58.4 154.9v2.6M68.6 144.8v2.5M68.6 154.9v2.6M78.7 144.8v2.5M78.7 154.9v2.6"/>
<path d="M88.9 144.8v2.5M88.9 154.9v2.6M99.1 154.9v2.6h-61M133.3 144.8h11.5M133.3 147.3h11.5M137.2 144.8v5.1M170.2 142.2h8.9v2.6M170.2 147.3h1.2v1.3M174 142.2v21.6h-1.3M158.7 163.8h3.9M161.3 163.8v1.3"/>
</g>
<g fill="none" stroke="#000084" stroke-width=".15">
<path d="M207.7 39.4l1.2 1.2M208.9 39.4l-1.2 1.2M50.8 70.5l1.2 1.2M52 70.5l-1.2 1.2M230.5 60.4l1.2 1.2M231.7 60.4l-1.2 1.2M98.5 95.9l1.2 1.2M98.5 90.8l1.2 1.2M99.7 95.9l-1.2 1.2M99.7 90.8l-1.2 1.2M108.6 90.8l1.2 1.2M108.6 95.9l1.2 1.2"/>
<path d="M109.8 90.8l-1.2 1.2M109.8 95.9l-1.2 1.2"/>
</g>
<g fill="#009600" stroke="#009600" stroke-width=".15">
<circle cx="84.5" cy="88.9" r=".46"/>
<circle cx="84.5" cy="96.5" r=".46"/>
<circle cx="84.5" cy="86.4" r=".46"/>
<circle cx="84.5" cy="91.4" r=".46"/>
<circle cx="84.5" cy="83.8" r=".46"/>
<circle cx="84.5" cy="124.5" r=".46"/>
<circle cx="88.9" cy="144.8" r=".46"/>
<circle cx="188" cy="63.5" r=".46"/>
<circle cx="180.3" cy="66" r=".46"/>
<circle cx="185.4" cy="68.6" r=".46"/>
<circle cx="198.1" cy="68.6" r=".46"/>
<circle cx="182.9" cy="71.1" r=".46"/>
<circle cx="209.5" cy="119.4" r=".46"/>
<circle cx="209.5" cy="101.6" r=".46"/>
<circle cx="207" cy="124.5" r=".46"/>
<circle cx="247.6" cy="101.6" r=".46"/>
<circle cx="174" cy="142.2" r=".46"/>
<circle cx="139.7" cy="111.8" r=".46"/>
<circle cx="161.3" cy="163.8" r=".46"/>
<circle cx="170.2" cy="109.2" r=".46"/>
<circle cx="170.2" cy="111.8" r=".46"/>
<circle cx="170.2" cy="96.5" r=".46"/>
<circle cx="137.2" cy="144.8" r=".46"/>
<circle cx="205.7" cy="66" r=".46"/>
<circle cx="200.7" cy="63.5" r=".46"/>
<circle cx="203.2" cy="71.1" r=".46"/>
<circle cx="243.8" cy="134.6" r=".46"/>
<circle cx="58.4" cy="157.5" r=".46"/>
<circle cx="68.6" cy="157.5" r=".46"/>
<circle cx="68.6" cy="144.8" r=".46"/>
<circle cx="88.9" cy="157.5" r=".46"/>
<circle cx="78.7" cy="157.5" r=".46"/>
<circle cx="78.7" cy="144.8" r=".46"/>
<circle cx="84.5" cy="119.4" r=".46"/>
<circle cx="84.5" cy="121.9" r=".46"/>
<circle cx="84.5" cy="109.2" r=".46"/>
<circle cx="84.5" cy="99.1" r=".46"/>
<circle cx="84.5" cy="116.8" r=".46"/>
<circle cx="84.5" cy="111.8" r=".46"/>
<circle cx="38.1" cy="144.8" r=".46"/>
<circle cx="58.4" cy="144.8" r=".46"/>
<circle cx="48.3" cy="144.8" r=".46"/>
<circle cx="48.3" cy="157.5" r=".46"/>
<circle cx="38.1" cy="157.5" r=".46"/>
</g>
<use href="#words"/>
</svg>
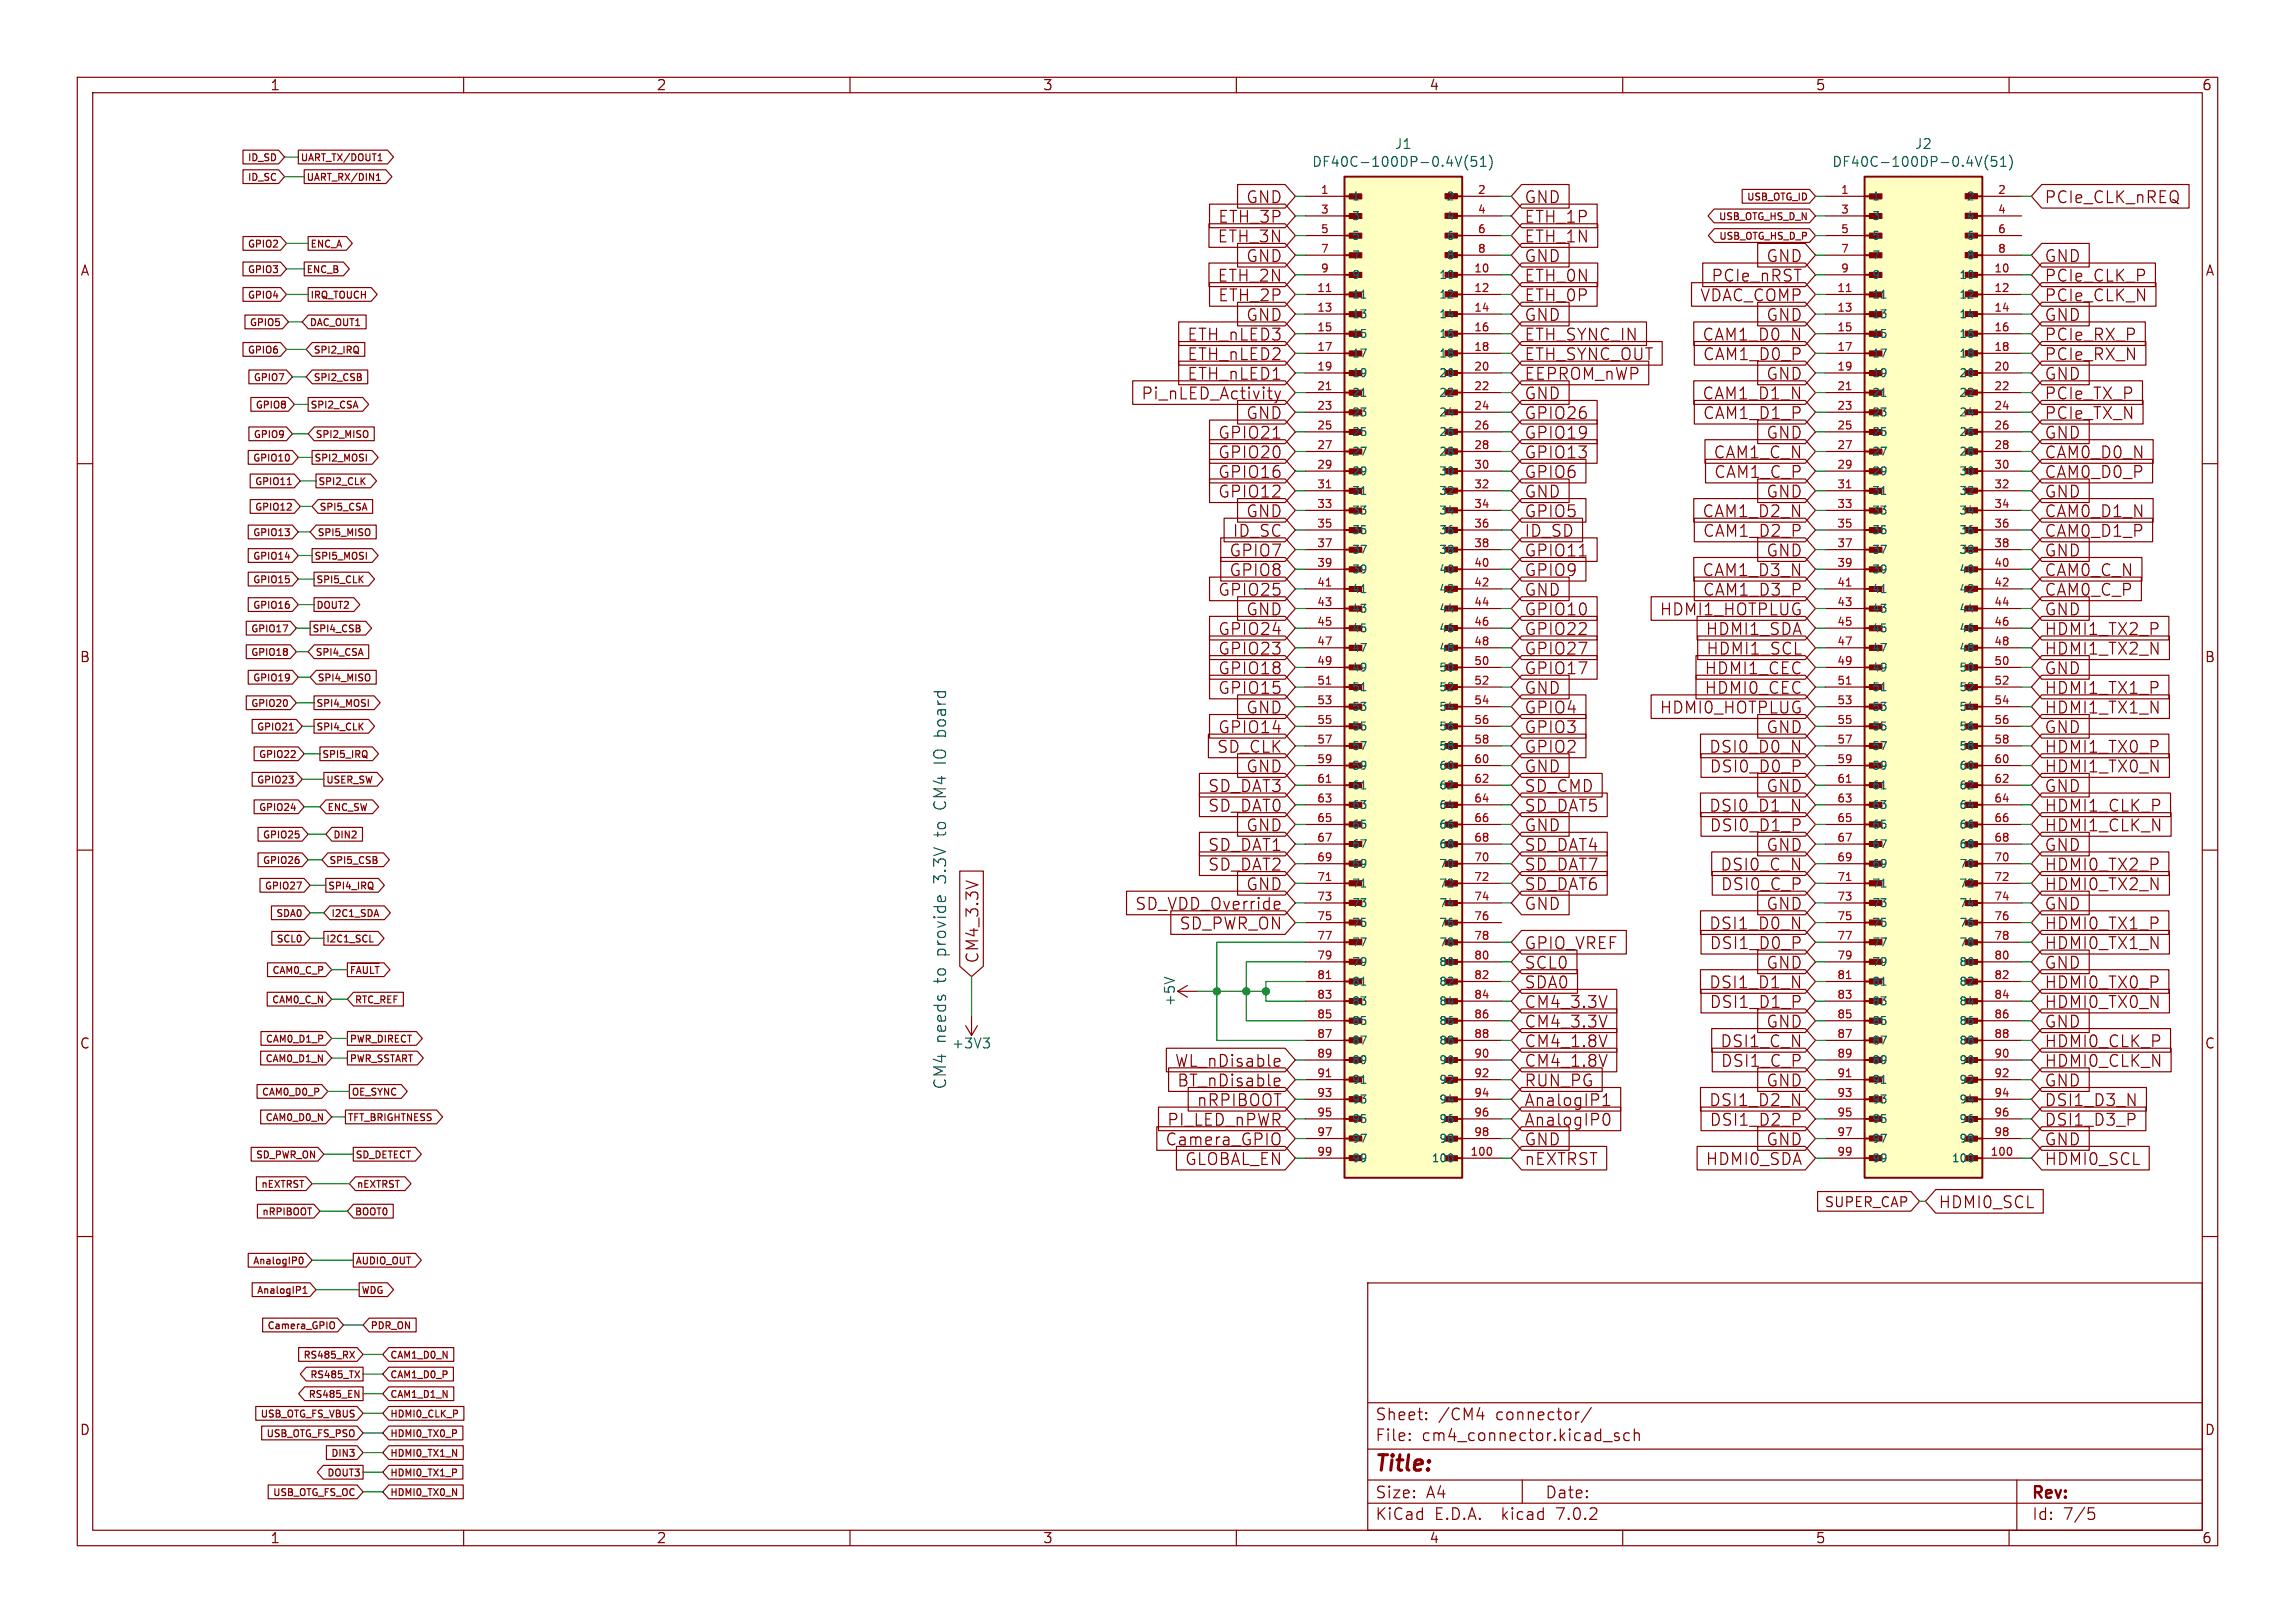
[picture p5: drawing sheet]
<svg xmlns="http://www.w3.org/2000/svg" width="297mm" height="210mm" viewBox="0 0 297 210" stroke-linecap="round" stroke-linejoin="round" font-family="sans-serif">
<defs><g id="words">
<text font-size="2.8" fill="#840000" x="178" y="190.8">Title:</text>
<g font-size="2.1" fill="#840000">
<text x="157.6" y="29">ETH_3P</text>
<text x="161.2" y="26.5">GND</text>
<text x="197.3" y="29">ETH_1P</text>
<text x="197.3" y="26.5">GND</text>
<text x="264.6" y="26.5">PCIe_CLK_nREQ</text>
<text x="157.5" y="31.5">ETH_3N</text>
<text x="161.2" y="34.1">GND</text>
<text x="197.3" y="31.5">ETH_1N</text>
<text x="197.3" y="34.1">GND</text>
<text x="228.5" y="34.1">GND</text>
<text x="264.6" y="34.1">GND</text>
<text x="157.5" y="36.6">ETH_2N</text>
<text x="157.6" y="39.2">ETH_2P</text>
<text x="161.2" y="41.7">GND</text>
<text x="197.3" y="39.2">ETH_0P</text>
<text x="197.3" y="36.6">ETH_0N</text>
<text x="197.3" y="41.7">GND</text>
<text x="220" y="39.2">VDAC_COMP</text>
<text x="221.4" y="36.6">PCIe_nRST</text>
<text x="228.5" y="41.7">GND</text>
<text x="264.6" y="39.2">PCIe_CLK_N</text>
<text x="264.6" y="36.6">PCIe_CLK_P</text>
<text x="264.6" y="41.7">GND</text>
<text x="153.6" y="46.8">ETH_nLED2</text>
<text x="153.6" y="44.2">ETH_nLED3</text>
<text x="197.3" y="46.8">ETH_SYNC_OUT</text>
<text x="197.3" y="44.2">ETH_SYNC_IN</text>
<text x="220.2" y="44.2">CAM1_D0_N</text>
<text x="220.3" y="46.8">CAM1_D0_P</text>
<text x="264.6" y="44.2">PCIe_RX_P</text>
<text x="264.6" y="46.8">PCIe_RX_N</text>
<text x="147.6" y="51.9">Pi_nLED_Activity</text>
<text x="153.6" y="49.3">ETH_nLED1</text>
<text x="197.3" y="51.9">GND</text>
<text x="197.3" y="49.3">EEPROM_nWP</text>
<text x="220.2" y="51.9">CAM1_D1_N</text>
<text x="228.5" y="49.3">GND</text>
<text x="264.6" y="49.3">GND</text>
<text x="264.6" y="51.9">PCIe_TX_P</text>
<text x="157.6" y="59.5">GPIO20</text>
<text x="157.6" y="56.9">GPIO21</text>
<text x="161.2" y="54.4">GND</text>
<text x="197.3" y="56.9">GPIO19</text>
<text x="197.3" y="59.5">GPIO13</text>
<text x="197.3" y="54.4">GPIO26</text>
<text x="220.3" y="54.4">CAM1_D1_P</text>
<text x="221.7" y="59.5">CAM1_C_N</text>
<text x="228.5" y="56.9">GND</text>
<text x="264.6" y="56.9">GND</text>
<text x="264.6" y="54.4">PCIe_TX_N</text>
<text x="264.6" y="59.5">CAM0_D0_N</text>
<text x="157.6" y="62">GPIO16</text>
<text x="157.6" y="64.6">GPIO12</text>
<text x="197.3" y="62">GPIO6</text>
<text x="197.3" y="64.6">GND</text>
<text x="221.8" y="62">CAM1_C_P</text>
<text x="228.5" y="64.6">GND</text>
<text x="264.6" y="64.6">GND</text>
<text x="264.6" y="62">CAM0_D0_P</text>
<text x="159.5" y="69.6">ID_SC</text>
<text x="161.2" y="67.1">GND</text>
<text x="197.3" y="69.6">ID_SD</text>
<text x="197.3" y="67.1">GPIO5</text>
<text x="220.2" y="67.1">CAM1_D2_N</text>
<text x="220.3" y="69.6">CAM1_D2_P</text>
<text x="264.6" y="67.1">CAM0_D1_N</text>
<text x="264.6" y="69.6">CAM0_D1_P</text>
<text x="157.6" y="77.3">GPIO25</text>
<text x="159" y="74.7">GPIO8</text>
<text x="159" y="72.2">GPIO7</text>
<text x="197.3" y="74.7">GPIO9</text>
<text x="197.3" y="72.2">GPIO11</text>
<text x="197.3" y="77.3">GND</text>
<text x="220.2" y="74.7">CAM1_D3_N</text>
<text x="220.3" y="77.3">CAM1_D3_P</text>
<text x="228.5" y="72.2">GND</text>
<text x="264.6" y="72.2">GND</text>
<text x="264.6" y="74.7">CAM0_C_N</text>
<text x="264.6" y="77.3">CAM0_C_P</text>
<text x="157.6" y="82.3">GPIO24</text>
<text x="161.2" y="79.8">GND</text>
<text x="197.3" y="82.3">GPIO22</text>
<text x="197.3" y="79.8">GPIO10</text>
<text x="214.7" y="79.8">HDMI1_HOTPLUG</text>
<text x="220.7" y="82.3">HDMI1_SDA</text>
<text x="264.6" y="82.3">HDMI1_TX2_P</text>
<text x="264.6" y="79.8">GND</text>
<text x="157.6" y="84.9">GPIO23</text>
<text x="157.6" y="87.4">GPIO18</text>
<text x="157.6" y="90">GPIO15</text>
<text x="197.3" y="84.9">GPIO27</text>
<text x="197.3" y="87.4">GPIO17</text>
<text x="197.3" y="90">GND</text>
<text x="220.5" y="90">HDMI0_CEC</text>
<text x="220.5" y="87.4">HDMI1_CEC</text>
<text x="220.7" y="84.9">HDMI1_SCL</text>
<text x="264.6" y="87.4">GND</text>
<text x="264.6" y="84.9">HDMI1_TX2_N</text>
<text x="264.6" y="90">HDMI1_TX1_P</text>
<text x="157.6" y="95">GPIO14</text>
<text x="161.2" y="92.5">GND</text>
<text x="197.3" y="95">GPIO3</text>
<text x="197.3" y="92.5">GPIO4</text>
<text x="214.7" y="92.5">HDMI0_HOTPLUG</text>
<text x="228.5" y="95">GND</text>
<text x="264.6" y="92.5">HDMI1_TX1_N</text>
<text x="264.6" y="95">GND</text>
<text x="157.4" y="97.6">SD_CLK</text>
<text x="161.2" y="100.1">GND</text>
<text x="197.3" y="100.1">GND</text>
<text x="197.3" y="97.6">GPIO2</text>
<text x="221.1" y="97.6">DSI0_D0_N</text>
<text x="221.2" y="100.1">DSI0_D0_P</text>
<text x="264.6" y="100.1">HDMI1_TX0_N</text>
<text x="264.6" y="97.6">HDMI1_TX0_P</text>
<text x="156.3" y="105.2">SD_DAT0</text>
<text x="156.3" y="102.7">SD_DAT3</text>
<text x="161.2" y="107.7">GND</text>
<text x="197.3" y="102.7">SD_CMD</text>
<text x="197.3" y="105.2">SD_DAT5</text>
<text x="197.3" y="107.7">GND</text>
<text x="221.1" y="105.2">DSI0_D1_N</text>
<text x="221.2" y="107.7">DSI0_D1_P</text>
<text x="228.5" y="102.7">GND</text>
<text x="264.6" y="107.7">HDMI1_CLK_N</text>
<text x="264.6" y="105.2">HDMI1_CLK_P</text>
<text x="264.6" y="102.7">GND</text>
<text x="156.3" y="112.8">SD_DAT2</text>
<text x="156.3" y="110.3">SD_DAT1</text>
<text x="197.3" y="112.8">SD_DAT7</text>
<text x="197.3" y="110.3">SD_DAT4</text>
<text x="222.6" y="112.8">DSI0_C_N</text>
<text x="228.5" y="110.3">GND</text>
<text x="264.6" y="112.8">HDMI0_TX2_P</text>
<text x="264.6" y="110.3">GND</text>
<text x="146.8" y="117.9">SD_VDD_Override</text>
<text x="161.2" y="115.4">GND</text>
<text x="197.3" y="115.4">SD_DAT6</text>
<text x="197.3" y="117.9">GND</text>
<text x="222.6" y="115.4">DSI0_C_P</text>
<text x="228.5" y="117.9">GND</text>
<text x="264.6" y="115.4">HDMI0_TX2_N</text>
<text x="264.6" y="117.9">GND</text>
<text x="126.8" y="124.7" transform="rotate(-90 126.8 124.7)">CM4_3.3V</text>
<text x="152.6" y="120.4">SD_PWR_ON</text>
<text x="197.3" y="123">GPIO_VREF</text>
<text x="197.3" y="125.5">SCL0</text>
<text x="221.1" y="120.4">DSI1_D0_N</text>
<text x="221.2" y="123">DSI1_D0_P</text>
<text x="228.5" y="125.5">GND</text>
<text x="264.6" y="123">HDMI0_TX1_N</text>
<text x="264.6" y="120.4">HDMI0_TX1_P</text>
<text x="264.6" y="125.5">GND</text>
<text x="197.3" y="128.1">SDA0</text>
<text x="197.3" y="130.6">CM4_3.3V</text>
<text x="221.1" y="128.1">DSI1_D1_N</text>
<text x="221.2" y="130.6">DSI1_D1_P</text>
<text x="264.6" y="130.6">HDMI0_TX0_N</text>
<text x="264.6" y="128.1">HDMI0_TX0_P</text>
<text x="197.3" y="135.7">CM4_1.8V</text>
<text x="197.3" y="133.1">CM4_3.3V</text>
<text x="222.6" y="135.7">DSI1_C_N</text>
<text x="228.5" y="133.1">GND</text>
<text x="264.6" y="133.1">GND</text>
<text x="264.6" y="135.7">HDMI0_CLK_P</text>
<text x="152" y="138.2">WL_nDisable</text>
<text x="152.3" y="140.8">BT_nDisable</text>
<text x="154.8" y="143.3">nRPIBOOT</text>
<text x="197.3" y="140.8">RUN_PG</text>
<text x="197.3" y="138.2">CM4_1.8V</text>
<text x="197.3" y="143.3">AnalogIP1</text>
<text x="221.1" y="143.3">DSI1_D2_N</text>
<text x="222.6" y="138.2">DSI1_C_P</text>
<text x="228.5" y="140.8">GND</text>
<text x="264.6" y="138.2">HDMI0_CLK_N</text>
<text x="264.6" y="140.8">GND</text>
<text x="264.6" y="143.3">DSI1_D3_N</text>
<text x="150.8" y="148.4">Camera_GPIO</text>
<text x="151" y="145.8">PI_LED_nPWR</text>
<text x="197.3" y="148.4">GND</text>
<text x="197.3" y="145.8">AnalogIP0</text>
<text x="221.2" y="145.8">DSI1_D2_P</text>
<text x="228.5" y="148.4">GND</text>
<text x="264.6" y="145.8">DSI1_D3_P</text>
<text x="264.6" y="148.4">GND</text>
<text x="153.3" y="150.9">GLOBAL_EN</text>
<text x="197.3" y="150.9">nEXTRST</text>
<text x="220.7" y="150.9">HDMI0_SDA</text>
<text x="264.6" y="150.9">HDMI0_SCL</text>
<text x="250.9" y="156.5">HDMI0_SCL</text>
<text x="178" y="183.9">Sheet:</text>
<text x="186.2" y="183.9">/CM4</text>
<text x="193.6" y="183.9">connector/</text>
<text x="178" y="186.6">File:</text>
<text x="184" y="186.6">cm4_connector.kicad_sch</text>
<text x="178" y="196.8">KiCad</text>
<text x="178" y="194">Size:</text>
<text x="184.6" y="194">A4</text>
<text x="185.7" y="196.8">E.D.A.</text>
<text x="194.4" y="196.8">kicad</text>
<text x="200" y="194">Date:</text>
<text x="201.5" y="196.8">7.0.2</text>
<text x="263" y="194.2">Rev:</text>
<text x="263" y="196.8">Id:</text>
<text x="267" y="196.8">7/5</text>
</g>
<g font-size="2.1" fill="#0000c2">
<text x="122.6" y="104.5" transform="rotate(-90 122.6 104.5)">CM4 IO board</text>
<text x="122.6" y="108" transform="rotate(-90 122.6 108)">to</text>
<text x="122.6" y="114.2" transform="rotate(-90 122.6 114.2)">3.3V</text>
<text x="122.6" y="123.7" transform="rotate(-90 122.6 123.7)">provide</text>
<text x="122.6" y="127.2" transform="rotate(-90 122.6 127.2)">to</text>
<text x="122.6" y="141" transform="rotate(-90 122.6 141)">CM4 needs</text>
</g>
<g font-size="1.8" fill="#840000">
<text x="35" y="11.8">1</text>
<text x="85" y="11.8">2</text>
<text x="135" y="11.8">3</text>
<text x="185" y="11.8">4</text>
<text x="235" y="11.8">5</text>
<text x="285" y="11.8">6</text>
<text x="10.4" y="35.8">A</text>
<text x="285.4" y="35.8">A</text>
<text x="10.3" y="85.8">B</text>
<text x="285.3" y="85.8">B</text>
<text x="10.3" y="135.8">C</text>
<text x="285.3" y="135.8">C</text>
<text x="236" y="156.4">SUPER_CAP</text>
<text x="10.3" y="185.8">D</text>
<text x="285.3" y="185.8">D</text>
<text x="35" y="199.8">1</text>
<text x="85" y="199.8">2</text>
<text x="135" y="199.8">3</text>
<text x="185" y="199.8">4</text>
<text x="235" y="199.8">5</text>
<text x="285" y="199.8">6</text>
</g>
<g font-size="1.8" fill="#006464">
<text x="169.8" y="21.8">DF40C-100DP-0.4V(51)</text>
<text x="180.5" y="19.4">J1</text>
<text x="237.1" y="21.8">DF40C-100DP-0.4V(51)</text>
<text x="247.8" y="19.4">J2</text>
<text x="152.2" y="130.3" transform="rotate(-90 152.2 130.3)">+5V</text>
<text x="123.1" y="135.8">+3V3</text>
</g>
<g font-size="1.4" fill="#a90000">
<text x="170.9" y="25.1">1</text>
<text x="170.9" y="27.7">3</text>
<text x="191.2" y="25.1">2</text>
<text x="191.2" y="27.7">4</text>
<text x="238.2" y="25.1">1</text>
<text x="238.2" y="27.7">3</text>
<text x="258.5" y="25.1">2</text>
<text x="258.5" y="27.7">4</text>
<text x="170.9" y="30.2">5</text>
<text x="170.9" y="32.8">7</text>
<text x="170.9" y="35.3">9</text>
<text x="190.7" y="35.3">10</text>
<text x="191.2" y="30.2">6</text>
<text x="191.2" y="32.8">8</text>
<text x="238.2" y="30.2">5</text>
<text x="238.2" y="32.8">7</text>
<text x="238.2" y="35.3">9</text>
<text x="258" y="35.3">10</text>
<text x="258.5" y="30.2">6</text>
<text x="258.5" y="32.8">8</text>
<text x="170.4" y="37.8">11</text>
<text x="170.4" y="40.4">13</text>
<text x="190.7" y="37.8">12</text>
<text x="190.7" y="40.4">14</text>
<text x="237.7" y="37.8">11</text>
<text x="237.7" y="40.4">13</text>
<text x="258" y="37.8">12</text>
<text x="258" y="40.4">14</text>
<text x="170.4" y="42.9">15</text>
<text x="170.4" y="45.5">17</text>
<text x="190.7" y="42.9">16</text>
<text x="190.7" y="45.5">18</text>
<text x="237.7" y="42.9">15</text>
<text x="237.7" y="45.5">17</text>
<text x="258" y="42.9">16</text>
<text x="258" y="45.5">18</text>
<text x="170.4" y="48">19</text>
<text x="170.4" y="50.5">21</text>
<text x="170.4" y="53.1">23</text>
<text x="190.7" y="48">20</text>
<text x="190.7" y="50.5">22</text>
<text x="190.7" y="53.1">24</text>
<text x="237.7" y="48">19</text>
<text x="237.7" y="50.5">21</text>
<text x="237.7" y="53.1">23</text>
<text x="258" y="48">20</text>
<text x="258" y="50.5">22</text>
<text x="258" y="53.1">24</text>
<text x="170.4" y="55.6">25</text>
<text x="170.4" y="58.2">27</text>
<text x="190.7" y="55.6">26</text>
<text x="190.7" y="58.2">28</text>
<text x="237.7" y="55.6">25</text>
<text x="237.7" y="58.2">27</text>
<text x="258" y="55.6">26</text>
<text x="258" y="58.2">28</text>
<text x="170.4" y="60.7">29</text>
<text x="170.4" y="63.2">31</text>
<text x="170.4" y="65.8">33</text>
<text x="190.7" y="60.7">30</text>
<text x="190.7" y="63.2">32</text>
<text x="190.7" y="65.8">34</text>
<text x="237.7" y="60.7">29</text>
<text x="237.7" y="63.2">31</text>
<text x="237.7" y="65.8">33</text>
<text x="258" y="60.7">30</text>
<text x="258" y="63.2">32</text>
<text x="258" y="65.8">34</text>
<text x="170.4" y="68.3">35</text>
<text x="170.4" y="70.9">37</text>
<text x="190.7" y="68.3">36</text>
<text x="190.7" y="70.9">38</text>
<text x="237.7" y="68.3">35</text>
<text x="237.7" y="70.9">37</text>
<text x="258" y="68.3">36</text>
<text x="258" y="70.9">38</text>
<text x="170.4" y="73.4">39</text>
<text x="170.4" y="75.9">41</text>
<text x="190.7" y="73.4">40</text>
<text x="190.7" y="75.9">42</text>
<text x="237.7" y="73.4">39</text>
<text x="237.7" y="75.9">41</text>
<text x="258" y="73.4">40</text>
<text x="258" y="75.9">42</text>
<text x="170.4" y="78.5">43</text>
<text x="170.4" y="81">45</text>
<text x="170.4" y="83.6">47</text>
<text x="190.7" y="78.5">44</text>
<text x="190.7" y="81">46</text>
<text x="190.7" y="83.6">48</text>
<text x="237.7" y="78.5">43</text>
<text x="237.7" y="81">45</text>
<text x="237.7" y="83.6">47</text>
<text x="258" y="78.5">44</text>
<text x="258" y="81">46</text>
<text x="258" y="83.6">48</text>
<text x="170.4" y="86.1">49</text>
<text x="170.4" y="88.6">51</text>
<text x="190.7" y="86.1">50</text>
<text x="190.7" y="88.6">52</text>
<text x="237.7" y="86.1">49</text>
<text x="237.7" y="88.6">51</text>
<text x="258" y="86.1">50</text>
<text x="258" y="88.6">52</text>
<text x="170.4" y="91.2">53</text>
<text x="170.4" y="93.7">55</text>
<text x="190.7" y="91.2">54</text>
<text x="190.7" y="93.7">56</text>
<text x="237.7" y="91.2">53</text>
<text x="237.7" y="93.7">55</text>
<text x="258" y="91.2">54</text>
<text x="258" y="93.7">56</text>
<text x="170.4" y="96.3">57</text>
<text x="170.4" y="98.8">59</text>
<text x="170.4" y="101.3">61</text>
<text x="190.7" y="96.3">58</text>
<text x="190.7" y="98.8">60</text>
<text x="190.7" y="101.3">62</text>
<text x="237.7" y="96.3">57</text>
<text x="237.7" y="98.8">59</text>
<text x="237.7" y="101.3">61</text>
<text x="258" y="96.3">58</text>
<text x="258" y="98.8">60</text>
<text x="258" y="101.3">62</text>
<text x="170.4" y="103.9">63</text>
<text x="170.4" y="106.4">65</text>
<text x="190.7" y="103.9">64</text>
<text x="190.7" y="106.4">66</text>
<text x="237.7" y="103.9">63</text>
<text x="237.7" y="106.4">65</text>
<text x="258" y="103.9">64</text>
<text x="258" y="106.4">66</text>
<text x="170.4" y="109">67</text>
<text x="170.4" y="111.5">69</text>
<text x="190.7" y="109">68</text>
<text x="190.7" y="111.5">70</text>
<text x="237.7" y="109">67</text>
<text x="237.7" y="111.5">69</text>
<text x="258" y="109">68</text>
<text x="258" y="111.5">70</text>
<text x="170.4" y="114">71</text>
<text x="170.4" y="116.6">73</text>
<text x="170.4" y="119.1">75</text>
<text x="190.7" y="114">72</text>
<text x="190.7" y="116.6">74</text>
<text x="190.7" y="119.1">76</text>
<text x="237.7" y="114">71</text>
<text x="237.7" y="116.6">73</text>
<text x="237.7" y="119.1">75</text>
<text x="258" y="114">72</text>
<text x="258" y="116.6">74</text>
<text x="258" y="119.1">76</text>
<text x="170.4" y="121.7">77</text>
<text x="170.4" y="124.2">79</text>
<text x="190.7" y="121.7">78</text>
<text x="190.7" y="124.2">80</text>
<text x="237.7" y="121.7">77</text>
<text x="237.7" y="124.2">79</text>
<text x="258" y="121.7">78</text>
<text x="258" y="124.2">80</text>
<text x="170.4" y="126.7">81</text>
<text x="170.4" y="129.3">83</text>
<text x="170.4" y="131.8">85</text>
<text x="190.7" y="126.7">82</text>
<text x="190.7" y="129.3">84</text>
<text x="190.7" y="131.8">86</text>
<text x="237.7" y="126.7">81</text>
<text x="237.7" y="129.3">83</text>
<text x="237.7" y="131.8">85</text>
<text x="258" y="126.7">82</text>
<text x="258" y="129.3">84</text>
<text x="258" y="131.8">86</text>
<text x="170.4" y="134.4">87</text>
<text x="170.4" y="136.9">89</text>
<text x="190.7" y="134.4">88</text>
<text x="190.7" y="136.9">90</text>
<text x="237.7" y="134.4">87</text>
<text x="237.7" y="136.9">89</text>
<text x="258" y="134.4">88</text>
<text x="258" y="136.9">90</text>
<text x="170.4" y="139.4">91</text>
<text x="170.4" y="142">93</text>
<text x="190.7" y="139.4">92</text>
<text x="190.7" y="142">94</text>
<text x="237.7" y="139.4">91</text>
<text x="237.7" y="142">93</text>
<text x="258" y="139.4">92</text>
<text x="258" y="142">94</text>
<text x="170.4" y="144.5">95</text>
<text x="170.4" y="147.1">97</text>
<text x="170.4" y="149.6">99</text>
<text x="190.2" y="149.6">100</text>
<text x="190.7" y="144.5">96</text>
<text x="190.7" y="147.1">98</text>
<text x="237.7" y="144.5">95</text>
<text x="237.7" y="147.1">97</text>
<text x="237.7" y="149.6">99</text>
<text x="257.5" y="149.6">100</text>
<text x="258" y="144.5">96</text>
<text x="258" y="147.1">98</text>
</g>
<g font-size="1.4" fill="#006464">
<text x="175" y="26.1">1</text>
<text x="175" y="28.6">3</text>
<text x="187.1" y="26.1">2</text>
<text x="187.1" y="28.6">4</text>
<text x="242.3" y="26.1">1</text>
<text x="242.3" y="28.6">3</text>
<text x="254.4" y="26.1">2</text>
<text x="254.4" y="28.6">4</text>
<text x="175" y="31.2">5</text>
<text x="175" y="33.7">7</text>
<text x="187.1" y="31.2">6</text>
<text x="187.1" y="33.7">8</text>
<text x="242.3" y="31.2">5</text>
<text x="242.3" y="33.7">7</text>
<text x="254.4" y="31.2">6</text>
<text x="254.4" y="33.7">8</text>
<text x="175" y="38.8">11</text>
<text x="175" y="41.3">13</text>
<text x="175" y="36.3">9</text>
<text x="186.1" y="36.3">10</text>
<text x="186.1" y="38.8">12</text>
<text x="186.1" y="41.3">14</text>
<text x="242.3" y="38.8">11</text>
<text x="242.3" y="41.3">13</text>
<text x="242.3" y="36.3">9</text>
<text x="253.4" y="36.3">10</text>
<text x="253.4" y="38.8">12</text>
<text x="253.4" y="41.3">14</text>
<text x="175" y="43.9">15</text>
<text x="175" y="46.4">17</text>
<text x="186.1" y="43.9">16</text>
<text x="186.1" y="46.4">18</text>
<text x="242.3" y="43.9">15</text>
<text x="242.3" y="46.4">17</text>
<text x="253.4" y="43.9">16</text>
<text x="253.4" y="46.4">18</text>
<text x="175" y="49">19</text>
<text x="175" y="51.5">21</text>
<text x="186.1" y="49">20</text>
<text x="186.1" y="51.5">22</text>
<text x="242.3" y="49">19</text>
<text x="242.3" y="51.5">21</text>
<text x="253.4" y="49">20</text>
<text x="253.4" y="51.5">22</text>
<text x="175" y="54">23</text>
<text x="175" y="56.6">25</text>
<text x="175" y="59.1">27</text>
<text x="186.1" y="54">24</text>
<text x="186.1" y="56.6">26</text>
<text x="186.1" y="59.1">28</text>
<text x="242.3" y="54">23</text>
<text x="242.3" y="56.6">25</text>
<text x="242.3" y="59.1">27</text>
<text x="253.4" y="54">24</text>
<text x="253.4" y="56.6">26</text>
<text x="253.4" y="59.1">28</text>
<text x="175" y="61.7">29</text>
<text x="175" y="64.2">31</text>
<text x="186.1" y="61.7">30</text>
<text x="186.1" y="64.2">32</text>
<text x="242.3" y="61.7">29</text>
<text x="242.3" y="64.2">31</text>
<text x="253.4" y="61.7">30</text>
<text x="253.4" y="64.2">32</text>
<text x="175" y="66.7">33</text>
<text x="175" y="69.3">35</text>
<text x="175" y="71.8">37</text>
<text x="186.1" y="66.7">34</text>
<text x="186.1" y="69.3">36</text>
<text x="186.1" y="71.8">38</text>
<text x="242.3" y="66.7">33</text>
<text x="242.3" y="69.3">35</text>
<text x="242.3" y="71.8">37</text>
<text x="253.4" y="66.7">34</text>
<text x="253.4" y="69.3">36</text>
<text x="253.4" y="71.8">38</text>
<text x="175" y="74.4">39</text>
<text x="175" y="76.9">41</text>
<text x="186.1" y="74.4">40</text>
<text x="186.1" y="76.9">42</text>
<text x="242.3" y="74.4">39</text>
<text x="242.3" y="76.9">41</text>
<text x="253.4" y="74.4">40</text>
<text x="253.4" y="76.9">42</text>
<text x="175" y="79.4">43</text>
<text x="175" y="82">45</text>
<text x="186.1" y="79.4">44</text>
<text x="186.1" y="82">46</text>
<text x="242.3" y="79.4">43</text>
<text x="242.3" y="82">45</text>
<text x="253.4" y="79.4">44</text>
<text x="253.4" y="82">46</text>
<text x="175" y="84.5">47</text>
<text x="175" y="87.1">49</text>
<text x="175" y="89.6">51</text>
<text x="186.1" y="84.5">48</text>
<text x="186.1" y="87.1">50</text>
<text x="186.1" y="89.6">52</text>
<text x="242.3" y="84.5">47</text>
<text x="242.3" y="87.1">49</text>
<text x="242.3" y="89.6">51</text>
<text x="253.4" y="84.5">48</text>
<text x="253.4" y="87.1">50</text>
<text x="253.4" y="89.6">52</text>
<text x="175" y="92.1">53</text>
<text x="175" y="94.7">55</text>
<text x="186.1" y="92.1">54</text>
<text x="186.1" y="94.7">56</text>
<text x="242.3" y="92.1">53</text>
<text x="242.3" y="94.7">55</text>
<text x="253.4" y="92.1">54</text>
<text x="253.4" y="94.7">56</text>
<text x="175" y="97.2">57</text>
<text x="175" y="99.8">59</text>
<text x="186.1" y="97.2">58</text>
<text x="186.1" y="99.8">60</text>
<text x="242.3" y="97.2">57</text>
<text x="242.3" y="99.8">59</text>
<text x="253.4" y="97.2">58</text>
<text x="253.4" y="99.8">60</text>
<text x="175" y="102.3">61</text>
<text x="175" y="104.8">63</text>
<text x="175" y="107.4">65</text>
<text x="186.1" y="102.3">62</text>
<text x="186.1" y="104.8">64</text>
<text x="186.1" y="107.4">66</text>
<text x="242.3" y="102.3">61</text>
<text x="242.3" y="104.8">63</text>
<text x="242.3" y="107.4">65</text>
<text x="253.4" y="102.3">62</text>
<text x="253.4" y="104.8">64</text>
<text x="253.4" y="107.4">66</text>
<text x="175" y="109.9">67</text>
<text x="175" y="112.5">69</text>
<text x="186.1" y="109.9">68</text>
<text x="186.1" y="112.5">70</text>
<text x="242.3" y="109.9">67</text>
<text x="242.3" y="112.5">69</text>
<text x="253.4" y="109.9">68</text>
<text x="253.4" y="112.5">70</text>
<text x="175" y="115">71</text>
<text x="175" y="117.5">73</text>
<text x="186.1" y="115">72</text>
<text x="186.1" y="117.5">74</text>
<text x="242.3" y="115">71</text>
<text x="242.3" y="117.5">73</text>
<text x="253.4" y="115">72</text>
<text x="253.4" y="117.5">74</text>
<text x="175" y="120.1">75</text>
<text x="175" y="122.6">77</text>
<text x="175" y="125.2">79</text>
<text x="186.1" y="120.1">76</text>
<text x="186.1" y="122.6">78</text>
<text x="186.1" y="125.2">80</text>
<text x="242.3" y="120.1">75</text>
<text x="242.3" y="122.6">77</text>
<text x="242.3" y="125.2">79</text>
<text x="253.4" y="120.1">76</text>
<text x="253.4" y="122.6">78</text>
<text x="253.4" y="125.2">80</text>
<text x="175" y="127.7">81</text>
<text x="175" y="130.2">83</text>
<text x="186.1" y="127.7">82</text>
<text x="186.1" y="130.2">84</text>
<text x="242.3" y="127.7">81</text>
<text x="242.3" y="130.2">83</text>
<text x="253.4" y="127.7">82</text>
<text x="253.4" y="130.2">84</text>
<text x="175" y="132.8">85</text>
<text x="175" y="135.3">87</text>
<text x="175" y="137.9">89</text>
<text x="186.1" y="132.8">86</text>
<text x="186.1" y="135.3">88</text>
<text x="186.1" y="137.9">90</text>
<text x="242.3" y="132.8">85</text>
<text x="242.3" y="135.3">87</text>
<text x="242.3" y="137.9">89</text>
<text x="253.4" y="132.8">86</text>
<text x="253.4" y="135.3">88</text>
<text x="253.4" y="137.9">90</text>
<text x="175" y="140.4">91</text>
<text x="175" y="142.9">93</text>
<text x="186.1" y="140.4">92</text>
<text x="186.1" y="142.9">94</text>
<text x="242.3" y="140.4">91</text>
<text x="242.3" y="142.9">93</text>
<text x="253.4" y="140.4">92</text>
<text x="253.4" y="142.9">94</text>
<text x="175" y="145.5">95</text>
<text x="175" y="148">97</text>
<text x="186.1" y="145.5">96</text>
<text x="186.1" y="148">98</text>
<text x="242.3" y="145.5">95</text>
<text x="242.3" y="148">97</text>
<text x="253.4" y="145.5">96</text>
<text x="253.4" y="148">98</text>
<text x="175" y="150.6">99</text>
<text x="185.1" y="150.6">100</text>
<text x="242.3" y="150.6">99</text>
<text x="252.4" y="150.6">100</text>
</g>
<g font-size="1.2" fill="#840000">
<text x="31.9" y="21">ID_SD</text>
<text x="31.9" y="23.6">ID_SC</text>
<text x="38.9" y="21">UART_TX/DOUT1</text>
<text x="39.7" y="23.6">UART_RX/DIN1</text>
<text x="222.3" y="28.6">USB_OTG_HS_D_N</text>
<text x="225.9" y="26.1">USB_OTG_ID</text>
<text x="31.9" y="32.2">GPIO2</text>
<text x="31.9" y="35.5">GPIO3</text>
<text x="39.7" y="35.5">ENC_B</text>
<text x="40.2" y="32.2">ENC_A</text>
<text x="222.3" y="31.2">USB_OTG_HS_D_P</text>
<text x="31.9" y="38.8">GPIO4</text>
<text x="40.2" y="38.8">IRQ_TOUCH</text>
<text x="31.9" y="45.9">GPIO6</text>
<text x="32.2" y="42.4">GPIO5</text>
<text x="40.1" y="42.4">DAC_OUT1</text>
<text x="40.6" y="45.9">SPI2_IRQ</text>
<text x="32.7" y="49.5">GPIO7</text>
<text x="32.9" y="53">GPIO8</text>
<text x="40.2" y="53">SPI2_CSA</text>
<text x="40.6" y="49.5">SPI2_CSB</text>
<text x="32.6" y="59.9">GPIO10</text>
<text x="32.7" y="56.8">GPIO9</text>
<text x="40.7" y="59.9">SPI2_MOSI</text>
<text x="40.9" y="56.8">SPI2_MISO</text>
<text x="32.8" y="62.9">GPIO11</text>
<text x="41.2" y="62.9">SPI2_CLK</text>
<text x="32.6" y="69.5">GPIO13</text>
<text x="32.8" y="66.2">GPIO12</text>
<text x="41.1" y="69.5">SPI5_MISO</text>
<text x="41.4" y="66.2">SPI5_CSA</text>
<text x="32.6" y="75.6">GPIO15</text>
<text x="32.6" y="72.6">GPIO14</text>
<text x="40.7" y="72.6">SPI5_MOSI</text>
<text x="41" y="75.6">SPI5_CLK</text>
<text x="32.3" y="82">GPIO17</text>
<text x="32.6" y="78.9">GPIO16</text>
<text x="40.5" y="82">SPI4_CSB</text>
<text x="41" y="78.9">DOUT2</text>
<text x="32.3" y="85">GPIO18</text>
<text x="32.6" y="88.3">GPIO19</text>
<text x="40.9" y="85">SPI4_CSA</text>
<text x="41.1" y="88.3">SPI4_MISO</text>
<text x="32.3" y="91.6">GPIO20</text>
<text x="33.1" y="94.7">GPIO21</text>
<text x="41" y="91.6">SPI4_MOSI</text>
<text x="41" y="94.7">SPI4_CLK</text>
<text x="33.1" y="101.5">GPIO23</text>
<text x="33.3" y="98.2">GPIO22</text>
<text x="41.7" y="98.2">SPI5_IRQ</text>
<text x="42.2" y="101.5">USER_SW</text>
<text x="33.3" y="105.1">GPIO24</text>
<text x="42.4" y="105.1">ENC_SW</text>
<text x="33.8" y="112">GPIO26</text>
<text x="33.8" y="108.6">GPIO25</text>
<text x="42.7" y="112">SPI5_CSB</text>
<text x="43.2" y="108.6">DIN2</text>
<text x="34.1" y="115.3">GPIO27</text>
<text x="35.6" y="118.8">SDA0</text>
<text x="42.5" y="115.3">SPI4_IRQ</text>
<text x="42.9" y="118.8">I2C1_SDA</text>
<text x="35.6" y="122.1">SCL0</text>
<text x="42.2" y="122.1">I2C1_SCL</text>
<text x="35" y="130">CAM0_C_N</text>
<text x="35.1" y="126.2">CAM0_C_P</text>
<text x="45.3" y="126.6">~{FAULT}</text>
<text x="46" y="130">RTC_REF</text>
<text x="34.2" y="137.6">CAM0_D1_N</text>
<text x="34.2" y="135.1">CAM0_D1_P</text>
<text x="45.3" y="137.6">PWR_SSTART</text>
<text x="45.3" y="135.1">PWR_DIRECT</text>
<text x="33.7" y="141.9">CAM0_D0_P</text>
<text x="45.5" y="141.9">OE_SYNC</text>
<text x="34.2" y="145.2">CAM0_D0_N</text>
<text x="45" y="145.2">TFT_BRIGHTNESS</text>
<text x="33" y="150.1">SD_PWR_ON</text>
<text x="33.6" y="153.9">nEXTRST</text>
<text x="46.1" y="150.1">SD_DETECT</text>
<text x="46.2" y="153.9">nEXTRST</text>
<text x="33.8" y="157.4">nRPIBOOT</text>
<text x="46" y="157.4">BOOT0</text>
<text x="32.6" y="163.8">AnalogIP0</text>
<text x="33.1" y="167.6">AnalogIP1</text>
<text x="46.1" y="163.8">AUDIO_OUT</text>
<text x="46.8" y="167.6">WDG</text>
<text x="34.4" y="172.1">Camera_GPIO</text>
<text x="48" y="172.1">PDR_ON</text>
<text x="39.1" y="176">RS485_RX</text>
<text x="40" y="178.5">RS485_TX</text>
<text x="50.5" y="178.5">CAM1_D0_P</text>
<text x="50.5" y="176">CAM1_D0_N</text>
<text x="33.6" y="183.6">USB_OTG_FS_VBUS</text>
<text x="39.8" y="181">RS485_EN</text>
<text x="50.5" y="183.6">HDMI0_CLK_P</text>
<text x="50.5" y="181">CAM1_D1_N</text>
<text x="34.3" y="186.1">USB_OTG_FS_PSO</text>
<text x="42.2" y="191.2">DOUT3</text>
<text x="42.7" y="188.7">DIN3</text>
<text x="50.5" y="188.7">HDMI0_TX1_N</text>
<text x="50.5" y="191.2">HDMI0_TX1_P</text>
<text x="50.5" y="186.1">HDMI0_TX0_P</text>
<text x="35.2" y="193.7">USB_OTG_FS_OC</text>
<text x="50.5" y="193.7">HDMI0_TX0_N</text>
</g>
</g></defs>
<g fill="none" stroke="#840000" stroke-width=".15">
<path d="M10 10h277v190h-277zM12 12h273v186h-273zM31.4 19.4h4.7l.7 .9-.7 .9h-4.7zM38.6 19.4h11.6l.7 .9-.7 .9h-11.6zM60 10v2M110 10v2M160 10v2M210 10v2M260 10v2M31.4 30.6h4.9l.8 .9-.8 .9h-4.9zM31.4 33.9h4.9l.8 .9-.8 .9h-4.9zM31.4 22h4.7l.7 .9-.7 .8h-4.7z"/>
<path d="M31.4 37.2h4.9l.8 .9-.8 .9h-4.9zM39.4 33.9h5l.8 .9-.8 .9h-5zM39.4 22h10.5l.8 .9-.8 .8h-10.5zM39.9 37.2h8.1l.8 .9-.8 .9h-8.1zM39.9 30.6h4.9l.8 .9-.8 .9h-4.9zM48.7 23.3h.5M48.8 22.7l.2-.3v.9M48.9 20.8h.5M156.5 29h9.8l1.3 1.5-1.3 1.5h-9.8zM156.5 34h9.8l1.3 1.6-1.3 1.5h-9.8zM156.5 36.6h9.8l1.3 1.5-1.3 1.5h-9.8zM156.5 26.4h9.8l1.3 1.5-1.3 1.6h-9.8z"/>
<path d="M160.2 39.1h6.1l1.3 1.5-1.3 1.6h-6.1zM160.2 23.9h6.1l1.3 1.5-1.3 1.5h-6.1zM160.2 31.5h6.1l1.3 1.5-1.3 1.5h-6.1zM168.9 25.4h5.1M168.9 35.6h5.1M168.9 38.1h5.1M168.9 27.9h5.1M168.9 30.5h5.1M168.9 33h5.1M189.2 25.4h5.1M189.2 35.6h5.1M189.2 38.1h5.1"/>
<path d="M189.2 27.9h5.1M189.2 30.5h5.1M189.2 33h5.1M196.9 29h9.9v3h-9.9l-1.3-1.5zM196.9 26.4h9.8v3.1h-9.8l-1.3-1.6zM196.9 23.9h6.2v3h-6.2l-1.3-1.5zM196.9 36.6h9.8v3h-9.8l-1.3-1.5zM196.9 31.5h6.2v3h-6.2l-1.3-1.5zM196.9 34h9.9v3.1h-9.9l-1.3-1.5zM196.9 39.1h6.2v3.1h-6.2l-1.3-1.6zM218.9 36.6h14.7l1.3 1.5-1.3 1.5h-14.7zM220.4 34h13.2l1.3 1.6-1.3 1.5h-13.2z"/>
<path d="M221.8 27.1h12.4l.7 .8-.7 .9h-12.4l-.8-.9zM221.9 29.6h12.3l.7 .9-.7 .9h-12.3l-.8-.9zM225.5 24.5h8.7l.7 .9-.7 .9h-8.7zM227.5 31.5h6.1l1.3 1.5-1.3 1.5h-6.1zM227.5 39.1h6.1l1.3 1.5-1.3 1.6h-6.1zM236.2 25.4h5.1M236.2 35.6h5.1M236.2 38.1h5.1M236.2 27.9h5.1M236.2 30.5h5.1M236.2 33h5.1M256.5 25.4h5.1"/>
<path d="M256.5 35.6h5.1M256.5 38.1h5.1M256.5 27.9h5.1M256.5 30.5h5.1M256.5 33h5.1M264.2 36.6h14.8v3h-14.8l-1.3-1.5zM264.2 34h14.7v3.1h-14.7l-1.3-1.5zM264.2 39.1h6.2v3.1h-6.2l-1.3-1.6zM264.2 31.5h6.2v3h-6.2l-1.3-1.5zM264.2 23.9h19.1v3h-19.1l-1.3-1.5zM10 60h2M31.4 44.3h4.9l.8 .9-.8 .9h-4.9z"/>
<path d="M31.7 40.8h4.9l.7 .9-.7 .8h-4.9zM32.1 58.3h5.7l.8 .9-.8 .9h-5.7zM32.2 55.2h4.9l.7 .9-.7 .9h-4.9zM32.2 47.9h4.9l.7 .9-.7 .9h-4.9zM32.5 51.4h4.8l.8 .9-.8 .9h-4.8zM39.9 51.4h7l.8 .9-.8 .9h-7zM39.9 40.8h7.5v1.7h-7.5l-.8-.8zM40.4 58.3h7.8l.7 .9-.7 .9h-7.8zM40.4 44.3h6.8v1.8h-6.8l-.8-.9zM40.4 47.9h7.2v1.8h-7.2l-.8-.9zM40.7 55.2h7.7v1.8h-7.7l-.8-.9zM146.6 49.3h19.7l1.3 1.5-1.3 1.5h-19.7z"/>
<path d="M152.5 44.2h13.8l1.3 1.5-1.3 1.5h-13.8zM152.5 46.7h13.8l1.3 1.6-1.3 1.5h-13.8zM152.5 41.7h13.8l1.3 1.5-1.3 1.5h-13.8zM156.5 56.9h9.8l1.3 1.5-1.3 1.5h-9.8zM156.5 59.4h9.8l1.3 1.6-1.3 1.5h-9.8zM156.5 54.4h9.8l1.3 1.5-1.3 1.5h-9.8zM160.2 51.8h6.1l1.3 1.5-1.3 1.6h-6.1zM164.8 56.7h.8M165 50.6l.3 1M165.3 51.6l-.1 .4-.2 .1M165.7 50.6l-.4 1M168.9 40.6h5.1"/>
<path d="M168.9 43.2h5.1M168.9 45.7h5.1M168.9 48.3h5.1M168.9 50.8h5.1M168.9 53.3h5.1M168.9 55.9h5.1M168.9 58.4h5.1M189.2 40.6h5.1M189.2 43.2h5.1M189.2 45.7h5.1M189.2 48.3h5.1M189.2 50.8h5.1"/>
<path d="M189.2 53.3h5.1M189.2 55.9h5.1M189.2 58.4h5.1M196.9 54.4h9.8v3h-9.8l-1.3-1.5zM196.9 59.4h8.3v3.1h-8.3l-1.3-1.5zM196.9 56.9h9.8v3h-9.8l-1.3-1.5zM196.9 49.3h6.2v3h-6.2l-1.3-1.5zM196.9 51.8h9.8v3.1h-9.8l-1.3-1.6zM196.9 44.2h18.2v3h-18.2l-1.3-1.5zM196.9 46.7h16.5v3.1h-16.5l-1.3-1.5zM196.9 41.7h16.2v3h-16.2l-1.3-1.5zM219.2 41.7h14.4l1.3 1.5-1.3 1.5h-14.4z"/>
<path d="M219.2 49.3h14.4l1.3 1.5-1.3 1.5h-14.4zM219.3 51.8h14.3l1.3 1.5-1.3 1.6h-14.3zM219.3 44.2h14.3l1.3 1.5-1.3 1.5h-14.3zM220.6 56.9h13l1.3 1.5-1.3 1.5h-13zM220.7 59.4h12.9l1.3 1.6-1.3 1.5h-12.9zM227.5 54.4h6.1l1.3 1.5-1.3 1.5h-6.1zM227.5 46.7h6.1l1.3 1.6-1.3 1.5h-6.1zM236.2 40.6h5.1M236.2 43.2h5.1M236.2 45.7h5.1M236.2 48.3h5.1M236.2 50.8h5.1"/>
<path d="M236.2 53.3h5.1M236.2 55.9h5.1M236.2 58.4h5.1M256.5 40.6h5.1M256.5 43.2h5.1M256.5 45.7h5.1M256.5 48.3h5.1M256.5 50.8h5.1M256.5 53.3h5.1M256.5 55.9h5.1M256.5 58.4h5.1M264.2 54.4h6.2v3h-6.2l-1.3-1.5z"/>
<path d="M264.2 41.7h13.4v3h-13.4l-1.3-1.5zM264.2 46.7h6.2v3.1h-6.2l-1.3-1.5zM264.2 44.2h13.5v3h-13.5l-1.3-1.5zM264.2 51.8h13.1v3.1h-13.1l-1.3-1.6zM264.2 49.3h13.1v3h-13.1l-1.3-1.5zM264.2 56.9h14.4v3h-14.4l-1.3-1.5zM264.2 59.4h14.4v3.1h-14.4l-1.3-1.5zM285 60h2M32.1 67.9h5.7l.8 .9-.8 .9h-5.7zM32.1 77.3h5.7l.8 .9-.8 .9h-5.7zM32.1 74h5.7l.8 .9-.8 .9h-5.7zM32.1 71h5.7l.8 .9-.8 .9h-5.7z"/>
<path d="M32.4 64.6h5.7l.8 .9-.8 .9h-5.7zM32.4 61.3h5.7l.8 .9-.8 .9h-5.7zM36.9 72.1h.6M37.1 66h.6M37.2 62.7h.5M37.4 74.9v.4M37.7 65.2v.3M40.4 71h7.8l.7 .9-.7 .9h-7.8zM40.6 77.3h5.2l.8 .9-.8 .9h-5.2zM40.6 74h7.1l.8 .9-.8 .9h-7.1zM40.9 61.3h7.1l.7 .9-.7 .9h-7.1zM40.9 67.9h7.8v1.8h-7.8l-.8-.9z"/>
<path d="M41.2 64.6h7v1.8h-7l-.8-.9zM156.5 79.8h9.8l1.3 1.5-1.3 1.5h-9.8zM156.5 74.7h9.8l1.3 1.5-1.3 1.5h-9.8zM156.5 62h9.8l1.3 1.5-1.3 1.5h-9.8zM158 72.1h8.3l1.3 1.6-1.3 1.5h-8.3zM158 69.6h8.3l1.3 1.5-1.3 1.5h-8.3zM158.4 67.1h7.9l1.3 1.5-1.3 1.5h-7.9zM160.2 64.5h6.1l1.3 1.5-1.3 1.6h-6.1zM160.2 77.2h6.1l1.3 1.5-1.3 1.6h-6.1zM168.9 61h5.1M168.9 63.5h5.1M168.9 66h5.1"/>
<path d="M168.9 68.6h5.1M168.9 71.1h5.1M168.9 73.7h5.1M168.9 76.2h5.1M168.9 78.7h5.1M189.2 61h5.1M189.2 63.5h5.1M189.2 66h5.1M189.2 68.6h5.1M189.2 71.1h5.1M189.2 73.7h5.1M189.2 76.2h5.1"/>
<path d="M189.2 78.7h5.1M196.9 72.1h8.3v3.1h-8.3l-1.3-1.5zM196.9 69.6h9.8v3h-9.8l-1.3-1.5zM196.9 67.1h7.9v3h-7.9l-1.3-1.5zM196.9 64.5h8.3v3.1h-8.3l-1.3-1.6zM196.9 62h6.2v3h-6.2l-1.3-1.5zM196.9 74.7h6.2v3h-6.2l-1.3-1.5zM196.9 79.8h9.8v3h-9.8l-1.3-1.5zM196.9 77.2h9.8v3.1h-9.8l-1.3-1.6zM213.7 77.2h19.9l1.3 1.5-1.3 1.6h-19.9zM219.2 64.5h14.4l1.3 1.5-1.3 1.6h-14.4zM219.2 72.1h14.4l1.3 1.6-1.3 1.5h-14.4z"/>
<path d="M219.3 67.1h14.3l1.3 1.5-1.3 1.5h-14.3zM219.3 74.7h14.3l1.3 1.5-1.3 1.5h-14.3zM219.6 79.8h14l1.3 1.5-1.3 1.5h-14zM227.5 62h6.1l1.3 1.5-1.3 1.5h-6.1zM227.5 69.6h6.1l1.3 1.5-1.3 1.5h-6.1zM236.2 61h5.1M236.2 63.5h5.1M236.2 66h5.1M236.2 68.6h5.1M236.2 71.1h5.1M236.2 73.7h5.1M236.2 76.2h5.1"/>
<path d="M236.2 78.7h5.1M256.5 61h5.1M256.5 63.5h5.1M256.5 66h5.1M256.5 68.6h5.1M256.5 71.1h5.1M256.5 73.7h5.1M256.5 76.2h5.1M256.5 78.7h5.1M264.2 62h6.2v3h-6.2l-1.3-1.5zM264.2 69.6h6.2v3h-6.2l-1.3-1.5zM264.2 72.1h13v3.1h-13l-1.3-1.5z"/>
<path d="M264.2 74.7h12.9v3h-12.9l-1.3-1.5zM264.2 64.5h14.4v3.1h-14.4l-1.3-1.6zM264.2 67.1h14.4v3h-14.4l-1.3-1.5zM264.2 79.8h16.5v3h-16.5l-1.3-1.5zM264.2 77.2h6.2v3.1h-6.2l-1.3-1.6zM31.9 80.4h5.7l.8 .9-.8 .9h-5.7zM31.9 83.4h5.7l.8 .9-.8 .9h-5.7zM31.9 90h5.7l.8 .9-.8 .9h-5.7zM32.1 86.7h5.7l.8 .9-.8 .9h-5.7zM32.6 93.1h5.7l.8 .9-.8 .9h-5.7zM32.6 99.9h5.7l.8 .9-.8 .9h-5.7zM32.9 96.6h5.7l.8 .9-.8 .9h-5.7z"/>
<path d="M36.6 80.9h.6l-.4 .9M37.1 84v.2M37.1 84.4v.3M37.4 87.3v.6M37.4 87.6v.1M37.4 94.5h.5M37.7 98h.5M38.2 97.2v.3M40.1 80.4h7.2l.8 .9-.8 .9h-7.2zM40.6 90h7.8l.8 .9-.8 .9h-7.8zM40.6 93.1h7.1l.8 .9-.8 .9h-7.1zM40.7 83.4h7v1.8h-7l-.8-.9z"/>
<path d="M40.9 86.7h7.8v1.8h-7.8l-.8-.9zM41.4 96.6h6.8l.8 .9-.8 .9h-6.8zM41.9 99.9h6.9l.8 .9-.8 .9h-6.9zM156.4 95h9.9l1.3 1.5-1.3 1.5h-9.9zM156.5 92.5h9.8l1.3 1.5-1.3 1.5h-9.8zM156.5 82.3h9.8l1.3 1.5-1.3 1.5h-9.8zM156.5 84.8h9.8l1.3 1.6-1.3 1.5h-9.8zM156.5 87.4h9.8l1.3 1.5-1.3 1.5h-9.8zM160.2 89.9h6.1l1.3 1.5-1.3 1.6h-6.1zM160.2 97.5h6.1l1.3 1.6-1.3 1.5h-6.1zM168.9 81.3h5.1M168.9 83.8h5.1"/>
<path d="M168.9 86.4h5.1M168.9 88.9h5.1M168.9 91.4h5.1M168.9 94h5.1M168.9 96.5h5.1M168.9 99.1h5.1M189.2 81.3h5.1M189.2 83.8h5.1M189.2 86.4h5.1M189.2 88.9h5.1M189.2 91.4h5.1M189.2 94h5.1"/>
<path d="M189.2 96.5h5.1M189.2 99.1h5.1M196.9 97.5h6.2v3.1h-6.2l-1.3-1.5zM196.9 82.3h9.8v3h-9.8l-1.3-1.5zM196.9 84.8h9.8v3.1h-9.8l-1.3-1.5zM196.9 92.5h8.3v3h-8.3l-1.3-1.5zM196.9 95h8.3v3h-8.3l-1.3-1.5zM196.9 87.4h6.2v3h-6.2l-1.3-1.5zM196.9 89.9h8.3v3.1h-8.3l-1.3-1.6zM213.7 89.9h19.9l1.3 1.5-1.3 1.6h-19.9zM219.5 87.4h14.1l1.3 1.5-1.3 1.5h-14.1zM219.5 84.8h14.1l1.3 1.6-1.3 1.5h-14.1z"/>
<path d="M219.7 82.3h13.9l1.3 1.5-1.3 1.5h-13.9zM220.1 95h13.5l1.3 1.5-1.3 1.5h-13.5zM220.1 97.5h13.5l1.3 1.6-1.3 1.5h-13.5zM227.5 92.5h6.1l1.3 1.5-1.3 1.5h-6.1zM236.2 81.3h5.1M236.2 83.8h5.1M236.2 86.4h5.1M236.2 88.9h5.1M236.2 91.4h5.1M236.2 94h5.1M236.2 96.5h5.1M236.2 99.1h5.1"/>
<path d="M256.5 81.3h5.1M256.5 83.8h5.1M256.5 86.4h5.1M256.5 88.9h5.1M256.5 91.4h5.1M256.5 94h5.1M256.5 96.5h5.1M256.5 99.1h5.1M264.2 89.9h16.6v3.1h-16.6l-1.3-1.6zM264.2 84.8h6.2v3.1h-6.2l-1.3-1.5zM264.2 92.5h6.2v3h-6.2l-1.3-1.5zM264.2 97.5h16.6v3.1h-16.6l-1.3-1.5z"/>
<path d="M264.2 95h16.5v3h-16.5l-1.3-1.5zM264.2 82.3h16.6v3h-16.6l-1.3-1.5zM264.2 87.4h16.5v3h-16.5l-1.3-1.5zM10 110h2M32.9 103.5h5.7l.8 .9-.8 .9h-5.7zM33.4 110.4h5.7l.8 .9-.8 .8h-5.7zM33.4 107.1h5.7l.8 .9-.8 .8h-5.7zM33.6 113.7h5.8l.7 .9-.7 .8h-5.8zM35.1 117.2h4.3l.7 .9-.7 .9h-4.3zM37.7 104.6h.5M38.4 114.1h.6l-.4 .9M38.7 108v.3"/>
<path d="M42.2 113.7h6.8l.7 .9-.7 .8h-6.8zM42.2 103.5h6l.8 .9-.8 .9h-6l-.8-.9zM42.4 110.4h7.2l.8 .9-.8 .8h-7.2l-.7-.8zM42.7 117.2h7l.8 .9-.8 .9h-7l-.8-.9zM42.9 107.1h4v1.7h-4l-.7-.8zM124.2 112.7h3.1v12.3l-1.6 1.4-1.5-1.4zM145.8 115.3h20.5l1.3 1.5-1.3 1.6h-20.5zM151.5 117.9h14.8l1.3 1.5-1.3 1.5h-14.8zM155.2 110.2h11.1l1.3 1.6-1.3 1.5h-11.1zM155.2 102.6h11.1l1.3 1.5-1.3 1.6h-11.1zM155.2 100.1h11.1l1.3 1.5-1.3 1.5h-11.1zM155.2 107.7h11.1l1.3 1.5-1.3 1.5h-11.1z"/>
<path d="M160.2 105.2h6.1l1.3 1.5-1.3 1.5h-6.1zM160.2 112.8h6.1l1.3 1.5-1.3 1.5h-6.1zM165.4 116.6l.2 .1v.3l-.7 .1M165.6 117.6l-.2 .1M168.9 101.6h5.1M168.9 104.1h5.1M168.9 106.7h5.1M168.9 109.2h5.1M168.9 111.8h5.1M168.9 114.3h5.1M168.9 116.8h5.1M168.9 119.4h5.1"/>
<path d="M189.2 101.6h5.1M189.2 104.1h5.1M189.2 106.7h5.1M189.2 109.2h5.1M189.2 111.8h5.1M189.2 114.3h5.1M189.2 116.8h5.1M189.2 119.4h5.1M196.9 100.1h10.4v3h-10.4l-1.3-1.5zM196.9 102.6h11.1v3.1h-11.1l-1.3-1.6zM196.9 105.2h6.2v3h-6.2l-1.3-1.5zM196.9 112.8h11.1v3h-11.1l-1.3-1.5z"/>
<path d="M196.9 110.2h11.1v3.1h-11.1l-1.3-1.5zM196.9 107.7h11.1v3h-11.1l-1.3-1.5zM196.9 115.3h6.2v3.1h-6.2l-1.3-1.6zM220.1 117.9h13.5l1.3 1.5-1.3 1.5h-13.5zM220.1 102.6h13.5l1.3 1.5-1.3 1.6h-13.5zM220.1 105.2h13.5l1.3 1.5-1.3 1.5h-13.5zM221.5 110.2h12.1l1.3 1.6-1.3 1.5h-12.1zM221.6 112.8h12l1.3 1.5-1.3 1.5h-12zM227.5 115.3h6.1l1.3 1.5-1.3 1.6h-6.1zM227.5 107.7h6.1l1.3 1.5-1.3 1.5h-6.1zM227.5 100.1h6.1l1.3 1.5-1.3 1.5h-6.1zM236.2 101.6h5.1"/>
<path d="M236.2 104.1h5.1M236.2 106.7h5.1M236.2 109.2h5.1M236.2 111.8h5.1M236.2 114.3h5.1M236.2 116.8h5.1M236.2 119.4h5.1M256.5 101.6h5.1M256.5 104.1h5.1M256.5 106.7h5.1M256.5 109.2h5.1M256.5 111.8h5.1"/>
<path d="M256.5 114.3h5.1M256.5 116.8h5.1M256.5 119.4h5.1M264.2 105.2h16.8v3h-16.8l-1.3-1.5zM264.2 112.8h16.6v3h-16.6l-1.3-1.5zM264.2 110.2h16.5v3.1h-16.5l-1.3-1.5zM264.2 102.6h16.7v3.1h-16.7l-1.3-1.6zM264.2 115.3h6.2v3.1h-6.2l-1.3-1.6zM264.2 117.9h16.5v3h-16.5l-1.3-1.5zM264.2 100.1h6.2v3h-6.2l-1.3-1.5zM264.2 107.7h6.2v3h-6.2l-1.3-1.5zM285 110h2"/>
<path d="M33.7 136h8.4l.8 .9-.8 .9h-8.4zM33.8 133.5h8.3l.8 .9-.8 .9h-8.3zM34.6 128.4h7.5l.8 .9-.8 .9h-7.5zM34.6 124.6h7.5l.8 .9-.8 .9h-7.5zM35.2 120.5h4.2l.7 .9-.7 .9h-4.2zM41.9 120.5h7l.8 .9-.8 .9h-7zM45 136h9l.8 .9-.8 .9h-9zM45 133.5h8.9l.8 .9-.8 .9h-8.9zM45 124.6h4.7l.8 .9-.8 .9h-4.7zM45.4 124.7h3.7M45.7 128.4h6.5v1.8h-6.5l-.7-.9zM45.9 125.1h-.4v.9"/>
<path d="M46.1 126l.3-.9 .3 .9M47 125.1v.7M47.5 125.1v.7M48 125.1v.9M48.6 125.1h.5M48.8 125.1v.9M125 132.7l.7 1.3M125.7 131.4v2.6M126.5 132.7l-.8 1.3M150.9 135.6h15.4l1.3 1.6-1.3 1.5h-15.4zM151.2 138.2h15.1l1.3 1.5-1.3 1.5h-15.1zM152.4 128.3h2.5"/>
<path d="M152.4 128.3l1.3 .7M153.7 127.5l-1.3 .8M165 139.6l.4-.1 .2 .1v.3l-.7 .1M165.1 137h.5v.3l-.7 .2M165.6 137.9l-.5 .1M168.9 121.9h5.1M168.9 124.5h5.1M168.9 127h5.1M168.9 129.5h5.1M168.9 132.1h5.1M168.9 134.6h5.1M168.9 137.2h5.1"/>
<path d="M168.9 139.7h5.1M189.2 121.9h5.1M189.2 124.5h5.1M189.2 127h5.1M189.2 129.5h5.1M189.2 132.1h5.1M189.2 134.6h5.1M189.2 137.2h5.1M189.2 139.7h5.1M196.9 120.4h13.6v3h-13.6l-1.3-1.5zM196.9 122.9h7.2v3.1h-7.2l-1.3-1.5zM196.9 125.5h7.3v3h-7.3l-1.3-1.5z"/>
<path d="M196.9 138.2h10.4v3h-10.4l-1.3-1.5zM196.9 135.6h12.3v3.1h-12.3l-1.3-1.5zM196.9 133.1h12.3v3h-12.3l-1.3-1.5zM196.9 128h12.3v3.1h-12.3l-1.3-1.6zM196.9 130.6h12.3v3h-12.3l-1.3-1.5zM220.1 125.5h13.5l1.3 1.5-1.3 1.5h-13.5zM220.1 120.4h13.5l1.3 1.5-1.3 1.5h-13.5zM220.1 128h13.5l1.3 1.5-1.3 1.6h-13.5zM221.5 133.1h12.1l1.3 1.5-1.3 1.5h-12.1zM221.6 135.6h12l1.3 1.6-1.3 1.5h-12zM227.5 130.6h6.1l1.3 1.5-1.3 1.5h-6.1zM227.5 138.2h6.1l1.3 1.5-1.3 1.5h-6.1z"/>
<path d="M227.5 122.9h6.1l1.3 1.6-1.3 1.5h-6.1zM236.2 121.9h5.1M236.2 124.5h5.1M236.2 127h5.1M236.2 129.5h5.1M236.2 132.1h5.1M236.2 134.6h5.1M236.2 137.2h5.1M236.2 139.7h5.1M256.5 121.9h5.1M256.5 124.5h5.1M256.5 127h5.1"/>
<path d="M256.5 129.5h5.1M256.5 132.1h5.1M256.5 134.6h5.1M256.5 137.2h5.1M256.5 139.7h5.1M264.2 120.4h16.6v3h-16.6l-1.3-1.5zM264.2 128h16.6v3.1h-16.6l-1.3-1.6zM264.2 130.6h6.2v3h-6.2l-1.3-1.5zM264.2 133.1h16.7v3h-16.7l-1.3-1.5zM264.2 122.9h6.2v3.1h-6.2l-1.3-1.5zM264.2 125.5h16.5v3h-16.5l-1.3-1.5zM264.2 135.6h16.8v3.1h-16.8l-1.3-1.5z"/>
<path d="M264.2 138.2h6.2v3h-6.2l-1.3-1.5zM10 160h2M32.5 148.5h8.6l.8 .9-.8 .8h-8.6zM33.2 152.3h6.4l.8 .9-.8 .9h-6.4zM33.3 140.3h8.3l.8 .9-.8 .9h-8.3zM33.3 155.8h7.3l.8 .9-.8 .9h-7.3zM33.7 143.6h8.4l.8 .9-.8 .9h-8.4zM44.7 143.6h11.8l.8 .9-.8 .9h-11.8zM45.2 140.3h6.7l.8 .9-.8 .9h-6.7zM45.7 148.5h8.1l.7 .9-.7 .8h-8.1zM45.7 155.8h5.2v1.8h-5.2l-.7-.9zM46 152.3h6.4l.8 .9-.8 .9h-6.4l-.8-.9z"/>
<path d="M149.7 145.8h16.6l1.3 1.5-1.3 1.5h-16.6zM149.9 143.3h16.4l1.3 1.5-1.3 1.5h-16.4zM152.2 148.3h14.1l1.3 1.6-1.3 1.5h-14.1zM153.8 140.7h12.5l1.3 1.5-1.3 1.6h-12.5zM165 140.4l.1 .1 .5-.1M165.6 146.8a1.18 1.18 0 0 1-.2 1.3M168.9 149.9h5.1M168.9 142.2h5.1M168.9 144.8h5.1M168.9 147.3h5.1M189.2 149.9h5.1M189.2 142.2h5.1"/>
<path d="M189.2 144.8h5.1M189.2 147.3h5.1M196.9 148.3h11v3.1h-11l-1.3-1.5zM196.9 145.8h6.2v3h-6.2l-1.3-1.5zM196.9 140.7h12.8v3.1h-12.8l-1.3-1.6zM196.9 143.3h12.8v3h-12.8l-1.3-1.5zM207.5 143.1h.8M207.5 142l.4-.5v1.6M207.7 144.1a.36 .36 0 0 1 .6 .3 .79 .79 0 0 1-.5 1.2l-.1-.1M219.6 148.3h14l1.3 1.6-1.3 1.5h-14zM220.1 140.7h13.5l1.3 1.5-1.3 1.6h-13.5zM220.1 143.3h13.5l1.3 1.5-1.3 1.5h-13.5z"/>
<path d="M227.5 145.8h6.1l1.3 1.5-1.3 1.5h-6.1zM235.2 154.2h12.1l1.1 1.2-1.1 1.3h-12.1zM236.2 149.9h5.1M236.2 142.2h5.1M236.2 144.8h5.1M236.2 147.3h5.1M250.5 153.9h13.9v3.1h-13.9l-1.3-1.6zM256.5 149.9h5.1M256.5 142.2h5.1M256.5 144.8h5.1M256.5 147.3h5.1M264.2 143.3h13.5v3h-13.5l-1.3-1.5z"/>
<path d="M264.2 140.7h13.6v3.1h-13.6l-1.3-1.6zM264.2 145.8h6.2v3h-6.2l-1.3-1.5zM264.2 148.3h13.9v3.1h-13.9l-1.3-1.5zM285 160h2M32.1 162.2h7.5l.8 .9-.8 .9h-7.5zM32.6 166h7.5l.8 .9-.8 .9h-7.5zM34 170.6h9.7l.7 .9-.7 .8h-9.7zM38.6 174.4h7.6l.8 .9-.8 .8h-7.6zM38.8 162.7h.1a.47 .47 0 0 1 .3 .4 .47 .47 0 0 1-.3 .4 .59 .59 0 0 1-.1-.8zM39.2 167.4h.5M39.2 166.7l.3-.2v.9M39.4 179.5h7.6v1.7h-7.6l-.8-.9z"/>
<path d="M39.6 176.9h7.4v1.8h-7.4l-.7-.9zM42.9 171a.3 .3 0 0 1 .4 .3v.3a.3 .3 0 0 1-.4 .3M45.3 174.8l.6 .9M45.7 162.2h8.1l.7 .9-.7 .9h-8.1zM45.9 174.8l-.6 .9M45.9 179.9l.5 .9v-.9M45.9 177.4l.6 .9M46.5 166h3.7l.7 .9-.7 .9h-3.7zM46.5 177.4l-.6 .9M47.8 170.6h6.1v1.7h-6.1l-.8-.8zM50.3 176.9h8.4v1.8h-8.4l-.8-.9zM50.3 174.4h8.4v1.7h-8.4l-.8-.8z"/>
<path d="M50.3 179.5h8.4v1.7h-8.4l-.8-.9zM177 166h108v32h-108zM33.1 182h13.1l.8 .9-.8 .9h-13.1zM33.9 184.5h12.3l.8 .9-.8 .9h-12.3zM34.7 192.2h11.5l.8 .8-.8 .9h-11.5zM41.8 189.6h5.2v1.8h-5.2l-.7-.9zM42.2 187.1h4l.8 .9-.8 .8h-4zM50.3 182h9.7v1.8h-9.7l-.8-.9zM50.3 187.1h9.6v1.7h-9.6l-.8-.8zM50.3 189.6h9.6v1.8h-9.6l-.8-.9zM50.3 192.2h9.6v1.7h-9.6l-.8-.9zM50.3 184.5h9.6v1.8h-9.6l-.8-.9z"/>
<path d="M60 198v2M110 198v2M160 198v2M177 194.5h108M177 191.5h108M177 187.5h108M177 181.5h108M182.4 186.3h.1l-.1 .1M182.4 185.5h.1l-.1 .1M184.6 183.6v.1M184.6 182.8v.1M191.1 183.2h1"/>
<path d="M191.9 182.7v1M197 191.5v3M204.4 182.7l-.3 .1M205.9 182.1l-1.3 2M209.5 185.5l-.4-.1-.2 .2 .1 .2 .5 .2 .1 .1-.1 .2-.1 .1-.5-.1M210 198v2M210.9 185.5l-.5-.1-.3 .3v.4l.2 .2 .1 .1 .5-.1M211.5 185.5a.37 .37 0 0 1 .6 .1v.8M211.5 184.9v1.5M260 198v2M261 191.5v6.5M270.3 195.1h.7"/>
<path d="M270.4 195.7h.4l.3 .3v.3l-.2 .2-.5 .1"/>
</g>
<g fill="none" stroke="#006464" stroke-width=".15">
<path d="M190 20.1a1.46 1.46 0 0 0 0 1.9M191 20.2h-.6v.7l.2-.2 .4 .1 .1 .2-.1 .4-.1 .1h-.3l-.2-.1M191.6 21.5h.7M191.6 20.6l.4-.4v1.3M192.7 20.1a1.46 1.46 0 0 1 0 1.9M257.3 20.1a1.46 1.46 0 0 0 0 1.9M258.4 20.2h-.7v.7l.2-.2 .4 .1 .1 .2v.4l-.2 .1h-.3l-.2-.1M258.9 21.5h.7M258.9 20.6l.4-.4v1.3M260 20.1a1.46 1.46 0 0 1 0 1.9M127.2 134.3h.8l-.4 .5M127.8 134.8l.2 .2v.3l-.2 .3"/>
<path d="M150.7 126.5l1.3 .4M187.9 149.4l.1 .3-.1 .5M255.2 149.4l.1 .3-.1 .5"/>
</g>
<g fill="#ffffc2" stroke="#ffffc2" stroke-width=".13">
<path d="M174 22.9h15.2v129.5h-15.2z"/>
<path d="M241.3 22.9h15.2v129.5h-15.2z"/>
</g>
<g fill="none" stroke="#840000" stroke-width=".25">
<path d="M174 22.9h15.2v129.5h-15.2zM174 38.1h1.9M174 35.6h1.9M174 33h1.9M174 30.5h1.9M174 27.9h1.9M174 25.4h1.9M187.3 38.1h1.9M187.3 35.6h1.9M187.3 33h1.9M187.3 30.5h1.9M187.3 27.9h1.9"/>
<path d="M187.3 25.4h1.9M241.3 22.9h15.2v129.5h-15.2zM241.3 38.1h1.9M241.3 35.6h1.9M241.3 33h1.9M241.3 30.5h1.9M241.3 27.9h1.9M241.3 25.4h1.9M254.6 38.1h1.9M254.6 35.6h1.9M254.6 33h1.9M254.6 30.5h1.9"/>
<path d="M254.6 27.9h1.9M254.6 25.4h1.9M174 58.4h1.9M174 55.9h1.9M174 53.3h1.9M174 50.8h1.9M174 48.3h1.9M174 45.7h1.9M174 43.2h1.9M174 40.6h1.9M187.3 58.4h1.9M187.3 55.9h1.9"/>
<path d="M187.3 53.3h1.9M187.3 50.8h1.9M187.3 48.3h1.9M187.3 45.7h1.9M187.3 43.2h1.9M187.3 40.6h1.9M241.3 58.4h1.9M241.3 55.9h1.9M241.3 53.3h1.9M241.3 50.8h1.9M241.3 48.3h1.9M241.3 45.7h1.9"/>
<path d="M241.3 43.2h1.9M241.3 40.6h1.9M254.6 58.4h1.9M254.6 55.9h1.9M254.6 53.3h1.9M254.6 50.8h1.9M254.6 48.3h1.9M254.6 45.7h1.9M254.6 43.2h1.9M254.6 40.6h1.9M174 78.7h1.9M174 76.2h1.9"/>
<path d="M174 73.7h1.9M174 71.1h1.9M174 68.6h1.9M174 66h1.9M174 63.5h1.9M174 61h1.9M187.3 78.7h1.9M187.3 76.2h1.9M187.3 73.7h1.9M187.3 71.1h1.9M187.3 68.6h1.9M187.3 66h1.9"/>
<path d="M187.3 63.5h1.9M187.3 61h1.9M241.3 78.7h1.9M241.3 76.2h1.9M241.3 73.7h1.9M241.3 71.1h1.9M241.3 68.6h1.9M241.3 66h1.9M241.3 63.5h1.9M241.3 61h1.9M254.6 78.7h1.9M254.6 76.2h1.9"/>
<path d="M254.6 73.7h1.9M254.6 71.1h1.9M254.6 68.6h1.9M254.6 66h1.9M254.6 63.5h1.9M254.6 61h1.9M174 99.1h1.9M174 96.5h1.9M174 94h1.9M174 91.4h1.9M174 88.9h1.9M174 86.4h1.9"/>
<path d="M174 83.8h1.9M174 81.3h1.9M187.3 99.1h1.9M187.3 96.5h1.9M187.3 94h1.9M187.3 91.4h1.9M187.3 88.9h1.9M187.3 86.4h1.9M187.3 83.8h1.9M187.3 81.3h1.9M241.3 99.1h1.9M241.3 96.5h1.9"/>
<path d="M241.3 94h1.9M241.3 91.4h1.9M241.3 88.9h1.9M241.3 86.4h1.9M241.3 83.8h1.9M241.3 81.3h1.9M254.6 99.1h1.9M254.6 96.5h1.9M254.6 94h1.9M254.6 91.4h1.9M254.6 88.9h1.9M254.6 86.4h1.9"/>
<path d="M254.6 83.8h1.9M254.6 81.3h1.9M174 119.4h1.9M174 116.8h1.9M174 114.3h1.9M174 111.8h1.9M174 109.2h1.9M174 106.7h1.9M174 104.1h1.9M174 101.6h1.9M187.3 119.4h1.9M187.3 116.8h1.9"/>
<path d="M187.3 114.3h1.9M187.3 111.8h1.9M187.3 109.2h1.9M187.3 106.7h1.9M187.3 104.1h1.9M187.3 101.6h1.9M241.3 119.4h1.9M241.3 116.8h1.9M241.3 114.3h1.9M241.3 111.8h1.9M241.3 109.2h1.9M241.3 106.7h1.9"/>
<path d="M241.3 104.1h1.9M241.3 101.6h1.9M254.6 119.4h1.9M254.6 116.8h1.9M254.6 114.3h1.9M254.6 111.8h1.9M254.6 109.2h1.9M254.6 106.7h1.9M254.6 104.1h1.9M254.6 101.6h1.9M174 139.7h1.9M174 137.2h1.9"/>
<path d="M174 134.6h1.9M174 132.1h1.9M174 129.5h1.9M174 127h1.9M174 124.5h1.9M174 121.9h1.9M187.3 139.7h1.9M187.3 137.2h1.9M187.3 134.6h1.9M187.3 132.1h1.9M187.3 129.5h1.9M187.3 127h1.9"/>
<path d="M187.3 124.5h1.9M187.3 121.9h1.9M241.3 139.7h1.9M241.3 137.2h1.9M241.3 134.6h1.9M241.3 132.1h1.9M241.3 129.5h1.9M241.3 127h1.9M241.3 124.5h1.9M241.3 121.9h1.9M254.6 139.7h1.9M254.6 137.2h1.9"/>
<path d="M254.6 134.6h1.9M254.6 132.1h1.9M254.6 129.5h1.9M254.6 127h1.9M254.6 124.5h1.9M254.6 121.9h1.9M174 149.9h1.9M174 147.3h1.9M174 144.8h1.9M174 142.2h1.9M187.3 149.9h1.9M187.3 147.3h1.9"/>
<path d="M187.3 144.8h1.9M187.3 142.2h1.9M241.3 149.9h1.9M241.3 147.3h1.9M241.3 144.8h1.9M241.3 142.2h1.9M254.6 149.9h1.9M254.6 147.3h1.9M254.6 144.8h1.9M254.6 142.2h1.9"/>
</g>
<g fill="#840000" stroke="#840000" stroke-width=".15">
<path d="M174.6 48h1.6v.6h-1.6z"/>
<path d="M174.6 45.4h1.6v.7h-1.6z"/>
<path d="M174.6 42.9h1.6v.6h-1.6z"/>
<path d="M174.6 40.3h1.6v.7h-1.6z"/>
<path d="M174.6 37.8h1.6v.6h-1.6z"/>
<path d="M174.6 25.1h1.6v.6h-1.6z"/>
<path d="M187 149.6h1.6v.6h-1.6z"/>
<path d="M187 147h1.6v.7h-1.6z"/>
<path d="M187 144.5h1.6v.6h-1.6z"/>
<path d="M187 141.9h1.6v.6h-1.6z"/>
<path d="M187 139.4h1.6v.6h-1.6z"/>
<path d="M187 136.9h1.6v.6h-1.6z"/>
<path d="M187 134.3h1.6v.7h-1.6z"/>
<path d="M187 131.8h1.6v.6h-1.6z"/>
<path d="M187 129.2h1.6v.7h-1.6z"/>
<path d="M187 126.7h1.6v.6h-1.6z"/>
<path d="M187 124.2h1.6v.6h-1.6z"/>
<path d="M187 121.6h1.6v.7h-1.6z"/>
<path d="M187 119.1h1.6v.6h-1.6z"/>
<path d="M187 116.5h1.6v.7h-1.6z"/>
<path d="M187 114h1.6v.6h-1.6z"/>
<path d="M187 111.4h1.6v.7h-1.6z"/>
<path d="M187 108.9h1.6v.7h-1.6z"/>
<path d="M187 106.4h1.6v.6h-1.6z"/>
<path d="M187 103.8h1.6v.7h-1.6z"/>
<path d="M187 101.3h1.6v.6h-1.6z"/>
<path d="M187 98.8h1.6v.6h-1.6z"/>
<path d="M187 96.2h1.6v.7h-1.6z"/>
<path d="M187 93.7h1.6v.6h-1.6z"/>
<path d="M187 91.1h1.6v.7h-1.6z"/>
<path d="M187 88.6h1.6v.6h-1.6z"/>
<path d="M187 86h1.6v.7h-1.6z"/>
<path d="M187 83.5h1.6v.6h-1.6z"/>
<path d="M187 80.9h1.6v.7h-1.6z"/>
<path d="M187 78.4h1.6v.6h-1.6z"/>
<path d="M187 75.9h1.6v.6h-1.6z"/>
<path d="M187 73.4h1.6v.6h-1.6z"/>
<path d="M187 70.8h1.6v.6h-1.6z"/>
<path d="M187 68.2h1.6v.7h-1.6z"/>
<path d="M187 65.7h1.6v.6h-1.6z"/>
<path d="M187 63.2h1.6v.6h-1.6z"/>
<path d="M187 60.6h1.6v.7h-1.6z"/>
<path d="M187 58.1h1.6v.7h-1.6z"/>
<path d="M187 55.5h1.6v.7h-1.6z"/>
<path d="M187 53h1.6v.6h-1.6z"/>
<path d="M187 50.5h1.6v.6h-1.6z"/>
<path d="M187 48h1.6v.6h-1.6z"/>
<path d="M187 45.4h1.6v.6h-1.6z"/>
<path d="M187 42.8h1.6v.7h-1.6z"/>
<path d="M187 40.3h1.6v.6h-1.6z"/>
<path d="M187 37.8h1.6v.6h-1.6z"/>
<path d="M187 35.3h1.6v.6h-1.6z"/>
<path d="M187 32.7h1.6v.6h-1.6z"/>
<path d="M187 30.2h1.6v.6h-1.6z"/>
<path d="M187 27.6h1.6v.6h-1.6z"/>
<path d="M187 25.1h1.6v.6h-1.6z"/>
<path d="M241.9 48h1.6v.6h-1.6z"/>
<path d="M241.9 45.4h1.6v.7h-1.6z"/>
<path d="M241.9 42.9h1.6v.6h-1.6z"/>
<path d="M241.9 40.3h1.6v.7h-1.6z"/>
<path d="M241.9 37.8h1.6v.6h-1.6z"/>
<path d="M241.9 25.1h1.6v.6h-1.6z"/>
<path d="M254.3 149.6h1.6v.6h-1.6z"/>
<path d="M254.3 147h1.6v.7h-1.6z"/>
<path d="M254.3 144.5h1.6v.6h-1.6z"/>
<path d="M254.3 141.9h1.6v.6h-1.6z"/>
<path d="M254.3 139.4h1.6v.6h-1.6z"/>
<path d="M254.3 136.9h1.6v.6h-1.6z"/>
<path d="M254.3 134.3h1.6v.7h-1.6z"/>
<path d="M254.3 131.8h1.6v.6h-1.6z"/>
<path d="M254.3 129.2h1.6v.7h-1.6z"/>
<path d="M254.3 126.7h1.6v.6h-1.6z"/>
<path d="M254.3 124.2h1.6v.6h-1.6z"/>
<path d="M254.3 121.6h1.6v.7h-1.6z"/>
<path d="M254.3 119.1h1.6v.6h-1.6z"/>
<path d="M254.3 116.5h1.6v.7h-1.6z"/>
<path d="M254.3 114h1.6v.6h-1.6z"/>
<path d="M254.3 111.4h1.6v.7h-1.6z"/>
<path d="M254.3 108.9h1.6v.7h-1.6z"/>
<path d="M254.3 106.4h1.6v.6h-1.6z"/>
<path d="M254.3 103.8h1.6v.7h-1.6z"/>
<path d="M254.3 101.3h1.6v.6h-1.6z"/>
<path d="M254.3 98.8h1.6v.6h-1.6z"/>
<path d="M254.3 96.2h1.6v.7h-1.6z"/>
<path d="M254.3 93.7h1.6v.6h-1.6z"/>
<path d="M254.3 91.1h1.6v.7h-1.6z"/>
<path d="M254.3 88.6h1.6v.6h-1.6z"/>
<path d="M254.3 86h1.6v.7h-1.6z"/>
<path d="M254.3 83.5h1.6v.6h-1.6z"/>
<path d="M254.3 80.9h1.6v.7h-1.6z"/>
<path d="M254.3 78.4h1.6v.6h-1.6z"/>
<path d="M254.3 75.9h1.6v.6h-1.6z"/>
<path d="M254.3 73.4h1.6v.6h-1.6z"/>
<path d="M254.3 70.8h1.6v.6h-1.6z"/>
<path d="M254.3 68.2h1.6v.7h-1.6z"/>
<path d="M254.3 65.7h1.6v.6h-1.6z"/>
<path d="M254.3 63.2h1.6v.6h-1.6z"/>
<path d="M254.3 60.6h1.6v.7h-1.6z"/>
<path d="M254.3 58.1h1.6v.7h-1.6z"/>
<path d="M254.3 55.5h1.6v.7h-1.6z"/>
<path d="M254.3 53h1.6v.6h-1.6z"/>
<path d="M254.3 50.5h1.6v.6h-1.6z"/>
<path d="M254.3 48h1.6v.6h-1.6z"/>
<path d="M254.3 45.4h1.6v.6h-1.6z"/>
<path d="M254.3 42.8h1.6v.7h-1.6z"/>
<path d="M254.3 40.3h1.6v.6h-1.6z"/>
<path d="M254.3 37.8h1.6v.6h-1.6z"/>
<path d="M254.3 35.3h1.6v.6h-1.6z"/>
<path d="M254.3 32.7h1.6v.6h-1.6z"/>
<path d="M254.3 30.2h1.6v.6h-1.6z"/>
<path d="M254.3 27.6h1.6v.6h-1.6z"/>
<path d="M254.3 25.1h1.6v.6h-1.6z"/>
</g>
<g fill="none" stroke="#a90000" stroke-width=".15">
<path d="M171.6 37.7h.6M239 37.7h.5M171.6 50.4h.6M239 50.4h.5M171.6 63.1h.6M171.6 75.8h.6M239 63.1h.5M239 75.8h.5M171.6 88.5h.6M239 88.5h.5M171.6 101.2h.6M171.6 113.9h.6"/>
<path d="M239 101.2h.5M239 113.9h.5M171.6 126.6h.6M171.6 139.3h.6M239 126.6h.5M239 139.3h.5"/>
</g>
<path d="M121.4 116.2v-.2l.3-.1 .2 .8M122.3 116l.1 .2" fill="none" stroke="#0000c2" stroke-width=".15"/>
<g fill="none" stroke="#009600" stroke-width=".15">
<path d="M36.8 22.9h2.6M36.8 20.3h1.8M37.1 38.1h2.8M37.1 34.8h2.3M37.1 31.5h2.8M167.6 38.1h1.3M167.6 33h1.3M167.6 35.6h1.3M167.6 27.9h1.3M167.6 25.4h1.3M167.6 30.5h1.3M194.3 38.1h1.3"/>
<path d="M194.3 33h1.3M194.3 35.6h1.3M194.3 27.9h1.3M194.3 25.4h1.3M194.3 30.5h1.3M234.9 38.1h1.3M234.9 33h1.3M234.9 35.6h1.3M234.9 27.9h1.3M234.9 25.4h1.3M234.9 30.5h1.3M261.6 38.1h1.3"/>
<path d="M261.6 33h1.3M261.6 35.6h1.3M261.6 25.4h1.3M37.1 45.2h2.5M37.3 41.7h1.8M37.8 56.1h2.1M37.8 48.8h1.8M38.1 52.3h1.8M38.6 59.2h1.8M167.6 55.9h1.3M167.6 43.2h1.3M167.6 53.3h1.3"/>
<path d="M167.6 40.6h1.3M167.6 50.8h1.3M167.6 45.7h1.3M167.6 48.3h1.3M167.6 58.4h1.3M194.3 55.9h1.3M194.3 43.2h1.3M194.3 53.3h1.3M194.3 40.6h1.3M194.3 50.8h1.3M194.3 45.7h1.3M194.3 48.3h1.3"/>
<path d="M194.3 58.4h1.3M234.9 55.9h1.3M234.9 43.2h1.3M234.9 53.3h1.3M234.9 40.6h1.3M234.9 50.8h1.3M234.9 45.7h1.3M234.9 48.3h1.3M234.9 58.4h1.3M261.6 55.9h1.3M261.6 43.2h1.3M261.6 53.3h1.3"/>
<path d="M261.6 40.6h1.3M261.6 50.8h1.3M261.6 45.7h1.3M261.6 48.3h1.3M261.6 58.4h1.3M38.6 71.9h1.8M38.6 74.9h2M38.6 78.2h2M38.6 68.8h1.5M38.9 62.2h2M38.9 65.5h1.5M167.6 68.6h1.3"/>
<path d="M167.6 71.1h1.3M167.6 63.5h1.3M167.6 66h1.3M167.6 73.7h1.3M167.6 61h1.3M167.6 76.2h1.3M167.6 78.7h1.3M194.3 68.6h1.3M194.3 71.1h1.3M194.3 63.5h1.3M194.3 66h1.3M194.3 73.7h1.3"/>
<path d="M194.3 61h1.3M194.3 76.2h1.3M194.3 78.7h1.3M234.9 68.6h1.3M234.9 71.1h1.3M234.9 63.5h1.3M234.9 66h1.3M234.9 73.7h1.3M234.9 61h1.3M234.9 76.2h1.3M234.9 78.7h1.3M261.6 68.6h1.3"/>
<path d="M261.6 71.1h1.3M261.6 63.5h1.3M261.6 66h1.3M261.6 73.7h1.3M261.6 61h1.3M261.6 76.2h1.3M261.6 78.7h1.3M38.4 81.3h1.7M38.4 84.3h1.5M38.4 90.9h2.2M38.6 87.6h1.5M39.1 94h1.5"/>
<path d="M39.4 97.5h2M167.6 81.3h1.3M167.6 88.9h1.3M167.6 99.1h1.3M167.6 96.5h1.3M167.6 83.8h1.3M167.6 94h1.3M167.6 91.4h1.3M167.6 86.4h1.3M194.3 81.3h1.3M194.3 88.9h1.3M194.3 99.1h1.3"/>
<path d="M194.3 96.5h1.3M194.3 83.8h1.3M194.3 94h1.3M194.3 91.4h1.3M194.3 86.4h1.3M234.9 81.3h1.3M234.9 88.9h1.3M234.9 99.1h1.3M234.9 96.5h1.3M234.9 83.8h1.3M234.9 94h1.3M234.9 91.4h1.3"/>
<path d="M234.9 86.4h1.3M261.6 81.3h1.3M261.6 88.9h1.3M261.6 99.1h1.3M261.6 96.5h1.3M261.6 83.8h1.3M261.6 94h1.3M261.6 91.4h1.3M261.6 86.4h1.3M39.1 100.8h2.8M39.4 104.4h2M39.9 111.3h1.8"/>
<path d="M39.9 108h2.3M40.1 114.6h2.1M40.1 118.1h1.8M167.6 111.8h1.3M167.6 116.8h1.3M167.6 106.7h1.3M167.6 109.2h1.3M167.6 101.6h1.3M167.6 104.1h1.3M167.6 114.3h1.3M167.6 119.4h1.3M194.3 111.8h1.3"/>
<path d="M194.3 116.8h1.3M194.3 106.7h1.3M194.3 109.2h1.3M194.3 101.6h1.3M194.3 104.1h1.3M194.3 114.3h1.3M234.9 111.8h1.3M234.9 116.8h1.3M234.9 106.7h1.3M234.9 109.2h1.3M234.9 101.6h1.3M234.9 104.1h1.3"/>
<path d="M234.9 114.3h1.3M234.9 119.4h1.3M261.6 111.8h1.3M261.6 116.8h1.3M261.6 106.7h1.3M261.6 109.2h1.3M261.6 101.6h1.3M261.6 104.1h1.3M261.6 114.3h1.3M261.6 119.4h1.3M40.1 121.4h1.8M42.9 125.5h2.1"/>
<path d="M42.9 136.9h2.1M42.9 129.3h2.1M42.9 134.4h2.1M125.7 126.4v5M154.9 128.3h8.9M167.6 137.2h1.3M167.6 139.7h1.3M168.9 127h-5.1v2.5h5.1M168.9 121.9h-11.4v12.7h11.4M168.9 124.5h-7.6v7.6h7.6M194.3 129.5h1.3M194.3 127h1.3"/>
<path d="M194.3 121.9h1.3M194.3 137.2h1.3M194.3 139.7h1.3M194.3 134.6h1.3M194.3 132.1h1.3M194.3 124.5h1.3M234.9 129.5h1.3M234.9 127h1.3M234.9 121.9h1.3M234.9 137.2h1.3M234.9 139.7h1.3M234.9 134.6h1.3"/>
<path d="M234.9 132.1h1.3M234.9 124.5h1.3M261.6 129.5h1.3M261.6 127h1.3M261.6 121.9h1.3M261.6 137.2h1.3M261.6 139.7h1.3M261.6 134.6h1.3M261.6 132.1h1.3M261.6 124.5h1.3M40.4 153.2h4.8M41.4 156.7h3.6"/>
<path d="M41.9 149.4h3.8M42.4 141.2h2.8M42.9 144.5h1.8M167.6 147.3h1.3M167.6 144.8h1.3M167.6 149.9h1.3M167.6 142.2h1.3M194.3 147.3h1.3M194.3 144.8h1.3M194.3 149.9h1.3M194.3 142.2h1.3M234.9 147.3h1.3"/>
<path d="M234.9 144.8h1.3M234.9 149.9h1.3M234.9 142.2h1.3M248.4 155.4h.8M261.6 147.3h1.3M261.6 144.8h1.3M261.6 149.9h1.3M261.6 142.2h1.3M40.4 163.1h5.3M40.9 166.9h5.6M44.4 171.5h2.6M47 175.3h2.5"/>
<path d="M47 177.8h2.5M47 190.5h2.5M47 188h2.5M47 185.4h2.5M47 193h2.5M47 180.3h2.5M47 182.9h2.5"/>
</g>
<g fill="#009600" stroke="#009600" stroke-width=".15">
<circle cx="163.8" cy="128.3" r=".46"/>
<circle cx="161.3" cy="128.3" r=".46"/>
<circle cx="157.5" cy="128.3" r=".46"/>
</g>
<use href="#words"/>
</svg>
